VERSION 5.8 ;
BUSBITCHARS "[]" ;
DIVIDERCHAR "/" ;
UNITS
    DATABASE MICRONS 1000 ;
END UNITS

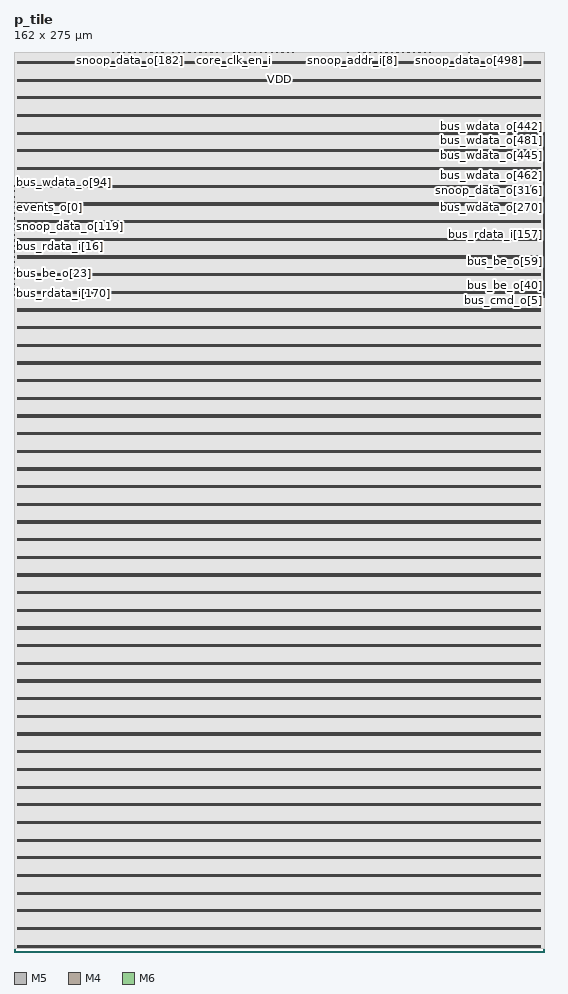
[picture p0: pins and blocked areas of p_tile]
MACRO p_tile
  FOREIGN p_tile 0 0 ;
  CLASS BLOCK ;
  SIZE 162 BY 275 ;
  PIN bus_addr_o[0]
    DIRECTION OUTPUT ;
    USE SIGNAL ;
    PORT
      LAYER M5 ;
        RECT  121.632 274.916 121.656 275 ;
    END
  END bus_addr_o[0]
  PIN bus_addr_o[10]
    DIRECTION OUTPUT ;
    USE SIGNAL ;
    PORT
      LAYER M4 ;
        RECT  0 207.072 0.084 207.096 ;
    END
  END bus_addr_o[10]
  PIN bus_addr_o[11]
    DIRECTION OUTPUT ;
    USE SIGNAL ;
    PORT
      LAYER M4 ;
        RECT  0 204.48 0.084 204.504 ;
    END
  END bus_addr_o[11]
  PIN bus_addr_o[12]
    DIRECTION OUTPUT ;
    USE SIGNAL ;
    PORT
      LAYER M4 ;
        RECT  0 204.384 0.084 204.408 ;
    END
  END bus_addr_o[12]
  PIN bus_addr_o[13]
    DIRECTION OUTPUT ;
    USE SIGNAL ;
    PORT
      LAYER M4 ;
        RECT  0 205.92 0.084 205.944 ;
    END
  END bus_addr_o[13]
  PIN bus_addr_o[14]
    DIRECTION OUTPUT ;
    USE SIGNAL ;
    PORT
      LAYER M4 ;
        RECT  0 200.64 0.084 200.664 ;
    END
  END bus_addr_o[14]
  PIN bus_addr_o[15]
    DIRECTION OUTPUT ;
    USE SIGNAL ;
    PORT
      LAYER M4 ;
        RECT  0 204.096 0.084 204.12 ;
    END
  END bus_addr_o[15]
  PIN bus_addr_o[16]
    DIRECTION OUTPUT ;
    USE SIGNAL ;
    PORT
      LAYER M4 ;
        RECT  0 206.88 0.084 206.904 ;
    END
  END bus_addr_o[16]
  PIN bus_addr_o[17]
    DIRECTION OUTPUT ;
    USE SIGNAL ;
    PORT
      LAYER M4 ;
        RECT  0 202.368 0.084 202.392 ;
    END
  END bus_addr_o[17]
  PIN bus_addr_o[18]
    DIRECTION OUTPUT ;
    USE SIGNAL ;
    PORT
      LAYER M4 ;
        RECT  0 206.112 0.084 206.136 ;
    END
  END bus_addr_o[18]
  PIN bus_addr_o[19]
    DIRECTION OUTPUT ;
    USE SIGNAL ;
    PORT
      LAYER M4 ;
        RECT  0 207.84 0.084 207.864 ;
    END
  END bus_addr_o[19]
  PIN bus_addr_o[1]
    DIRECTION OUTPUT ;
    USE SIGNAL ;
    PORT
      LAYER M5 ;
        RECT  106.656 274.916 106.68 275 ;
    END
  END bus_addr_o[1]
  PIN bus_addr_o[20]
    DIRECTION OUTPUT ;
    USE SIGNAL ;
    PORT
      LAYER M4 ;
        RECT  0 201.216 0.084 201.24 ;
    END
  END bus_addr_o[20]
  PIN bus_addr_o[21]
    DIRECTION OUTPUT ;
    USE SIGNAL ;
    PORT
      LAYER M4 ;
        RECT  0 202.272 0.084 202.296 ;
    END
  END bus_addr_o[21]
  PIN bus_addr_o[22]
    DIRECTION OUTPUT ;
    USE SIGNAL ;
    PORT
      LAYER M4 ;
        RECT  0 207.168 0.084 207.192 ;
    END
  END bus_addr_o[22]
  PIN bus_addr_o[23]
    DIRECTION OUTPUT ;
    USE SIGNAL ;
    PORT
      LAYER M4 ;
        RECT  0 204.864 0.084 204.888 ;
    END
  END bus_addr_o[23]
  PIN bus_addr_o[24]
    DIRECTION OUTPUT ;
    USE SIGNAL ;
    PORT
      LAYER M4 ;
        RECT  0 211.008 0.084 211.032 ;
    END
  END bus_addr_o[24]
  PIN bus_addr_o[25]
    DIRECTION OUTPUT ;
    USE SIGNAL ;
    PORT
      LAYER M4 ;
        RECT  0 209.472 0.084 209.496 ;
    END
  END bus_addr_o[25]
  PIN bus_addr_o[26]
    DIRECTION OUTPUT ;
    USE SIGNAL ;
    PORT
      LAYER M4 ;
        RECT  0 205.056 0.084 205.08 ;
    END
  END bus_addr_o[26]
  PIN bus_addr_o[27]
    DIRECTION OUTPUT ;
    USE SIGNAL ;
    PORT
      LAYER M4 ;
        RECT  0 211.392 0.084 211.416 ;
    END
  END bus_addr_o[27]
  PIN bus_addr_o[28]
    DIRECTION OUTPUT ;
    USE SIGNAL ;
    PORT
      LAYER M4 ;
        RECT  0 211.584 0.084 211.608 ;
    END
  END bus_addr_o[28]
  PIN bus_addr_o[29]
    DIRECTION OUTPUT ;
    USE SIGNAL ;
    PORT
      LAYER M4 ;
        RECT  0 204.672 0.084 204.696 ;
    END
  END bus_addr_o[29]
  PIN bus_addr_o[2]
    DIRECTION OUTPUT ;
    USE SIGNAL ;
    PORT
      LAYER M4 ;
        RECT  0 207.744 0.084 207.768 ;
    END
  END bus_addr_o[2]
  PIN bus_addr_o[30]
    DIRECTION OUTPUT ;
    USE SIGNAL ;
    PORT
      LAYER M4 ;
        RECT  0 209.76 0.084 209.784 ;
    END
  END bus_addr_o[30]
  PIN bus_addr_o[31]
    DIRECTION OUTPUT ;
    USE SIGNAL ;
    PORT
      LAYER M4 ;
        RECT  0 210.24 0.084 210.264 ;
    END
  END bus_addr_o[31]
  PIN bus_addr_o[32]
    DIRECTION OUTPUT ;
    USE SIGNAL ;
    PORT
      LAYER M5 ;
        RECT  121.344 274.916 121.368 275 ;
    END
  END bus_addr_o[32]
  PIN bus_addr_o[33]
    DIRECTION OUTPUT ;
    USE SIGNAL ;
    PORT
      LAYER M5 ;
        RECT  121.728 274.916 121.752 275 ;
    END
  END bus_addr_o[33]
  PIN bus_addr_o[34]
    DIRECTION OUTPUT ;
    USE SIGNAL ;
    PORT
      LAYER M4 ;
        RECT  161.916 203.232 162 203.256 ;
    END
  END bus_addr_o[34]
  PIN bus_addr_o[35]
    DIRECTION OUTPUT ;
    USE SIGNAL ;
    PORT
      LAYER M4 ;
        RECT  161.916 206.496 162 206.52 ;
    END
  END bus_addr_o[35]
  PIN bus_addr_o[36]
    DIRECTION OUTPUT ;
    USE SIGNAL ;
    PORT
      LAYER M4 ;
        RECT  161.916 208.608 162 208.632 ;
    END
  END bus_addr_o[36]
  PIN bus_addr_o[37]
    DIRECTION OUTPUT ;
    USE SIGNAL ;
    PORT
      LAYER M4 ;
        RECT  161.916 205.92 162 205.944 ;
    END
  END bus_addr_o[37]
  PIN bus_addr_o[38]
    DIRECTION OUTPUT ;
    USE SIGNAL ;
    PORT
      LAYER M4 ;
        RECT  161.916 204.48 162 204.504 ;
    END
  END bus_addr_o[38]
  PIN bus_addr_o[39]
    DIRECTION OUTPUT ;
    USE SIGNAL ;
    PORT
      LAYER M4 ;
        RECT  161.916 206.016 162 206.04 ;
    END
  END bus_addr_o[39]
  PIN bus_addr_o[3]
    DIRECTION OUTPUT ;
    USE SIGNAL ;
    PORT
      LAYER M4 ;
        RECT  0 213.408 0.084 213.432 ;
    END
  END bus_addr_o[3]
  PIN bus_addr_o[40]
    DIRECTION OUTPUT ;
    USE SIGNAL ;
    PORT
      LAYER M4 ;
        RECT  161.916 208.128 162 208.152 ;
    END
  END bus_addr_o[40]
  PIN bus_addr_o[41]
    DIRECTION OUTPUT ;
    USE SIGNAL ;
    PORT
      LAYER M4 ;
        RECT  161.916 207.456 162 207.48 ;
    END
  END bus_addr_o[41]
  PIN bus_addr_o[42]
    DIRECTION OUTPUT ;
    USE SIGNAL ;
    PORT
      LAYER M4 ;
        RECT  161.916 210.816 162 210.84 ;
    END
  END bus_addr_o[42]
  PIN bus_addr_o[43]
    DIRECTION OUTPUT ;
    USE SIGNAL ;
    PORT
      LAYER M4 ;
        RECT  161.916 206.784 162 206.808 ;
    END
  END bus_addr_o[43]
  PIN bus_addr_o[44]
    DIRECTION OUTPUT ;
    USE SIGNAL ;
    PORT
      LAYER M4 ;
        RECT  161.916 205.344 162 205.368 ;
    END
  END bus_addr_o[44]
  PIN bus_addr_o[45]
    DIRECTION OUTPUT ;
    USE SIGNAL ;
    PORT
      LAYER M4 ;
        RECT  161.916 206.976 162 207 ;
    END
  END bus_addr_o[45]
  PIN bus_addr_o[46]
    DIRECTION OUTPUT ;
    USE SIGNAL ;
    PORT
      LAYER M4 ;
        RECT  161.916 204.384 162 204.408 ;
    END
  END bus_addr_o[46]
  PIN bus_addr_o[47]
    DIRECTION OUTPUT ;
    USE SIGNAL ;
    PORT
      LAYER M4 ;
        RECT  161.916 204.768 162 204.792 ;
    END
  END bus_addr_o[47]
  PIN bus_addr_o[48]
    DIRECTION OUTPUT ;
    USE SIGNAL ;
    PORT
      LAYER M4 ;
        RECT  161.916 203.904 162 203.928 ;
    END
  END bus_addr_o[48]
  PIN bus_addr_o[49]
    DIRECTION OUTPUT ;
    USE SIGNAL ;
    PORT
      LAYER M4 ;
        RECT  161.916 204.576 162 204.6 ;
    END
  END bus_addr_o[49]
  PIN bus_addr_o[4]
    DIRECTION OUTPUT ;
    USE SIGNAL ;
    PORT
      LAYER M4 ;
        RECT  0 205.632 0.084 205.656 ;
    END
  END bus_addr_o[4]
  PIN bus_addr_o[50]
    DIRECTION OUTPUT ;
    USE SIGNAL ;
    PORT
      LAYER M4 ;
        RECT  161.916 202.08 162 202.104 ;
    END
  END bus_addr_o[50]
  PIN bus_addr_o[51]
    DIRECTION OUTPUT ;
    USE SIGNAL ;
    PORT
      LAYER M4 ;
        RECT  161.916 205.632 162 205.656 ;
    END
  END bus_addr_o[51]
  PIN bus_addr_o[52]
    DIRECTION OUTPUT ;
    USE SIGNAL ;
    PORT
      LAYER M4 ;
        RECT  161.916 208.224 162 208.248 ;
    END
  END bus_addr_o[52]
  PIN bus_addr_o[53]
    DIRECTION OUTPUT ;
    USE SIGNAL ;
    PORT
      LAYER M4 ;
        RECT  161.916 207.072 162 207.096 ;
    END
  END bus_addr_o[53]
  PIN bus_addr_o[54]
    DIRECTION OUTPUT ;
    USE SIGNAL ;
    PORT
      LAYER M4 ;
        RECT  161.916 208.704 162 208.728 ;
    END
  END bus_addr_o[54]
  PIN bus_addr_o[55]
    DIRECTION OUTPUT ;
    USE SIGNAL ;
    PORT
      LAYER M4 ;
        RECT  161.916 203.328 162 203.352 ;
    END
  END bus_addr_o[55]
  PIN bus_addr_o[56]
    DIRECTION OUTPUT ;
    USE SIGNAL ;
    PORT
      LAYER M4 ;
        RECT  161.916 208.896 162 208.92 ;
    END
  END bus_addr_o[56]
  PIN bus_addr_o[57]
    DIRECTION OUTPUT ;
    USE SIGNAL ;
    PORT
      LAYER M4 ;
        RECT  161.916 204.192 162 204.216 ;
    END
  END bus_addr_o[57]
  PIN bus_addr_o[58]
    DIRECTION OUTPUT ;
    USE SIGNAL ;
    PORT
      LAYER M4 ;
        RECT  161.916 209.184 162 209.208 ;
    END
  END bus_addr_o[58]
  PIN bus_addr_o[59]
    DIRECTION OUTPUT ;
    USE SIGNAL ;
    PORT
      LAYER M4 ;
        RECT  161.916 207.264 162 207.288 ;
    END
  END bus_addr_o[59]
  PIN bus_addr_o[5]
    DIRECTION OUTPUT ;
    USE SIGNAL ;
    PORT
      LAYER M4 ;
        RECT  0 211.776 0.084 211.8 ;
    END
  END bus_addr_o[5]
  PIN bus_addr_o[60]
    DIRECTION OUTPUT ;
    USE SIGNAL ;
    PORT
      LAYER M4 ;
        RECT  161.916 205.728 162 205.752 ;
    END
  END bus_addr_o[60]
  PIN bus_addr_o[61]
    DIRECTION OUTPUT ;
    USE SIGNAL ;
    PORT
      LAYER M4 ;
        RECT  161.916 211.392 162 211.416 ;
    END
  END bus_addr_o[61]
  PIN bus_addr_o[62]
    DIRECTION OUTPUT ;
    USE SIGNAL ;
    PORT
      LAYER M4 ;
        RECT  161.916 203.808 162 203.832 ;
    END
  END bus_addr_o[62]
  PIN bus_addr_o[63]
    DIRECTION OUTPUT ;
    USE SIGNAL ;
    PORT
      LAYER M4 ;
        RECT  161.916 205.824 162 205.848 ;
    END
  END bus_addr_o[63]
  PIN bus_addr_o[6]
    DIRECTION OUTPUT ;
    USE SIGNAL ;
    PORT
      LAYER M4 ;
        RECT  0 207.552 0.084 207.576 ;
    END
  END bus_addr_o[6]
  PIN bus_addr_o[7]
    DIRECTION OUTPUT ;
    USE SIGNAL ;
    PORT
      LAYER M4 ;
        RECT  0 209.952 0.084 209.976 ;
    END
  END bus_addr_o[7]
  PIN bus_addr_o[8]
    DIRECTION OUTPUT ;
    USE SIGNAL ;
    PORT
      LAYER M4 ;
        RECT  0 200.544 0.084 200.568 ;
    END
  END bus_addr_o[8]
  PIN bus_addr_o[9]
    DIRECTION OUTPUT ;
    USE SIGNAL ;
    PORT
      LAYER M4 ;
        RECT  0 200.256 0.084 200.28 ;
    END
  END bus_addr_o[9]
  PIN bus_be_o[0]
    DIRECTION OUTPUT ;
    USE SIGNAL ;
    PORT
      LAYER M4 ;
        RECT  0 201.6 0.084 201.624 ;
    END
  END bus_be_o[0]
  PIN bus_be_o[10]
    DIRECTION OUTPUT ;
    USE SIGNAL ;
    PORT
      LAYER M4 ;
        RECT  0 212.544 0.084 212.568 ;
    END
  END bus_be_o[10]
  PIN bus_be_o[11]
    DIRECTION OUTPUT ;
    USE SIGNAL ;
    PORT
      LAYER M4 ;
        RECT  0 205.536 0.084 205.56 ;
    END
  END bus_be_o[11]
  PIN bus_be_o[12]
    DIRECTION OUTPUT ;
    USE SIGNAL ;
    PORT
      LAYER M4 ;
        RECT  0 210.912 0.084 210.936 ;
    END
  END bus_be_o[12]
  PIN bus_be_o[13]
    DIRECTION OUTPUT ;
    USE SIGNAL ;
    PORT
      LAYER M4 ;
        RECT  0 204.96 0.084 204.984 ;
    END
  END bus_be_o[13]
  PIN bus_be_o[14]
    DIRECTION OUTPUT ;
    USE SIGNAL ;
    PORT
      LAYER M4 ;
        RECT  0 208.512 0.084 208.536 ;
    END
  END bus_be_o[14]
  PIN bus_be_o[15]
    DIRECTION OUTPUT ;
    USE SIGNAL ;
    PORT
      LAYER M4 ;
        RECT  0 204.192 0.084 204.216 ;
    END
  END bus_be_o[15]
  PIN bus_be_o[16]
    DIRECTION OUTPUT ;
    USE SIGNAL ;
    PORT
      LAYER M4 ;
        RECT  0 212.064 0.084 212.088 ;
    END
  END bus_be_o[16]
  PIN bus_be_o[17]
    DIRECTION OUTPUT ;
    USE SIGNAL ;
    PORT
      LAYER M4 ;
        RECT  0 210.816 0.084 210.84 ;
    END
  END bus_be_o[17]
  PIN bus_be_o[18]
    DIRECTION OUTPUT ;
    USE SIGNAL ;
    PORT
      LAYER M4 ;
        RECT  0 210.528 0.084 210.552 ;
    END
  END bus_be_o[18]
  PIN bus_be_o[19]
    DIRECTION OUTPUT ;
    USE SIGNAL ;
    PORT
      LAYER M4 ;
        RECT  0 202.944 0.084 202.968 ;
    END
  END bus_be_o[19]
  PIN bus_be_o[1]
    DIRECTION OUTPUT ;
    USE SIGNAL ;
    PORT
      LAYER M4 ;
        RECT  0 210.624 0.084 210.648 ;
    END
  END bus_be_o[1]
  PIN bus_be_o[20]
    DIRECTION OUTPUT ;
    USE SIGNAL ;
    PORT
      LAYER M4 ;
        RECT  0 212.256 0.084 212.28 ;
    END
  END bus_be_o[20]
  PIN bus_be_o[21]
    DIRECTION OUTPUT ;
    USE SIGNAL ;
    PORT
      LAYER M4 ;
        RECT  0 208.8 0.084 208.824 ;
    END
  END bus_be_o[21]
  PIN bus_be_o[22]
    DIRECTION OUTPUT ;
    USE SIGNAL ;
    PORT
      LAYER M4 ;
        RECT  0 207.456 0.084 207.48 ;
    END
  END bus_be_o[22]
  PIN bus_be_o[23]
    DIRECTION OUTPUT ;
    USE SIGNAL ;
    PORT
      LAYER M4 ;
        RECT  0 207.36 0.084 207.384 ;
    END
  END bus_be_o[23]
  PIN bus_be_o[24]
    DIRECTION OUTPUT ;
    USE SIGNAL ;
    PORT
      LAYER M4 ;
        RECT  0 200.736 0.084 200.76 ;
    END
  END bus_be_o[24]
  PIN bus_be_o[25]
    DIRECTION OUTPUT ;
    USE SIGNAL ;
    PORT
      LAYER M4 ;
        RECT  0 202.176 0.084 202.2 ;
    END
  END bus_be_o[25]
  PIN bus_be_o[26]
    DIRECTION OUTPUT ;
    USE SIGNAL ;
    PORT
      LAYER M4 ;
        RECT  0 205.824 0.084 205.848 ;
    END
  END bus_be_o[26]
  PIN bus_be_o[27]
    DIRECTION OUTPUT ;
    USE SIGNAL ;
    PORT
      LAYER M4 ;
        RECT  0 206.688 0.084 206.712 ;
    END
  END bus_be_o[27]
  PIN bus_be_o[28]
    DIRECTION OUTPUT ;
    USE SIGNAL ;
    PORT
      LAYER M4 ;
        RECT  0 202.08 0.084 202.104 ;
    END
  END bus_be_o[28]
  PIN bus_be_o[29]
    DIRECTION OUTPUT ;
    USE SIGNAL ;
    PORT
      LAYER M4 ;
        RECT  0 214.176 0.084 214.2 ;
    END
  END bus_be_o[29]
  PIN bus_be_o[2]
    DIRECTION OUTPUT ;
    USE SIGNAL ;
    PORT
      LAYER M4 ;
        RECT  0 210.048 0.084 210.072 ;
    END
  END bus_be_o[2]
  PIN bus_be_o[30]
    DIRECTION OUTPUT ;
    USE SIGNAL ;
    PORT
      LAYER M4 ;
        RECT  0 210.144 0.084 210.168 ;
    END
  END bus_be_o[30]
  PIN bus_be_o[31]
    DIRECTION OUTPUT ;
    USE SIGNAL ;
    PORT
      LAYER M4 ;
        RECT  0 200.352 0.084 200.376 ;
    END
  END bus_be_o[31]
  PIN bus_be_o[32]
    DIRECTION OUTPUT ;
    USE SIGNAL ;
    PORT
      LAYER M4 ;
        RECT  161.916 206.592 162 206.616 ;
    END
  END bus_be_o[32]
  PIN bus_be_o[33]
    DIRECTION OUTPUT ;
    USE SIGNAL ;
    PORT
      LAYER M4 ;
        RECT  161.916 211.2 162 211.224 ;
    END
  END bus_be_o[33]
  PIN bus_be_o[34]
    DIRECTION OUTPUT ;
    USE SIGNAL ;
    PORT
      LAYER M4 ;
        RECT  161.916 210.144 162 210.168 ;
    END
  END bus_be_o[34]
  PIN bus_be_o[35]
    DIRECTION OUTPUT ;
    USE SIGNAL ;
    PORT
      LAYER M4 ;
        RECT  161.916 203.52 162 203.544 ;
    END
  END bus_be_o[35]
  PIN bus_be_o[36]
    DIRECTION OUTPUT ;
    USE SIGNAL ;
    PORT
      LAYER M4 ;
        RECT  161.916 209.376 162 209.4 ;
    END
  END bus_be_o[36]
  PIN bus_be_o[37]
    DIRECTION OUTPUT ;
    USE SIGNAL ;
    PORT
      LAYER M4 ;
        RECT  161.916 203.712 162 203.736 ;
    END
  END bus_be_o[37]
  PIN bus_be_o[38]
    DIRECTION OUTPUT ;
    USE SIGNAL ;
    PORT
      LAYER M4 ;
        RECT  161.916 207.648 162 207.672 ;
    END
  END bus_be_o[38]
  PIN bus_be_o[39]
    DIRECTION OUTPUT ;
    USE SIGNAL ;
    PORT
      LAYER M4 ;
        RECT  161.916 206.304 162 206.328 ;
    END
  END bus_be_o[39]
  PIN bus_be_o[3]
    DIRECTION OUTPUT ;
    USE SIGNAL ;
    PORT
      LAYER M4 ;
        RECT  0 205.728 0.084 205.752 ;
    END
  END bus_be_o[3]
  PIN bus_be_o[40]
    DIRECTION OUTPUT ;
    USE SIGNAL ;
    PORT
      LAYER M4 ;
        RECT  161.916 203.616 162 203.64 ;
    END
  END bus_be_o[40]
  PIN bus_be_o[41]
    DIRECTION OUTPUT ;
    USE SIGNAL ;
    PORT
      LAYER M4 ;
        RECT  161.916 208.8 162 208.824 ;
    END
  END bus_be_o[41]
  PIN bus_be_o[42]
    DIRECTION OUTPUT ;
    USE SIGNAL ;
    PORT
      LAYER M4 ;
        RECT  161.916 208.032 162 208.056 ;
    END
  END bus_be_o[42]
  PIN bus_be_o[43]
    DIRECTION OUTPUT ;
    USE SIGNAL ;
    PORT
      LAYER M4 ;
        RECT  161.916 205.44 162 205.464 ;
    END
  END bus_be_o[43]
  PIN bus_be_o[44]
    DIRECTION OUTPUT ;
    USE SIGNAL ;
    PORT
      LAYER M4 ;
        RECT  161.916 211.008 162 211.032 ;
    END
  END bus_be_o[44]
  PIN bus_be_o[45]
    DIRECTION OUTPUT ;
    USE SIGNAL ;
    PORT
      LAYER M4 ;
        RECT  161.916 207.936 162 207.96 ;
    END
  END bus_be_o[45]
  PIN bus_be_o[46]
    DIRECTION OUTPUT ;
    USE SIGNAL ;
    PORT
      LAYER M4 ;
        RECT  161.916 205.248 162 205.272 ;
    END
  END bus_be_o[46]
  PIN bus_be_o[47]
    DIRECTION OUTPUT ;
    USE SIGNAL ;
    PORT
      LAYER M4 ;
        RECT  161.916 211.776 162 211.8 ;
    END
  END bus_be_o[47]
  PIN bus_be_o[48]
    DIRECTION OUTPUT ;
    USE SIGNAL ;
    PORT
      LAYER M4 ;
        RECT  161.916 202.944 162 202.968 ;
    END
  END bus_be_o[48]
  PIN bus_be_o[49]
    DIRECTION OUTPUT ;
    USE SIGNAL ;
    PORT
      LAYER M4 ;
        RECT  161.916 210.432 162 210.456 ;
    END
  END bus_be_o[49]
  PIN bus_be_o[4]
    DIRECTION OUTPUT ;
    USE SIGNAL ;
    PORT
      LAYER M4 ;
        RECT  0 200.928 0.084 200.952 ;
    END
  END bus_be_o[4]
  PIN bus_be_o[50]
    DIRECTION OUTPUT ;
    USE SIGNAL ;
    PORT
      LAYER M4 ;
        RECT  161.916 203.136 162 203.16 ;
    END
  END bus_be_o[50]
  PIN bus_be_o[51]
    DIRECTION OUTPUT ;
    USE SIGNAL ;
    PORT
      LAYER M4 ;
        RECT  161.916 205.536 162 205.56 ;
    END
  END bus_be_o[51]
  PIN bus_be_o[52]
    DIRECTION OUTPUT ;
    USE SIGNAL ;
    PORT
      LAYER M4 ;
        RECT  161.916 209.952 162 209.976 ;
    END
  END bus_be_o[52]
  PIN bus_be_o[53]
    DIRECTION OUTPUT ;
    USE SIGNAL ;
    PORT
      LAYER M4 ;
        RECT  161.916 205.056 162 205.08 ;
    END
  END bus_be_o[53]
  PIN bus_be_o[54]
    DIRECTION OUTPUT ;
    USE SIGNAL ;
    PORT
      LAYER M4 ;
        RECT  161.916 204.288 162 204.312 ;
    END
  END bus_be_o[54]
  PIN bus_be_o[55]
    DIRECTION OUTPUT ;
    USE SIGNAL ;
    PORT
      LAYER M4 ;
        RECT  161.916 208.416 162 208.44 ;
    END
  END bus_be_o[55]
  PIN bus_be_o[56]
    DIRECTION OUTPUT ;
    USE SIGNAL ;
    PORT
      LAYER M4 ;
        RECT  161.916 206.88 162 206.904 ;
    END
  END bus_be_o[56]
  PIN bus_be_o[57]
    DIRECTION OUTPUT ;
    USE SIGNAL ;
    PORT
      LAYER M4 ;
        RECT  161.916 205.152 162 205.176 ;
    END
  END bus_be_o[57]
  PIN bus_be_o[58]
    DIRECTION OUTPUT ;
    USE SIGNAL ;
    PORT
      LAYER M4 ;
        RECT  161.916 210.336 162 210.36 ;
    END
  END bus_be_o[58]
  PIN bus_be_o[59]
    DIRECTION OUTPUT ;
    USE SIGNAL ;
    PORT
      LAYER M4 ;
        RECT  161.916 211.104 162 211.128 ;
    END
  END bus_be_o[59]
  PIN bus_be_o[5]
    DIRECTION OUTPUT ;
    USE SIGNAL ;
    PORT
      LAYER M4 ;
        RECT  0 206.4 0.084 206.424 ;
    END
  END bus_be_o[5]
  PIN bus_be_o[60]
    DIRECTION OUTPUT ;
    USE SIGNAL ;
    PORT
      LAYER M4 ;
        RECT  161.916 207.552 162 207.576 ;
    END
  END bus_be_o[60]
  PIN bus_be_o[61]
    DIRECTION OUTPUT ;
    USE SIGNAL ;
    PORT
      LAYER M4 ;
        RECT  161.916 210.624 162 210.648 ;
    END
  END bus_be_o[61]
  PIN bus_be_o[62]
    DIRECTION OUTPUT ;
    USE SIGNAL ;
    PORT
      LAYER M4 ;
        RECT  161.916 206.112 162 206.136 ;
    END
  END bus_be_o[62]
  PIN bus_be_o[63]
    DIRECTION OUTPUT ;
    USE SIGNAL ;
    PORT
      LAYER M4 ;
        RECT  161.916 207.36 162 207.384 ;
    END
  END bus_be_o[63]
  PIN bus_be_o[6]
    DIRECTION OUTPUT ;
    USE SIGNAL ;
    PORT
      LAYER M4 ;
        RECT  0 207.264 0.084 207.288 ;
    END
  END bus_be_o[6]
  PIN bus_be_o[7]
    DIRECTION OUTPUT ;
    USE SIGNAL ;
    PORT
      LAYER M4 ;
        RECT  0 210.72 0.084 210.744 ;
    END
  END bus_be_o[7]
  PIN bus_be_o[8]
    DIRECTION OUTPUT ;
    USE SIGNAL ;
    PORT
      LAYER M4 ;
        RECT  0 208.704 0.084 208.728 ;
    END
  END bus_be_o[8]
  PIN bus_be_o[9]
    DIRECTION OUTPUT ;
    USE SIGNAL ;
    PORT
      LAYER M4 ;
        RECT  0 203.04 0.084 203.064 ;
    END
  END bus_be_o[9]
  PIN bus_cmd_o[0]
    DIRECTION OUTPUT ;
    USE SIGNAL ;
    PORT
      LAYER M4 ;
        RECT  0 206.016 0.084 206.04 ;
    END
  END bus_cmd_o[0]
  PIN bus_cmd_o[1]
    DIRECTION OUTPUT ;
    USE SIGNAL ;
    PORT
      LAYER M4 ;
        RECT  0 211.968 0.084 211.992 ;
    END
  END bus_cmd_o[1]
  PIN bus_cmd_o[2]
    DIRECTION OUTPUT ;
    USE SIGNAL ;
    PORT
      LAYER M4 ;
        RECT  0 212.928 0.084 212.952 ;
    END
  END bus_cmd_o[2]
  PIN bus_cmd_o[3]
    DIRECTION OUTPUT ;
    USE SIGNAL ;
    PORT
      LAYER M4 ;
        RECT  161.916 209.472 162 209.496 ;
    END
  END bus_cmd_o[3]
  PIN bus_cmd_o[4]
    DIRECTION OUTPUT ;
    USE SIGNAL ;
    PORT
      LAYER M4 ;
        RECT  161.916 208.512 162 208.536 ;
    END
  END bus_cmd_o[4]
  PIN bus_cmd_o[5]
    DIRECTION OUTPUT ;
    USE SIGNAL ;
    PORT
      LAYER M4 ;
        RECT  161.916 201.504 162 201.528 ;
    END
  END bus_cmd_o[5]
  PIN bus_done_i[0]
    DIRECTION INPUT ;
    USE SIGNAL ;
    PORT
      LAYER M4 ;
        RECT  0 207.936 0.084 207.96 ;
    END
  END bus_done_i[0]
  PIN bus_done_i[1]
    DIRECTION INPUT ;
    USE SIGNAL ;
    PORT
      LAYER M4 ;
        RECT  161.916 209.856 162 209.88 ;
    END
  END bus_done_i[1]
  PIN bus_err_i
    DIRECTION INPUT ;
    USE SIGNAL ;
    PORT
      LAYER M4 ;
        RECT  161.916 200.352 162 200.376 ;
    END
  END bus_err_i
  PIN bus_rdata_i[0]
    DIRECTION INPUT ;
    USE SIGNAL ;
    PORT
      LAYER M4 ;
        RECT  161.916 201.696 162 201.72 ;
    END
  END bus_rdata_i[0]
  PIN bus_rdata_i[100]
    DIRECTION INPUT ;
    USE SIGNAL ;
    PORT
      LAYER M4 ;
        RECT  161.916 206.208 162 206.232 ;
    END
  END bus_rdata_i[100]
  PIN bus_rdata_i[101]
    DIRECTION INPUT ;
    USE SIGNAL ;
    PORT
      LAYER M4 ;
        RECT  161.916 210.24 162 210.264 ;
    END
  END bus_rdata_i[101]
  PIN bus_rdata_i[102]
    DIRECTION INPUT ;
    USE SIGNAL ;
    PORT
      LAYER M4 ;
        RECT  161.916 206.4 162 206.424 ;
    END
  END bus_rdata_i[102]
  PIN bus_rdata_i[103]
    DIRECTION INPUT ;
    USE SIGNAL ;
    PORT
      LAYER M4 ;
        RECT  161.916 203.04 162 203.064 ;
    END
  END bus_rdata_i[103]
  PIN bus_rdata_i[104]
    DIRECTION INPUT ;
    USE SIGNAL ;
    PORT
      LAYER M4 ;
        RECT  161.916 202.272 162 202.296 ;
    END
  END bus_rdata_i[104]
  PIN bus_rdata_i[105]
    DIRECTION INPUT ;
    USE SIGNAL ;
    PORT
      LAYER M4 ;
        RECT  161.916 200.64 162 200.664 ;
    END
  END bus_rdata_i[105]
  PIN bus_rdata_i[106]
    DIRECTION INPUT ;
    USE SIGNAL ;
    PORT
      LAYER M4 ;
        RECT  161.916 201.216 162 201.24 ;
    END
  END bus_rdata_i[106]
  PIN bus_rdata_i[107]
    DIRECTION INPUT ;
    USE SIGNAL ;
    PORT
      LAYER M4 ;
        RECT  161.916 204.096 162 204.12 ;
    END
  END bus_rdata_i[107]
  PIN bus_rdata_i[108]
    DIRECTION INPUT ;
    USE SIGNAL ;
    PORT
      LAYER M4 ;
        RECT  161.916 202.368 162 202.392 ;
    END
  END bus_rdata_i[108]
  PIN bus_rdata_i[109]
    DIRECTION INPUT ;
    USE SIGNAL ;
    PORT
      LAYER M4 ;
        RECT  161.916 211.488 162 211.512 ;
    END
  END bus_rdata_i[109]
  PIN bus_rdata_i[10]
    DIRECTION INPUT ;
    USE SIGNAL ;
    PORT
      LAYER M4 ;
        RECT  161.916 200.256 162 200.28 ;
    END
  END bus_rdata_i[10]
  PIN bus_rdata_i[110]
    DIRECTION INPUT ;
    USE SIGNAL ;
    PORT
      LAYER M4 ;
        RECT  161.916 201.6 162 201.624 ;
    END
  END bus_rdata_i[110]
  PIN bus_rdata_i[111]
    DIRECTION INPUT ;
    USE SIGNAL ;
    PORT
      LAYER M4 ;
        RECT  161.916 201.408 162 201.432 ;
    END
  END bus_rdata_i[111]
  PIN bus_rdata_i[112]
    DIRECTION INPUT ;
    USE SIGNAL ;
    PORT
      LAYER M4 ;
        RECT  161.916 200.544 162 200.568 ;
    END
  END bus_rdata_i[112]
  PIN bus_rdata_i[113]
    DIRECTION INPUT ;
    USE SIGNAL ;
    PORT
      LAYER M4 ;
        RECT  161.916 201.024 162 201.048 ;
    END
  END bus_rdata_i[113]
  PIN bus_rdata_i[114]
    DIRECTION INPUT ;
    USE SIGNAL ;
    PORT
      LAYER M4 ;
        RECT  161.916 200.064 162 200.088 ;
    END
  END bus_rdata_i[114]
  PIN bus_rdata_i[115]
    DIRECTION INPUT ;
    USE SIGNAL ;
    PORT
      LAYER M4 ;
        RECT  161.916 211.872 162 211.896 ;
    END
  END bus_rdata_i[115]
  PIN bus_rdata_i[116]
    DIRECTION INPUT ;
    USE SIGNAL ;
    PORT
      LAYER M4 ;
        RECT  161.916 200.736 162 200.76 ;
    END
  END bus_rdata_i[116]
  PIN bus_rdata_i[117]
    DIRECTION INPUT ;
    USE SIGNAL ;
    PORT
      LAYER M4 ;
        RECT  161.916 200.448 162 200.472 ;
    END
  END bus_rdata_i[117]
  PIN bus_rdata_i[118]
    DIRECTION INPUT ;
    USE SIGNAL ;
    PORT
      LAYER M4 ;
        RECT  161.916 201.12 162 201.144 ;
    END
  END bus_rdata_i[118]
  PIN bus_rdata_i[119]
    DIRECTION INPUT ;
    USE SIGNAL ;
    PORT
      LAYER M4 ;
        RECT  161.916 208.992 162 209.016 ;
    END
  END bus_rdata_i[119]
  PIN bus_rdata_i[11]
    DIRECTION INPUT ;
    USE SIGNAL ;
    PORT
      LAYER M4 ;
        RECT  161.916 200.928 162 200.952 ;
    END
  END bus_rdata_i[11]
  PIN bus_rdata_i[120]
    DIRECTION INPUT ;
    USE SIGNAL ;
    PORT
      LAYER M4 ;
        RECT  161.916 204.96 162 204.984 ;
    END
  END bus_rdata_i[120]
  PIN bus_rdata_i[121]
    DIRECTION INPUT ;
    USE SIGNAL ;
    PORT
      LAYER M4 ;
        RECT  161.916 201.312 162 201.336 ;
    END
  END bus_rdata_i[121]
  PIN bus_rdata_i[122]
    DIRECTION INPUT ;
    USE SIGNAL ;
    PORT
      LAYER M4 ;
        RECT  161.916 209.664 162 209.688 ;
    END
  END bus_rdata_i[122]
  PIN bus_rdata_i[123]
    DIRECTION INPUT ;
    USE SIGNAL ;
    PORT
      LAYER M4 ;
        RECT  161.916 209.76 162 209.784 ;
    END
  END bus_rdata_i[123]
  PIN bus_rdata_i[124]
    DIRECTION INPUT ;
    USE SIGNAL ;
    PORT
      LAYER M4 ;
        RECT  161.916 209.568 162 209.592 ;
    END
  END bus_rdata_i[124]
  PIN bus_rdata_i[125]
    DIRECTION INPUT ;
    USE SIGNAL ;
    PORT
      LAYER M4 ;
        RECT  161.916 202.848 162 202.872 ;
    END
  END bus_rdata_i[125]
  PIN bus_rdata_i[126]
    DIRECTION INPUT ;
    USE SIGNAL ;
    PORT
      LAYER M4 ;
        RECT  161.916 201.888 162 201.912 ;
    END
  END bus_rdata_i[126]
  PIN bus_rdata_i[127]
    DIRECTION INPUT ;
    USE SIGNAL ;
    PORT
      LAYER M4 ;
        RECT  161.916 209.088 162 209.112 ;
    END
  END bus_rdata_i[127]
  PIN bus_rdata_i[128]
    DIRECTION INPUT ;
    USE SIGNAL ;
    PORT
      LAYER M4 ;
        RECT  161.916 211.296 162 211.32 ;
    END
  END bus_rdata_i[128]
  PIN bus_rdata_i[129]
    DIRECTION INPUT ;
    USE SIGNAL ;
    PORT
      LAYER M4 ;
        RECT  161.916 202.464 162 202.488 ;
    END
  END bus_rdata_i[129]
  PIN bus_rdata_i[12]
    DIRECTION INPUT ;
    USE SIGNAL ;
    PORT
      LAYER M4 ;
        RECT  161.916 202.752 162 202.776 ;
    END
  END bus_rdata_i[12]
  PIN bus_rdata_i[130]
    DIRECTION INPUT ;
    USE SIGNAL ;
    PORT
      LAYER M4 ;
        RECT  161.916 203.424 162 203.448 ;
    END
  END bus_rdata_i[130]
  PIN bus_rdata_i[131]
    DIRECTION INPUT ;
    USE SIGNAL ;
    PORT
      LAYER M4 ;
        RECT  161.916 201.984 162 202.008 ;
    END
  END bus_rdata_i[131]
  PIN bus_rdata_i[132]
    DIRECTION INPUT ;
    USE SIGNAL ;
    PORT
      LAYER M4 ;
        RECT  161.916 207.744 162 207.768 ;
    END
  END bus_rdata_i[132]
  PIN bus_rdata_i[133]
    DIRECTION INPUT ;
    USE SIGNAL ;
    PORT
      LAYER M4 ;
        RECT  161.916 209.28 162 209.304 ;
    END
  END bus_rdata_i[133]
  PIN bus_rdata_i[134]
    DIRECTION INPUT ;
    USE SIGNAL ;
    PORT
      LAYER M4 ;
        RECT  161.916 207.168 162 207.192 ;
    END
  END bus_rdata_i[134]
  PIN bus_rdata_i[135]
    DIRECTION INPUT ;
    USE SIGNAL ;
    PORT
      LAYER M4 ;
        RECT  161.916 200.832 162 200.856 ;
    END
  END bus_rdata_i[135]
  PIN bus_rdata_i[136]
    DIRECTION INPUT ;
    USE SIGNAL ;
    PORT
      LAYER M4 ;
        RECT  161.916 210.048 162 210.072 ;
    END
  END bus_rdata_i[136]
  PIN bus_rdata_i[137]
    DIRECTION INPUT ;
    USE SIGNAL ;
    PORT
      LAYER M4 ;
        RECT  161.916 201.792 162 201.816 ;
    END
  END bus_rdata_i[137]
  PIN bus_rdata_i[138]
    DIRECTION INPUT ;
    USE SIGNAL ;
    PORT
      LAYER M4 ;
        RECT  161.916 204.672 162 204.696 ;
    END
  END bus_rdata_i[138]
  PIN bus_rdata_i[139]
    DIRECTION INPUT ;
    USE SIGNAL ;
    PORT
      LAYER M4 ;
        RECT  161.916 211.584 162 211.608 ;
    END
  END bus_rdata_i[139]
  PIN bus_rdata_i[13]
    DIRECTION INPUT ;
    USE SIGNAL ;
    PORT
      LAYER M4 ;
        RECT  161.916 206.688 162 206.712 ;
    END
  END bus_rdata_i[13]
  PIN bus_rdata_i[140]
    DIRECTION INPUT ;
    USE SIGNAL ;
    PORT
      LAYER M4 ;
        RECT  161.916 202.656 162 202.68 ;
    END
  END bus_rdata_i[140]
  PIN bus_rdata_i[141]
    DIRECTION INPUT ;
    USE SIGNAL ;
    PORT
      LAYER M4 ;
        RECT  161.916 202.56 162 202.584 ;
    END
  END bus_rdata_i[141]
  PIN bus_rdata_i[142]
    DIRECTION INPUT ;
    USE SIGNAL ;
    PORT
      LAYER M4 ;
        RECT  161.916 202.176 162 202.2 ;
    END
  END bus_rdata_i[142]
  PIN bus_rdata_i[143]
    DIRECTION INPUT ;
    USE SIGNAL ;
    PORT
      LAYER M4 ;
        RECT  161.916 210.528 162 210.552 ;
    END
  END bus_rdata_i[143]
  PIN bus_rdata_i[144]
    DIRECTION INPUT ;
    USE SIGNAL ;
    PORT
      LAYER M4 ;
        RECT  161.916 204.864 162 204.888 ;
    END
  END bus_rdata_i[144]
  PIN bus_rdata_i[145]
    DIRECTION INPUT ;
    USE SIGNAL ;
    PORT
      LAYER M4 ;
        RECT  161.916 208.32 162 208.344 ;
    END
  END bus_rdata_i[145]
  PIN bus_rdata_i[146]
    DIRECTION INPUT ;
    USE SIGNAL ;
    PORT
      LAYER M4 ;
        RECT  161.916 204 162 204.024 ;
    END
  END bus_rdata_i[146]
  PIN bus_rdata_i[147]
    DIRECTION INPUT ;
    USE SIGNAL ;
    PORT
      LAYER M4 ;
        RECT  161.916 210.912 162 210.936 ;
    END
  END bus_rdata_i[147]
  PIN bus_rdata_i[148]
    DIRECTION INPUT ;
    USE SIGNAL ;
    PORT
      LAYER M4 ;
        RECT  161.916 210.72 162 210.744 ;
    END
  END bus_rdata_i[148]
  PIN bus_rdata_i[149]
    DIRECTION INPUT ;
    USE SIGNAL ;
    PORT
      LAYER M4 ;
        RECT  161.916 207.84 162 207.864 ;
    END
  END bus_rdata_i[149]
  PIN bus_rdata_i[14]
    DIRECTION INPUT ;
    USE SIGNAL ;
    PORT
      LAYER M4 ;
        RECT  161.916 200.16 162 200.184 ;
    END
  END bus_rdata_i[14]
  PIN bus_rdata_i[150]
    DIRECTION INPUT ;
    USE SIGNAL ;
    PORT
      LAYER M4 ;
        RECT  161.916 211.68 162 211.704 ;
    END
  END bus_rdata_i[150]
  PIN bus_rdata_i[151]
    DIRECTION INPUT ;
    USE SIGNAL ;
    PORT
      LAYER M4 ;
        RECT  0 202.752 0.084 202.776 ;
    END
  END bus_rdata_i[151]
  PIN bus_rdata_i[152]
    DIRECTION INPUT ;
    USE SIGNAL ;
    PORT
      LAYER M4 ;
        RECT  0 214.464 0.084 214.488 ;
    END
  END bus_rdata_i[152]
  PIN bus_rdata_i[153]
    DIRECTION INPUT ;
    USE SIGNAL ;
    PORT
      LAYER M4 ;
        RECT  0 205.344 0.084 205.368 ;
    END
  END bus_rdata_i[153]
  PIN bus_rdata_i[154]
    DIRECTION INPUT ;
    USE SIGNAL ;
    PORT
      LAYER M4 ;
        RECT  0 212.16 0.084 212.184 ;
    END
  END bus_rdata_i[154]
  PIN bus_rdata_i[155]
    DIRECTION INPUT ;
    USE SIGNAL ;
    PORT
      LAYER M4 ;
        RECT  0 201.408 0.084 201.432 ;
    END
  END bus_rdata_i[155]
  PIN bus_rdata_i[156]
    DIRECTION INPUT ;
    USE SIGNAL ;
    PORT
      LAYER M4 ;
        RECT  0 213.6 0.084 213.624 ;
    END
  END bus_rdata_i[156]
  PIN bus_rdata_i[157]
    DIRECTION INPUT ;
    USE SIGNAL ;
    PORT
      LAYER M4 ;
        RECT  161.916 219.36 162 219.384 ;
    END
  END bus_rdata_i[157]
  PIN bus_rdata_i[158]
    DIRECTION INPUT ;
    USE SIGNAL ;
    PORT
      LAYER M4 ;
        RECT  161.916 220.32 162 220.344 ;
    END
  END bus_rdata_i[158]
  PIN bus_rdata_i[159]
    DIRECTION INPUT ;
    USE SIGNAL ;
    PORT
      LAYER M4 ;
        RECT  0 207.648 0.084 207.672 ;
    END
  END bus_rdata_i[159]
  PIN bus_rdata_i[15]
    DIRECTION INPUT ;
    USE SIGNAL ;
    PORT
      LAYER M4 ;
        RECT  0 212.448 0.084 212.472 ;
    END
  END bus_rdata_i[15]
  PIN bus_rdata_i[160]
    DIRECTION INPUT ;
    USE SIGNAL ;
    PORT
      LAYER M4 ;
        RECT  0 205.248 0.084 205.272 ;
    END
  END bus_rdata_i[160]
  PIN bus_rdata_i[161]
    DIRECTION INPUT ;
    USE SIGNAL ;
    PORT
      LAYER M4 ;
        RECT  0 213.312 0.084 213.336 ;
    END
  END bus_rdata_i[161]
  PIN bus_rdata_i[162]
    DIRECTION INPUT ;
    USE SIGNAL ;
    PORT
      LAYER M4 ;
        RECT  0 200.832 0.084 200.856 ;
    END
  END bus_rdata_i[162]
  PIN bus_rdata_i[163]
    DIRECTION INPUT ;
    USE SIGNAL ;
    PORT
      LAYER M4 ;
        RECT  0 206.592 0.084 206.616 ;
    END
  END bus_rdata_i[163]
  PIN bus_rdata_i[164]
    DIRECTION INPUT ;
    USE SIGNAL ;
    PORT
      LAYER M4 ;
        RECT  0 215.52 0.084 215.544 ;
    END
  END bus_rdata_i[164]
  PIN bus_rdata_i[165]
    DIRECTION INPUT ;
    USE SIGNAL ;
    PORT
      LAYER M4 ;
        RECT  0 208.416 0.084 208.44 ;
    END
  END bus_rdata_i[165]
  PIN bus_rdata_i[166]
    DIRECTION INPUT ;
    USE SIGNAL ;
    PORT
      LAYER M4 ;
        RECT  0 209.568 0.084 209.592 ;
    END
  END bus_rdata_i[166]
  PIN bus_rdata_i[167]
    DIRECTION INPUT ;
    USE SIGNAL ;
    PORT
      LAYER M4 ;
        RECT  0 208.992 0.084 209.016 ;
    END
  END bus_rdata_i[167]
  PIN bus_rdata_i[168]
    DIRECTION INPUT ;
    USE SIGNAL ;
    PORT
      LAYER M4 ;
        RECT  0 203.328 0.084 203.352 ;
    END
  END bus_rdata_i[168]
  PIN bus_rdata_i[169]
    DIRECTION INPUT ;
    USE SIGNAL ;
    PORT
      LAYER M4 ;
        RECT  0 203.904 0.084 203.928 ;
    END
  END bus_rdata_i[169]
  PIN bus_rdata_i[16]
    DIRECTION INPUT ;
    USE SIGNAL ;
    PORT
      LAYER M4 ;
        RECT  0 215.616 0.084 215.64 ;
    END
  END bus_rdata_i[16]
  PIN bus_rdata_i[170]
    DIRECTION INPUT ;
    USE SIGNAL ;
    PORT
      LAYER M4 ;
        RECT  0 203.616 0.084 203.64 ;
    END
  END bus_rdata_i[170]
  PIN bus_rdata_i[171]
    DIRECTION INPUT ;
    USE SIGNAL ;
    PORT
      LAYER M4 ;
        RECT  161.916 212.928 162 212.952 ;
    END
  END bus_rdata_i[171]
  PIN bus_rdata_i[172]
    DIRECTION INPUT ;
    USE SIGNAL ;
    PORT
      LAYER M4 ;
        RECT  0 206.976 0.084 207 ;
    END
  END bus_rdata_i[172]
  PIN bus_rdata_i[173]
    DIRECTION INPUT ;
    USE SIGNAL ;
    PORT
      LAYER M4 ;
        RECT  0 209.856 0.084 209.88 ;
    END
  END bus_rdata_i[173]
  PIN bus_rdata_i[174]
    DIRECTION INPUT ;
    USE SIGNAL ;
    PORT
      LAYER M4 ;
        RECT  161.916 222.144 162 222.168 ;
    END
  END bus_rdata_i[174]
  PIN bus_rdata_i[175]
    DIRECTION INPUT ;
    USE SIGNAL ;
    PORT
      LAYER M4 ;
        RECT  0 208.032 0.084 208.056 ;
    END
  END bus_rdata_i[175]
  PIN bus_rdata_i[176]
    DIRECTION INPUT ;
    USE SIGNAL ;
    PORT
      LAYER M4 ;
        RECT  0 201.312 0.084 201.336 ;
    END
  END bus_rdata_i[176]
  PIN bus_rdata_i[177]
    DIRECTION INPUT ;
    USE SIGNAL ;
    PORT
      LAYER M4 ;
        RECT  0 211.104 0.084 211.128 ;
    END
  END bus_rdata_i[177]
  PIN bus_rdata_i[178]
    DIRECTION INPUT ;
    USE SIGNAL ;
    PORT
      LAYER M4 ;
        RECT  0 208.32 0.084 208.344 ;
    END
  END bus_rdata_i[178]
  PIN bus_rdata_i[179]
    DIRECTION INPUT ;
    USE SIGNAL ;
    PORT
      LAYER M4 ;
        RECT  0 204.768 0.084 204.792 ;
    END
  END bus_rdata_i[179]
  PIN bus_rdata_i[17]
    DIRECTION INPUT ;
    USE SIGNAL ;
    PORT
      LAYER M4 ;
        RECT  0 215.424 0.084 215.448 ;
    END
  END bus_rdata_i[17]
  PIN bus_rdata_i[180]
    DIRECTION INPUT ;
    USE SIGNAL ;
    PORT
      LAYER M4 ;
        RECT  0 202.848 0.084 202.872 ;
    END
  END bus_rdata_i[180]
  PIN bus_rdata_i[181]
    DIRECTION INPUT ;
    USE SIGNAL ;
    PORT
      LAYER M4 ;
        RECT  0 213.504 0.084 213.528 ;
    END
  END bus_rdata_i[181]
  PIN bus_rdata_i[182]
    DIRECTION INPUT ;
    USE SIGNAL ;
    PORT
      LAYER M4 ;
        RECT  161.916 220.032 162 220.056 ;
    END
  END bus_rdata_i[182]
  PIN bus_rdata_i[183]
    DIRECTION INPUT ;
    USE SIGNAL ;
    PORT
      LAYER M4 ;
        RECT  161.916 213.024 162 213.048 ;
    END
  END bus_rdata_i[183]
  PIN bus_rdata_i[184]
    DIRECTION INPUT ;
    USE SIGNAL ;
    PORT
      LAYER M4 ;
        RECT  0 208.608 0.084 208.632 ;
    END
  END bus_rdata_i[184]
  PIN bus_rdata_i[185]
    DIRECTION INPUT ;
    USE SIGNAL ;
    PORT
      LAYER M4 ;
        RECT  0 203.712 0.084 203.736 ;
    END
  END bus_rdata_i[185]
  PIN bus_rdata_i[186]
    DIRECTION INPUT ;
    USE SIGNAL ;
    PORT
      LAYER M4 ;
        RECT  0 211.68 0.084 211.704 ;
    END
  END bus_rdata_i[186]
  PIN bus_rdata_i[187]
    DIRECTION INPUT ;
    USE SIGNAL ;
    PORT
      LAYER M4 ;
        RECT  161.916 215.616 162 215.64 ;
    END
  END bus_rdata_i[187]
  PIN bus_rdata_i[188]
    DIRECTION INPUT ;
    USE SIGNAL ;
    PORT
      LAYER M4 ;
        RECT  0 211.296 0.084 211.32 ;
    END
  END bus_rdata_i[188]
  PIN bus_rdata_i[189]
    DIRECTION INPUT ;
    USE SIGNAL ;
    PORT
      LAYER M4 ;
        RECT  161.916 216.768 162 216.792 ;
    END
  END bus_rdata_i[189]
  PIN bus_rdata_i[18]
    DIRECTION INPUT ;
    USE SIGNAL ;
    PORT
      LAYER M4 ;
        RECT  0 214.944 0.084 214.968 ;
    END
  END bus_rdata_i[18]
  PIN bus_rdata_i[190]
    DIRECTION INPUT ;
    USE SIGNAL ;
    PORT
      LAYER M4 ;
        RECT  161.916 219.168 162 219.192 ;
    END
  END bus_rdata_i[190]
  PIN bus_rdata_i[191]
    DIRECTION INPUT ;
    USE SIGNAL ;
    PORT
      LAYER M4 ;
        RECT  161.916 222.816 162 222.84 ;
    END
  END bus_rdata_i[191]
  PIN bus_rdata_i[192]
    DIRECTION INPUT ;
    USE SIGNAL ;
    PORT
      LAYER M4 ;
        RECT  0 208.224 0.084 208.248 ;
    END
  END bus_rdata_i[192]
  PIN bus_rdata_i[193]
    DIRECTION INPUT ;
    USE SIGNAL ;
    PORT
      LAYER M4 ;
        RECT  161.916 219.744 162 219.768 ;
    END
  END bus_rdata_i[193]
  PIN bus_rdata_i[194]
    DIRECTION INPUT ;
    USE SIGNAL ;
    PORT
      LAYER M4 ;
        RECT  161.916 226.656 162 226.68 ;
    END
  END bus_rdata_i[194]
  PIN bus_rdata_i[195]
    DIRECTION INPUT ;
    USE SIGNAL ;
    PORT
      LAYER M4 ;
        RECT  161.916 217.728 162 217.752 ;
    END
  END bus_rdata_i[195]
  PIN bus_rdata_i[196]
    DIRECTION INPUT ;
    USE SIGNAL ;
    PORT
      LAYER M4 ;
        RECT  0 211.872 0.084 211.896 ;
    END
  END bus_rdata_i[196]
  PIN bus_rdata_i[197]
    DIRECTION INPUT ;
    USE SIGNAL ;
    PORT
      LAYER M4 ;
        RECT  0 203.136 0.084 203.16 ;
    END
  END bus_rdata_i[197]
  PIN bus_rdata_i[198]
    DIRECTION INPUT ;
    USE SIGNAL ;
    PORT
      LAYER M4 ;
        RECT  161.916 219.264 162 219.288 ;
    END
  END bus_rdata_i[198]
  PIN bus_rdata_i[199]
    DIRECTION INPUT ;
    USE SIGNAL ;
    PORT
      LAYER M4 ;
        RECT  161.916 230.88 162 230.904 ;
    END
  END bus_rdata_i[199]
  PIN bus_rdata_i[19]
    DIRECTION INPUT ;
    USE SIGNAL ;
    PORT
      LAYER M4 ;
        RECT  161.916 213.216 162 213.24 ;
    END
  END bus_rdata_i[19]
  PIN bus_rdata_i[1]
    DIRECTION INPUT ;
    USE SIGNAL ;
    PORT
      LAYER M4 ;
        RECT  0 209.376 0.084 209.4 ;
    END
  END bus_rdata_i[1]
  PIN bus_rdata_i[200]
    DIRECTION INPUT ;
    USE SIGNAL ;
    PORT
      LAYER M4 ;
        RECT  161.916 218.496 162 218.52 ;
    END
  END bus_rdata_i[200]
  PIN bus_rdata_i[201]
    DIRECTION INPUT ;
    USE SIGNAL ;
    PORT
      LAYER M4 ;
        RECT  161.916 221.568 162 221.592 ;
    END
  END bus_rdata_i[201]
  PIN bus_rdata_i[202]
    DIRECTION INPUT ;
    USE SIGNAL ;
    PORT
      LAYER M4 ;
        RECT  161.916 216.96 162 216.984 ;
    END
  END bus_rdata_i[202]
  PIN bus_rdata_i[203]
    DIRECTION INPUT ;
    USE SIGNAL ;
    PORT
      LAYER M4 ;
        RECT  161.916 220.896 162 220.92 ;
    END
  END bus_rdata_i[203]
  PIN bus_rdata_i[204]
    DIRECTION INPUT ;
    USE SIGNAL ;
    PORT
      LAYER M4 ;
        RECT  161.916 220.224 162 220.248 ;
    END
  END bus_rdata_i[204]
  PIN bus_rdata_i[205]
    DIRECTION INPUT ;
    USE SIGNAL ;
    PORT
      LAYER M4 ;
        RECT  161.916 227.712 162 227.736 ;
    END
  END bus_rdata_i[205]
  PIN bus_rdata_i[206]
    DIRECTION INPUT ;
    USE SIGNAL ;
    PORT
      LAYER M4 ;
        RECT  161.916 225.504 162 225.528 ;
    END
  END bus_rdata_i[206]
  PIN bus_rdata_i[207]
    DIRECTION INPUT ;
    USE SIGNAL ;
    PORT
      LAYER M4 ;
        RECT  161.916 215.808 162 215.832 ;
    END
  END bus_rdata_i[207]
  PIN bus_rdata_i[208]
    DIRECTION INPUT ;
    USE SIGNAL ;
    PORT
      LAYER M4 ;
        RECT  161.916 218.976 162 219 ;
    END
  END bus_rdata_i[208]
  PIN bus_rdata_i[209]
    DIRECTION INPUT ;
    USE SIGNAL ;
    PORT
      LAYER M4 ;
        RECT  161.916 217.632 162 217.656 ;
    END
  END bus_rdata_i[209]
  PIN bus_rdata_i[20]
    DIRECTION INPUT ;
    USE SIGNAL ;
    PORT
      LAYER M4 ;
        RECT  0 206.208 0.084 206.232 ;
    END
  END bus_rdata_i[20]
  PIN bus_rdata_i[210]
    DIRECTION INPUT ;
    USE SIGNAL ;
    PORT
      LAYER M4 ;
        RECT  161.916 218.208 162 218.232 ;
    END
  END bus_rdata_i[210]
  PIN bus_rdata_i[211]
    DIRECTION INPUT ;
    USE SIGNAL ;
    PORT
      LAYER M4 ;
        RECT  161.916 218.688 162 218.712 ;
    END
  END bus_rdata_i[211]
  PIN bus_rdata_i[212]
    DIRECTION INPUT ;
    USE SIGNAL ;
    PORT
      LAYER M4 ;
        RECT  161.916 224.064 162 224.088 ;
    END
  END bus_rdata_i[212]
  PIN bus_rdata_i[213]
    DIRECTION INPUT ;
    USE SIGNAL ;
    PORT
      LAYER M4 ;
        RECT  161.916 220.128 162 220.152 ;
    END
  END bus_rdata_i[213]
  PIN bus_rdata_i[214]
    DIRECTION INPUT ;
    USE SIGNAL ;
    PORT
      LAYER M4 ;
        RECT  161.916 216.672 162 216.696 ;
    END
  END bus_rdata_i[214]
  PIN bus_rdata_i[215]
    DIRECTION INPUT ;
    USE SIGNAL ;
    PORT
      LAYER M4 ;
        RECT  161.916 218.592 162 218.616 ;
    END
  END bus_rdata_i[215]
  PIN bus_rdata_i[216]
    DIRECTION INPUT ;
    USE SIGNAL ;
    PORT
      LAYER M4 ;
        RECT  161.916 229.92 162 229.944 ;
    END
  END bus_rdata_i[216]
  PIN bus_rdata_i[217]
    DIRECTION INPUT ;
    USE SIGNAL ;
    PORT
      LAYER M4 ;
        RECT  161.916 220.608 162 220.632 ;
    END
  END bus_rdata_i[217]
  PIN bus_rdata_i[218]
    DIRECTION INPUT ;
    USE SIGNAL ;
    PORT
      LAYER M4 ;
        RECT  0 209.28 0.084 209.304 ;
    END
  END bus_rdata_i[218]
  PIN bus_rdata_i[219]
    DIRECTION INPUT ;
    USE SIGNAL ;
    PORT
      LAYER M4 ;
        RECT  161.916 224.832 162 224.856 ;
    END
  END bus_rdata_i[219]
  PIN bus_rdata_i[21]
    DIRECTION INPUT ;
    USE SIGNAL ;
    PORT
      LAYER M4 ;
        RECT  0 213.792 0.084 213.816 ;
    END
  END bus_rdata_i[21]
  PIN bus_rdata_i[220]
    DIRECTION INPUT ;
    USE SIGNAL ;
    PORT
      LAYER M4 ;
        RECT  161.916 218.112 162 218.136 ;
    END
  END bus_rdata_i[220]
  PIN bus_rdata_i[221]
    DIRECTION INPUT ;
    USE SIGNAL ;
    PORT
      LAYER M4 ;
        RECT  161.916 214.656 162 214.68 ;
    END
  END bus_rdata_i[221]
  PIN bus_rdata_i[222]
    DIRECTION INPUT ;
    USE SIGNAL ;
    PORT
      LAYER M4 ;
        RECT  161.916 226.944 162 226.968 ;
    END
  END bus_rdata_i[222]
  PIN bus_rdata_i[223]
    DIRECTION INPUT ;
    USE SIGNAL ;
    PORT
      LAYER M4 ;
        RECT  161.916 222.048 162 222.072 ;
    END
  END bus_rdata_i[223]
  PIN bus_rdata_i[224]
    DIRECTION INPUT ;
    USE SIGNAL ;
    PORT
      LAYER M4 ;
        RECT  161.916 218.4 162 218.424 ;
    END
  END bus_rdata_i[224]
  PIN bus_rdata_i[225]
    DIRECTION INPUT ;
    USE SIGNAL ;
    PORT
      LAYER M4 ;
        RECT  161.916 228.576 162 228.6 ;
    END
  END bus_rdata_i[225]
  PIN bus_rdata_i[226]
    DIRECTION INPUT ;
    USE SIGNAL ;
    PORT
      LAYER M4 ;
        RECT  161.916 225.024 162 225.048 ;
    END
  END bus_rdata_i[226]
  PIN bus_rdata_i[227]
    DIRECTION INPUT ;
    USE SIGNAL ;
    PORT
      LAYER M4 ;
        RECT  161.916 226.56 162 226.584 ;
    END
  END bus_rdata_i[227]
  PIN bus_rdata_i[228]
    DIRECTION INPUT ;
    USE SIGNAL ;
    PORT
      LAYER M4 ;
        RECT  161.916 217.344 162 217.368 ;
    END
  END bus_rdata_i[228]
  PIN bus_rdata_i[229]
    DIRECTION INPUT ;
    USE SIGNAL ;
    PORT
      LAYER M4 ;
        RECT  161.916 224.256 162 224.28 ;
    END
  END bus_rdata_i[229]
  PIN bus_rdata_i[22]
    DIRECTION INPUT ;
    USE SIGNAL ;
    PORT
      LAYER M4 ;
        RECT  0 206.496 0.084 206.52 ;
    END
  END bus_rdata_i[22]
  PIN bus_rdata_i[230]
    DIRECTION INPUT ;
    USE SIGNAL ;
    PORT
      LAYER M4 ;
        RECT  161.916 225.216 162 225.24 ;
    END
  END bus_rdata_i[230]
  PIN bus_rdata_i[231]
    DIRECTION INPUT ;
    USE SIGNAL ;
    PORT
      LAYER M4 ;
        RECT  161.916 218.016 162 218.04 ;
    END
  END bus_rdata_i[231]
  PIN bus_rdata_i[232]
    DIRECTION INPUT ;
    USE SIGNAL ;
    PORT
      LAYER M4 ;
        RECT  161.916 214.368 162 214.392 ;
    END
  END bus_rdata_i[232]
  PIN bus_rdata_i[233]
    DIRECTION INPUT ;
    USE SIGNAL ;
    PORT
      LAYER M4 ;
        RECT  0 208.128 0.084 208.152 ;
    END
  END bus_rdata_i[233]
  PIN bus_rdata_i[234]
    DIRECTION INPUT ;
    USE SIGNAL ;
    PORT
      LAYER M4 ;
        RECT  161.916 213.12 162 213.144 ;
    END
  END bus_rdata_i[234]
  PIN bus_rdata_i[235]
    DIRECTION INPUT ;
    USE SIGNAL ;
    PORT
      LAYER M4 ;
        RECT  161.916 223.392 162 223.416 ;
    END
  END bus_rdata_i[235]
  PIN bus_rdata_i[236]
    DIRECTION INPUT ;
    USE SIGNAL ;
    PORT
      LAYER M4 ;
        RECT  161.916 216 162 216.024 ;
    END
  END bus_rdata_i[236]
  PIN bus_rdata_i[237]
    DIRECTION INPUT ;
    USE SIGNAL ;
    PORT
      LAYER M4 ;
        RECT  161.916 227.136 162 227.16 ;
    END
  END bus_rdata_i[237]
  PIN bus_rdata_i[238]
    DIRECTION INPUT ;
    USE SIGNAL ;
    PORT
      LAYER M4 ;
        RECT  161.916 228.864 162 228.888 ;
    END
  END bus_rdata_i[238]
  PIN bus_rdata_i[239]
    DIRECTION INPUT ;
    USE SIGNAL ;
    PORT
      LAYER M4 ;
        RECT  161.916 217.056 162 217.08 ;
    END
  END bus_rdata_i[239]
  PIN bus_rdata_i[23]
    DIRECTION INPUT ;
    USE SIGNAL ;
    PORT
      LAYER M4 ;
        RECT  0 213.984 0.084 214.008 ;
    END
  END bus_rdata_i[23]
  PIN bus_rdata_i[240]
    DIRECTION INPUT ;
    USE SIGNAL ;
    PORT
      LAYER M4 ;
        RECT  161.916 215.712 162 215.736 ;
    END
  END bus_rdata_i[240]
  PIN bus_rdata_i[241]
    DIRECTION INPUT ;
    USE SIGNAL ;
    PORT
      LAYER M4 ;
        RECT  161.916 213.6 162 213.624 ;
    END
  END bus_rdata_i[241]
  PIN bus_rdata_i[242]
    DIRECTION INPUT ;
    USE SIGNAL ;
    PORT
      LAYER M4 ;
        RECT  161.916 214.176 162 214.2 ;
    END
  END bus_rdata_i[242]
  PIN bus_rdata_i[243]
    DIRECTION INPUT ;
    USE SIGNAL ;
    PORT
      LAYER M4 ;
        RECT  161.916 217.824 162 217.848 ;
    END
  END bus_rdata_i[243]
  PIN bus_rdata_i[244]
    DIRECTION INPUT ;
    USE SIGNAL ;
    PORT
      LAYER M4 ;
        RECT  161.916 223.584 162 223.608 ;
    END
  END bus_rdata_i[244]
  PIN bus_rdata_i[245]
    DIRECTION INPUT ;
    USE SIGNAL ;
    PORT
      LAYER M4 ;
        RECT  161.916 213.984 162 214.008 ;
    END
  END bus_rdata_i[245]
  PIN bus_rdata_i[246]
    DIRECTION INPUT ;
    USE SIGNAL ;
    PORT
      LAYER M4 ;
        RECT  161.916 228 162 228.024 ;
    END
  END bus_rdata_i[246]
  PIN bus_rdata_i[247]
    DIRECTION INPUT ;
    USE SIGNAL ;
    PORT
      LAYER M4 ;
        RECT  161.916 213.408 162 213.432 ;
    END
  END bus_rdata_i[247]
  PIN bus_rdata_i[248]
    DIRECTION INPUT ;
    USE SIGNAL ;
    PORT
      LAYER M4 ;
        RECT  0 201.888 0.084 201.912 ;
    END
  END bus_rdata_i[248]
  PIN bus_rdata_i[249]
    DIRECTION INPUT ;
    USE SIGNAL ;
    PORT
      LAYER M4 ;
        RECT  0 201.792 0.084 201.816 ;
    END
  END bus_rdata_i[249]
  PIN bus_rdata_i[24]
    DIRECTION INPUT ;
    USE SIGNAL ;
    PORT
      LAYER M4 ;
        RECT  0 215.04 0.084 215.064 ;
    END
  END bus_rdata_i[24]
  PIN bus_rdata_i[250]
    DIRECTION INPUT ;
    USE SIGNAL ;
    PORT
      LAYER M4 ;
        RECT  0 210.432 0.084 210.456 ;
    END
  END bus_rdata_i[250]
  PIN bus_rdata_i[251]
    DIRECTION INPUT ;
    USE SIGNAL ;
    PORT
      LAYER M4 ;
        RECT  161.916 225.408 162 225.432 ;
    END
  END bus_rdata_i[251]
  PIN bus_rdata_i[252]
    DIRECTION INPUT ;
    USE SIGNAL ;
    PORT
      LAYER M4 ;
        RECT  0 203.808 0.084 203.832 ;
    END
  END bus_rdata_i[252]
  PIN bus_rdata_i[253]
    DIRECTION INPUT ;
    USE SIGNAL ;
    PORT
      LAYER M4 ;
        RECT  161.916 230.496 162 230.52 ;
    END
  END bus_rdata_i[253]
  PIN bus_rdata_i[254]
    DIRECTION INPUT ;
    USE SIGNAL ;
    PORT
      LAYER M4 ;
        RECT  161.916 229.536 162 229.56 ;
    END
  END bus_rdata_i[254]
  PIN bus_rdata_i[255]
    DIRECTION INPUT ;
    USE SIGNAL ;
    PORT
      LAYER M4 ;
        RECT  161.916 227.904 162 227.928 ;
    END
  END bus_rdata_i[255]
  PIN bus_rdata_i[25]
    DIRECTION INPUT ;
    USE SIGNAL ;
    PORT
      LAYER M4 ;
        RECT  0 202.656 0.084 202.68 ;
    END
  END bus_rdata_i[25]
  PIN bus_rdata_i[26]
    DIRECTION INPUT ;
    USE SIGNAL ;
    PORT
      LAYER M4 ;
        RECT  0 212.64 0.084 212.664 ;
    END
  END bus_rdata_i[26]
  PIN bus_rdata_i[27]
    DIRECTION INPUT ;
    USE SIGNAL ;
    PORT
      LAYER M4 ;
        RECT  0 211.2 0.084 211.224 ;
    END
  END bus_rdata_i[27]
  PIN bus_rdata_i[28]
    DIRECTION INPUT ;
    USE SIGNAL ;
    PORT
      LAYER M4 ;
        RECT  0 201.984 0.084 202.008 ;
    END
  END bus_rdata_i[28]
  PIN bus_rdata_i[29]
    DIRECTION INPUT ;
    USE SIGNAL ;
    PORT
      LAYER M4 ;
        RECT  0 200.448 0.084 200.472 ;
    END
  END bus_rdata_i[29]
  PIN bus_rdata_i[2]
    DIRECTION INPUT ;
    USE SIGNAL ;
    PORT
      LAYER M4 ;
        RECT  0 204.288 0.084 204.312 ;
    END
  END bus_rdata_i[2]
  PIN bus_rdata_i[30]
    DIRECTION INPUT ;
    USE SIGNAL ;
    PORT
      LAYER M4 ;
        RECT  0 215.712 0.084 215.736 ;
    END
  END bus_rdata_i[30]
  PIN bus_rdata_i[31]
    DIRECTION INPUT ;
    USE SIGNAL ;
    PORT
      LAYER M4 ;
        RECT  0 202.56 0.084 202.584 ;
    END
  END bus_rdata_i[31]
  PIN bus_rdata_i[32]
    DIRECTION INPUT ;
    USE SIGNAL ;
    PORT
      LAYER M4 ;
        RECT  0 204 0.084 204.024 ;
    END
  END bus_rdata_i[32]
  PIN bus_rdata_i[33]
    DIRECTION INPUT ;
    USE SIGNAL ;
    PORT
      LAYER M4 ;
        RECT  0 209.088 0.084 209.112 ;
    END
  END bus_rdata_i[33]
  PIN bus_rdata_i[34]
    DIRECTION INPUT ;
    USE SIGNAL ;
    PORT
      LAYER M4 ;
        RECT  0 200.16 0.084 200.184 ;
    END
  END bus_rdata_i[34]
  PIN bus_rdata_i[35]
    DIRECTION INPUT ;
    USE SIGNAL ;
    PORT
      LAYER M4 ;
        RECT  0 200.064 0.084 200.088 ;
    END
  END bus_rdata_i[35]
  PIN bus_rdata_i[36]
    DIRECTION INPUT ;
    USE SIGNAL ;
    PORT
      LAYER M4 ;
        RECT  0 215.808 0.084 215.832 ;
    END
  END bus_rdata_i[36]
  PIN bus_rdata_i[37]
    DIRECTION INPUT ;
    USE SIGNAL ;
    PORT
      LAYER M4 ;
        RECT  0 215.232 0.084 215.256 ;
    END
  END bus_rdata_i[37]
  PIN bus_rdata_i[38]
    DIRECTION INPUT ;
    USE SIGNAL ;
    PORT
      LAYER M4 ;
        RECT  0 205.152 0.084 205.176 ;
    END
  END bus_rdata_i[38]
  PIN bus_rdata_i[39]
    DIRECTION INPUT ;
    USE SIGNAL ;
    PORT
      LAYER M4 ;
        RECT  0 214.368 0.084 214.392 ;
    END
  END bus_rdata_i[39]
  PIN bus_rdata_i[3]
    DIRECTION INPUT ;
    USE SIGNAL ;
    PORT
      LAYER M4 ;
        RECT  0 215.136 0.084 215.16 ;
    END
  END bus_rdata_i[3]
  PIN bus_rdata_i[40]
    DIRECTION INPUT ;
    USE SIGNAL ;
    PORT
      LAYER M4 ;
        RECT  0 208.896 0.084 208.92 ;
    END
  END bus_rdata_i[40]
  PIN bus_rdata_i[41]
    DIRECTION INPUT ;
    USE SIGNAL ;
    PORT
      LAYER M4 ;
        RECT  0 213.216 0.084 213.24 ;
    END
  END bus_rdata_i[41]
  PIN bus_rdata_i[42]
    DIRECTION INPUT ;
    USE SIGNAL ;
    PORT
      LAYER M4 ;
        RECT  0 212.832 0.084 212.856 ;
    END
  END bus_rdata_i[42]
  PIN bus_rdata_i[43]
    DIRECTION INPUT ;
    USE SIGNAL ;
    PORT
      LAYER M4 ;
        RECT  0 214.752 0.084 214.776 ;
    END
  END bus_rdata_i[43]
  PIN bus_rdata_i[44]
    DIRECTION INPUT ;
    USE SIGNAL ;
    PORT
      LAYER M4 ;
        RECT  0 214.848 0.084 214.872 ;
    END
  END bus_rdata_i[44]
  PIN bus_rdata_i[45]
    DIRECTION INPUT ;
    USE SIGNAL ;
    PORT
      LAYER M4 ;
        RECT  161.916 222.24 162 222.264 ;
    END
  END bus_rdata_i[45]
  PIN bus_rdata_i[46]
    DIRECTION INPUT ;
    USE SIGNAL ;
    PORT
      LAYER M4 ;
        RECT  0 216.096 0.084 216.12 ;
    END
  END bus_rdata_i[46]
  PIN bus_rdata_i[47]
    DIRECTION INPUT ;
    USE SIGNAL ;
    PORT
      LAYER M4 ;
        RECT  0 215.328 0.084 215.352 ;
    END
  END bus_rdata_i[47]
  PIN bus_rdata_i[48]
    DIRECTION INPUT ;
    USE SIGNAL ;
    PORT
      LAYER M4 ;
        RECT  0 213.888 0.084 213.912 ;
    END
  END bus_rdata_i[48]
  PIN bus_rdata_i[49]
    DIRECTION INPUT ;
    USE SIGNAL ;
    PORT
      LAYER M4 ;
        RECT  0 203.52 0.084 203.544 ;
    END
  END bus_rdata_i[49]
  PIN bus_rdata_i[4]
    DIRECTION INPUT ;
    USE SIGNAL ;
    PORT
      LAYER M4 ;
        RECT  0 201.504 0.084 201.528 ;
    END
  END bus_rdata_i[4]
  PIN bus_rdata_i[50]
    DIRECTION INPUT ;
    USE SIGNAL ;
    PORT
      LAYER M4 ;
        RECT  0 203.424 0.084 203.448 ;
    END
  END bus_rdata_i[50]
  PIN bus_rdata_i[51]
    DIRECTION INPUT ;
    USE SIGNAL ;
    PORT
      LAYER M4 ;
        RECT  0 213.12 0.084 213.144 ;
    END
  END bus_rdata_i[51]
  PIN bus_rdata_i[52]
    DIRECTION INPUT ;
    USE SIGNAL ;
    PORT
      LAYER M4 ;
        RECT  0 212.736 0.084 212.76 ;
    END
  END bus_rdata_i[52]
  PIN bus_rdata_i[53]
    DIRECTION INPUT ;
    USE SIGNAL ;
    PORT
      LAYER M4 ;
        RECT  0 213.024 0.084 213.048 ;
    END
  END bus_rdata_i[53]
  PIN bus_rdata_i[54]
    DIRECTION INPUT ;
    USE SIGNAL ;
    PORT
      LAYER M4 ;
        RECT  0 205.44 0.084 205.464 ;
    END
  END bus_rdata_i[54]
  PIN bus_rdata_i[55]
    DIRECTION INPUT ;
    USE SIGNAL ;
    PORT
      LAYER M4 ;
        RECT  0 206.784 0.084 206.808 ;
    END
  END bus_rdata_i[55]
  PIN bus_rdata_i[56]
    DIRECTION INPUT ;
    USE SIGNAL ;
    PORT
      LAYER M4 ;
        RECT  0 214.272 0.084 214.296 ;
    END
  END bus_rdata_i[56]
  PIN bus_rdata_i[57]
    DIRECTION INPUT ;
    USE SIGNAL ;
    PORT
      LAYER M4 ;
        RECT  0 213.696 0.084 213.72 ;
    END
  END bus_rdata_i[57]
  PIN bus_rdata_i[58]
    DIRECTION INPUT ;
    USE SIGNAL ;
    PORT
      LAYER M4 ;
        RECT  0 209.664 0.084 209.688 ;
    END
  END bus_rdata_i[58]
  PIN bus_rdata_i[59]
    DIRECTION INPUT ;
    USE SIGNAL ;
    PORT
      LAYER M4 ;
        RECT  0 201.696 0.084 201.72 ;
    END
  END bus_rdata_i[59]
  PIN bus_rdata_i[5]
    DIRECTION INPUT ;
    USE SIGNAL ;
    PORT
      LAYER M4 ;
        RECT  0 201.12 0.084 201.144 ;
    END
  END bus_rdata_i[5]
  PIN bus_rdata_i[60]
    DIRECTION INPUT ;
    USE SIGNAL ;
    PORT
      LAYER M4 ;
        RECT  0 201.024 0.084 201.048 ;
    END
  END bus_rdata_i[60]
  PIN bus_rdata_i[61]
    DIRECTION INPUT ;
    USE SIGNAL ;
    PORT
      LAYER M4 ;
        RECT  0 206.304 0.084 206.328 ;
    END
  END bus_rdata_i[61]
  PIN bus_rdata_i[62]
    DIRECTION INPUT ;
    USE SIGNAL ;
    PORT
      LAYER M4 ;
        RECT  0 212.352 0.084 212.376 ;
    END
  END bus_rdata_i[62]
  PIN bus_rdata_i[63]
    DIRECTION INPUT ;
    USE SIGNAL ;
    PORT
      LAYER M4 ;
        RECT  0 211.488 0.084 211.512 ;
    END
  END bus_rdata_i[63]
  PIN bus_rdata_i[64]
    DIRECTION INPUT ;
    USE SIGNAL ;
    PORT
      LAYER M4 ;
        RECT  161.916 225.696 162 225.72 ;
    END
  END bus_rdata_i[64]
  PIN bus_rdata_i[65]
    DIRECTION INPUT ;
    USE SIGNAL ;
    PORT
      LAYER M4 ;
        RECT  161.916 226.752 162 226.776 ;
    END
  END bus_rdata_i[65]
  PIN bus_rdata_i[66]
    DIRECTION INPUT ;
    USE SIGNAL ;
    PORT
      LAYER M4 ;
        RECT  161.916 227.04 162 227.064 ;
    END
  END bus_rdata_i[66]
  PIN bus_rdata_i[67]
    DIRECTION INPUT ;
    USE SIGNAL ;
    PORT
      LAYER M4 ;
        RECT  161.916 215.424 162 215.448 ;
    END
  END bus_rdata_i[67]
  PIN bus_rdata_i[68]
    DIRECTION INPUT ;
    USE SIGNAL ;
    PORT
      LAYER M4 ;
        RECT  161.916 214.752 162 214.776 ;
    END
  END bus_rdata_i[68]
  PIN bus_rdata_i[69]
    DIRECTION INPUT ;
    USE SIGNAL ;
    PORT
      LAYER M4 ;
        RECT  161.916 224.448 162 224.472 ;
    END
  END bus_rdata_i[69]
  PIN bus_rdata_i[6]
    DIRECTION INPUT ;
    USE SIGNAL ;
    PORT
      LAYER M4 ;
        RECT  0 210.336 0.084 210.36 ;
    END
  END bus_rdata_i[6]
  PIN bus_rdata_i[70]
    DIRECTION INPUT ;
    USE SIGNAL ;
    PORT
      LAYER M4 ;
        RECT  161.916 225.888 162 225.912 ;
    END
  END bus_rdata_i[70]
  PIN bus_rdata_i[71]
    DIRECTION INPUT ;
    USE SIGNAL ;
    PORT
      LAYER M4 ;
        RECT  161.916 212.544 162 212.568 ;
    END
  END bus_rdata_i[71]
  PIN bus_rdata_i[72]
    DIRECTION INPUT ;
    USE SIGNAL ;
    PORT
      LAYER M4 ;
        RECT  0 215.904 0.084 215.928 ;
    END
  END bus_rdata_i[72]
  PIN bus_rdata_i[73]
    DIRECTION INPUT ;
    USE SIGNAL ;
    PORT
      LAYER M4 ;
        RECT  161.916 212.352 162 212.376 ;
    END
  END bus_rdata_i[73]
  PIN bus_rdata_i[74]
    DIRECTION INPUT ;
    USE SIGNAL ;
    PORT
      LAYER M4 ;
        RECT  0 216.192 0.084 216.216 ;
    END
  END bus_rdata_i[74]
  PIN bus_rdata_i[75]
    DIRECTION INPUT ;
    USE SIGNAL ;
    PORT
      LAYER M4 ;
        RECT  161.916 212.256 162 212.28 ;
    END
  END bus_rdata_i[75]
  PIN bus_rdata_i[76]
    DIRECTION INPUT ;
    USE SIGNAL ;
    PORT
      LAYER M4 ;
        RECT  0 216.576 0.084 216.6 ;
    END
  END bus_rdata_i[76]
  PIN bus_rdata_i[77]
    DIRECTION INPUT ;
    USE SIGNAL ;
    PORT
      LAYER M4 ;
        RECT  161.916 212.064 162 212.088 ;
    END
  END bus_rdata_i[77]
  PIN bus_rdata_i[78]
    DIRECTION INPUT ;
    USE SIGNAL ;
    PORT
      LAYER M4 ;
        RECT  161.916 211.968 162 211.992 ;
    END
  END bus_rdata_i[78]
  PIN bus_rdata_i[79]
    DIRECTION INPUT ;
    USE SIGNAL ;
    PORT
      LAYER M4 ;
        RECT  161.916 213.312 162 213.336 ;
    END
  END bus_rdata_i[79]
  PIN bus_rdata_i[7]
    DIRECTION INPUT ;
    USE SIGNAL ;
    PORT
      LAYER M4 ;
        RECT  0 202.464 0.084 202.488 ;
    END
  END bus_rdata_i[7]
  PIN bus_rdata_i[80]
    DIRECTION INPUT ;
    USE SIGNAL ;
    PORT
      LAYER M4 ;
        RECT  161.916 212.64 162 212.664 ;
    END
  END bus_rdata_i[80]
  PIN bus_rdata_i[81]
    DIRECTION INPUT ;
    USE SIGNAL ;
    PORT
      LAYER M4 ;
        RECT  161.916 212.16 162 212.184 ;
    END
  END bus_rdata_i[81]
  PIN bus_rdata_i[82]
    DIRECTION INPUT ;
    USE SIGNAL ;
    PORT
      LAYER M4 ;
        RECT  161.916 212.736 162 212.76 ;
    END
  END bus_rdata_i[82]
  PIN bus_rdata_i[83]
    DIRECTION INPUT ;
    USE SIGNAL ;
    PORT
      LAYER M4 ;
        RECT  161.916 216.384 162 216.408 ;
    END
  END bus_rdata_i[83]
  PIN bus_rdata_i[84]
    DIRECTION INPUT ;
    USE SIGNAL ;
    PORT
      LAYER M4 ;
        RECT  0 209.184 0.084 209.208 ;
    END
  END bus_rdata_i[84]
  PIN bus_rdata_i[85]
    DIRECTION INPUT ;
    USE SIGNAL ;
    PORT
      LAYER M4 ;
        RECT  161.916 213.792 162 213.816 ;
    END
  END bus_rdata_i[85]
  PIN bus_rdata_i[86]
    DIRECTION INPUT ;
    USE SIGNAL ;
    PORT
      LAYER M4 ;
        RECT  0 216.384 0.084 216.408 ;
    END
  END bus_rdata_i[86]
  PIN bus_rdata_i[87]
    DIRECTION INPUT ;
    USE SIGNAL ;
    PORT
      LAYER M4 ;
        RECT  161.916 212.832 162 212.856 ;
    END
  END bus_rdata_i[87]
  PIN bus_rdata_i[88]
    DIRECTION INPUT ;
    USE SIGNAL ;
    PORT
      LAYER M4 ;
        RECT  0 216.288 0.084 216.312 ;
    END
  END bus_rdata_i[88]
  PIN bus_rdata_i[89]
    DIRECTION INPUT ;
    USE SIGNAL ;
    PORT
      LAYER M4 ;
        RECT  0 216 0.084 216.024 ;
    END
  END bus_rdata_i[89]
  PIN bus_rdata_i[8]
    DIRECTION INPUT ;
    USE SIGNAL ;
    PORT
      LAYER M4 ;
        RECT  0 204.576 0.084 204.6 ;
    END
  END bus_rdata_i[8]
  PIN bus_rdata_i[90]
    DIRECTION INPUT ;
    USE SIGNAL ;
    PORT
      LAYER M4 ;
        RECT  0 216.48 0.084 216.504 ;
    END
  END bus_rdata_i[90]
  PIN bus_rdata_i[91]
    DIRECTION INPUT ;
    USE SIGNAL ;
    PORT
      LAYER M4 ;
        RECT  0 203.232 0.084 203.256 ;
    END
  END bus_rdata_i[91]
  PIN bus_rdata_i[92]
    DIRECTION INPUT ;
    USE SIGNAL ;
    PORT
      LAYER M4 ;
        RECT  0 214.656 0.084 214.68 ;
    END
  END bus_rdata_i[92]
  PIN bus_rdata_i[93]
    DIRECTION INPUT ;
    USE SIGNAL ;
    PORT
      LAYER M4 ;
        RECT  0 214.56 0.084 214.584 ;
    END
  END bus_rdata_i[93]
  PIN bus_rdata_i[94]
    DIRECTION INPUT ;
    USE SIGNAL ;
    PORT
      LAYER M4 ;
        RECT  0 214.08 0.084 214.104 ;
    END
  END bus_rdata_i[94]
  PIN bus_rdata_i[95]
    DIRECTION INPUT ;
    USE SIGNAL ;
    PORT
      LAYER M4 ;
        RECT  161.916 214.08 162 214.104 ;
    END
  END bus_rdata_i[95]
  PIN bus_rdata_i[96]
    DIRECTION INPUT ;
    USE SIGNAL ;
    PORT
      LAYER M4 ;
        RECT  161.916 223.2 162 223.224 ;
    END
  END bus_rdata_i[96]
  PIN bus_rdata_i[97]
    DIRECTION INPUT ;
    USE SIGNAL ;
    PORT
      LAYER M4 ;
        RECT  161.916 217.536 162 217.56 ;
    END
  END bus_rdata_i[97]
  PIN bus_rdata_i[98]
    DIRECTION INPUT ;
    USE SIGNAL ;
    PORT
      LAYER M4 ;
        RECT  161.916 219.552 162 219.576 ;
    END
  END bus_rdata_i[98]
  PIN bus_rdata_i[99]
    DIRECTION INPUT ;
    USE SIGNAL ;
    PORT
      LAYER M4 ;
        RECT  161.916 227.232 162 227.256 ;
    END
  END bus_rdata_i[99]
  PIN bus_rdata_i[9]
    DIRECTION INPUT ;
    USE SIGNAL ;
    PORT
      LAYER M4 ;
        RECT  161.916 212.448 162 212.472 ;
    END
  END bus_rdata_i[9]
  PIN bus_req_o[0]
    DIRECTION OUTPUT ;
    USE SIGNAL ;
    PORT
      LAYER M4 ;
        RECT  0 225.312 0.084 225.336 ;
    END
  END bus_req_o[0]
  PIN bus_req_o[1]
    DIRECTION OUTPUT ;
    USE SIGNAL ;
    PORT
      LAYER M4 ;
        RECT  161.916 228.384 162 228.408 ;
    END
  END bus_req_o[1]
  PIN bus_wdata_o[0]
    DIRECTION OUTPUT ;
    USE SIGNAL ;
    PORT
      LAYER M4 ;
        RECT  0 229.152 0.084 229.176 ;
    END
  END bus_wdata_o[0]
  PIN bus_wdata_o[100]
    DIRECTION OUTPUT ;
    USE SIGNAL ;
    PORT
      LAYER M4 ;
        RECT  0 227.424 0.084 227.448 ;
    END
  END bus_wdata_o[100]
  PIN bus_wdata_o[101]
    DIRECTION OUTPUT ;
    USE SIGNAL ;
    PORT
      LAYER M4 ;
        RECT  0 233.568 0.084 233.592 ;
    END
  END bus_wdata_o[101]
  PIN bus_wdata_o[102]
    DIRECTION OUTPUT ;
    USE SIGNAL ;
    PORT
      LAYER M4 ;
        RECT  0 234.432 0.084 234.456 ;
    END
  END bus_wdata_o[102]
  PIN bus_wdata_o[103]
    DIRECTION OUTPUT ;
    USE SIGNAL ;
    PORT
      LAYER M5 ;
        RECT  48 274.916 48.024 275 ;
    END
  END bus_wdata_o[103]
  PIN bus_wdata_o[104]
    DIRECTION OUTPUT ;
    USE SIGNAL ;
    PORT
      LAYER M5 ;
        RECT  50.976 274.916 51 275 ;
    END
  END bus_wdata_o[104]
  PIN bus_wdata_o[105]
    DIRECTION OUTPUT ;
    USE SIGNAL ;
    PORT
      LAYER M5 ;
        RECT  50.88 274.916 50.904 275 ;
    END
  END bus_wdata_o[105]
  PIN bus_wdata_o[106]
    DIRECTION OUTPUT ;
    USE SIGNAL ;
    PORT
      LAYER M5 ;
        RECT  52.224 274.916 52.248 275 ;
    END
  END bus_wdata_o[106]
  PIN bus_wdata_o[107]
    DIRECTION OUTPUT ;
    USE SIGNAL ;
    PORT
      LAYER M5 ;
        RECT  54.624 274.916 54.648 275 ;
    END
  END bus_wdata_o[107]
  PIN bus_wdata_o[108]
    DIRECTION OUTPUT ;
    USE SIGNAL ;
    PORT
      LAYER M5 ;
        RECT  53.952 274.916 53.976 275 ;
    END
  END bus_wdata_o[108]
  PIN bus_wdata_o[109]
    DIRECTION OUTPUT ;
    USE SIGNAL ;
    PORT
      LAYER M5 ;
        RECT  54.72 274.916 54.744 275 ;
    END
  END bus_wdata_o[109]
  PIN bus_wdata_o[10]
    DIRECTION OUTPUT ;
    USE SIGNAL ;
    PORT
      LAYER M5 ;
        RECT  51.072 274.916 51.096 275 ;
    END
  END bus_wdata_o[10]
  PIN bus_wdata_o[110]
    DIRECTION OUTPUT ;
    USE SIGNAL ;
    PORT
      LAYER M5 ;
        RECT  62.016 274.916 62.04 275 ;
    END
  END bus_wdata_o[110]
  PIN bus_wdata_o[111]
    DIRECTION OUTPUT ;
    USE SIGNAL ;
    PORT
      LAYER M5 ;
        RECT  61.824 274.916 61.848 275 ;
    END
  END bus_wdata_o[111]
  PIN bus_wdata_o[112]
    DIRECTION OUTPUT ;
    USE SIGNAL ;
    PORT
      LAYER M5 ;
        RECT  60.384 274.916 60.408 275 ;
    END
  END bus_wdata_o[112]
  PIN bus_wdata_o[113]
    DIRECTION OUTPUT ;
    USE SIGNAL ;
    PORT
      LAYER M5 ;
        RECT  61.056 274.916 61.08 275 ;
    END
  END bus_wdata_o[113]
  PIN bus_wdata_o[114]
    DIRECTION OUTPUT ;
    USE SIGNAL ;
    PORT
      LAYER M5 ;
        RECT  55.872 274.916 55.896 275 ;
    END
  END bus_wdata_o[114]
  PIN bus_wdata_o[115]
    DIRECTION OUTPUT ;
    USE SIGNAL ;
    PORT
      LAYER M5 ;
        RECT  52.992 274.916 53.016 275 ;
    END
  END bus_wdata_o[115]
  PIN bus_wdata_o[116]
    DIRECTION OUTPUT ;
    USE SIGNAL ;
    PORT
      LAYER M5 ;
        RECT  60.672 274.916 60.696 275 ;
    END
  END bus_wdata_o[116]
  PIN bus_wdata_o[117]
    DIRECTION OUTPUT ;
    USE SIGNAL ;
    PORT
      LAYER M5 ;
        RECT  59.712 274.916 59.736 275 ;
    END
  END bus_wdata_o[117]
  PIN bus_wdata_o[118]
    DIRECTION OUTPUT ;
    USE SIGNAL ;
    PORT
      LAYER M5 ;
        RECT  56.256 274.916 56.28 275 ;
    END
  END bus_wdata_o[118]
  PIN bus_wdata_o[119]
    DIRECTION OUTPUT ;
    USE SIGNAL ;
    PORT
      LAYER M5 ;
        RECT  58.656 274.916 58.68 275 ;
    END
  END bus_wdata_o[119]
  PIN bus_wdata_o[11]
    DIRECTION OUTPUT ;
    USE SIGNAL ;
    PORT
      LAYER M5 ;
        RECT  61.92 274.916 61.944 275 ;
    END
  END bus_wdata_o[11]
  PIN bus_wdata_o[120]
    DIRECTION OUTPUT ;
    USE SIGNAL ;
    PORT
      LAYER M4 ;
        RECT  0 223.776 0.084 223.8 ;
    END
  END bus_wdata_o[120]
  PIN bus_wdata_o[121]
    DIRECTION OUTPUT ;
    USE SIGNAL ;
    PORT
      LAYER M4 ;
        RECT  0 230.208 0.084 230.232 ;
    END
  END bus_wdata_o[121]
  PIN bus_wdata_o[122]
    DIRECTION OUTPUT ;
    USE SIGNAL ;
    PORT
      LAYER M4 ;
        RECT  0 233.184 0.084 233.208 ;
    END
  END bus_wdata_o[122]
  PIN bus_wdata_o[123]
    DIRECTION OUTPUT ;
    USE SIGNAL ;
    PORT
      LAYER M4 ;
        RECT  0 220.032 0.084 220.056 ;
    END
  END bus_wdata_o[123]
  PIN bus_wdata_o[124]
    DIRECTION OUTPUT ;
    USE SIGNAL ;
    PORT
      LAYER M4 ;
        RECT  0 225.408 0.084 225.432 ;
    END
  END bus_wdata_o[124]
  PIN bus_wdata_o[125]
    DIRECTION OUTPUT ;
    USE SIGNAL ;
    PORT
      LAYER M4 ;
        RECT  0 234.144 0.084 234.168 ;
    END
  END bus_wdata_o[125]
  PIN bus_wdata_o[126]
    DIRECTION OUTPUT ;
    USE SIGNAL ;
    PORT
      LAYER M4 ;
        RECT  0 220.608 0.084 220.632 ;
    END
  END bus_wdata_o[126]
  PIN bus_wdata_o[127]
    DIRECTION OUTPUT ;
    USE SIGNAL ;
    PORT
      LAYER M4 ;
        RECT  0 232.128 0.084 232.152 ;
    END
  END bus_wdata_o[127]
  PIN bus_wdata_o[128]
    DIRECTION OUTPUT ;
    USE SIGNAL ;
    PORT
      LAYER M4 ;
        RECT  0 230.016 0.084 230.04 ;
    END
  END bus_wdata_o[128]
  PIN bus_wdata_o[129]
    DIRECTION OUTPUT ;
    USE SIGNAL ;
    PORT
      LAYER M4 ;
        RECT  0 229.632 0.084 229.656 ;
    END
  END bus_wdata_o[129]
  PIN bus_wdata_o[12]
    DIRECTION OUTPUT ;
    USE SIGNAL ;
    PORT
      LAYER M5 ;
        RECT  52.8 274.916 52.824 275 ;
    END
  END bus_wdata_o[12]
  PIN bus_wdata_o[130]
    DIRECTION OUTPUT ;
    USE SIGNAL ;
    PORT
      LAYER M4 ;
        RECT  0 220.896 0.084 220.92 ;
    END
  END bus_wdata_o[130]
  PIN bus_wdata_o[131]
    DIRECTION OUTPUT ;
    USE SIGNAL ;
    PORT
      LAYER M4 ;
        RECT  0 216.672 0.084 216.696 ;
    END
  END bus_wdata_o[131]
  PIN bus_wdata_o[132]
    DIRECTION OUTPUT ;
    USE SIGNAL ;
    PORT
      LAYER M4 ;
        RECT  0 226.464 0.084 226.488 ;
    END
  END bus_wdata_o[132]
  PIN bus_wdata_o[133]
    DIRECTION OUTPUT ;
    USE SIGNAL ;
    PORT
      LAYER M5 ;
        RECT  49.92 274.916 49.944 275 ;
    END
  END bus_wdata_o[133]
  PIN bus_wdata_o[134]
    DIRECTION OUTPUT ;
    USE SIGNAL ;
    PORT
      LAYER M4 ;
        RECT  0 220.416 0.084 220.44 ;
    END
  END bus_wdata_o[134]
  PIN bus_wdata_o[135]
    DIRECTION OUTPUT ;
    USE SIGNAL ;
    PORT
      LAYER M5 ;
        RECT  50.688 274.916 50.712 275 ;
    END
  END bus_wdata_o[135]
  PIN bus_wdata_o[136]
    DIRECTION OUTPUT ;
    USE SIGNAL ;
    PORT
      LAYER M5 ;
        RECT  50.304 274.916 50.328 275 ;
    END
  END bus_wdata_o[136]
  PIN bus_wdata_o[137]
    DIRECTION OUTPUT ;
    USE SIGNAL ;
    PORT
      LAYER M5 ;
        RECT  51.648 274.916 51.672 275 ;
    END
  END bus_wdata_o[137]
  PIN bus_wdata_o[138]
    DIRECTION OUTPUT ;
    USE SIGNAL ;
    PORT
      LAYER M5 ;
        RECT  48.768 274.916 48.792 275 ;
    END
  END bus_wdata_o[138]
  PIN bus_wdata_o[139]
    DIRECTION OUTPUT ;
    USE SIGNAL ;
    PORT
      LAYER M5 ;
        RECT  60.768 274.916 60.792 275 ;
    END
  END bus_wdata_o[139]
  PIN bus_wdata_o[13]
    DIRECTION OUTPUT ;
    USE SIGNAL ;
    PORT
      LAYER M5 ;
        RECT  48.192 274.916 48.216 275 ;
    END
  END bus_wdata_o[13]
  PIN bus_wdata_o[140]
    DIRECTION OUTPUT ;
    USE SIGNAL ;
    PORT
      LAYER M5 ;
        RECT  49.344 274.916 49.368 275 ;
    END
  END bus_wdata_o[140]
  PIN bus_wdata_o[141]
    DIRECTION OUTPUT ;
    USE SIGNAL ;
    PORT
      LAYER M5 ;
        RECT  61.248 274.916 61.272 275 ;
    END
  END bus_wdata_o[141]
  PIN bus_wdata_o[142]
    DIRECTION OUTPUT ;
    USE SIGNAL ;
    PORT
      LAYER M5 ;
        RECT  60.864 274.916 60.888 275 ;
    END
  END bus_wdata_o[142]
  PIN bus_wdata_o[143]
    DIRECTION OUTPUT ;
    USE SIGNAL ;
    PORT
      LAYER M5 ;
        RECT  58.464 274.916 58.488 275 ;
    END
  END bus_wdata_o[143]
  PIN bus_wdata_o[144]
    DIRECTION OUTPUT ;
    USE SIGNAL ;
    PORT
      LAYER M5 ;
        RECT  58.752 274.916 58.776 275 ;
    END
  END bus_wdata_o[144]
  PIN bus_wdata_o[145]
    DIRECTION OUTPUT ;
    USE SIGNAL ;
    PORT
      LAYER M5 ;
        RECT  55.584 274.916 55.608 275 ;
    END
  END bus_wdata_o[145]
  PIN bus_wdata_o[146]
    DIRECTION OUTPUT ;
    USE SIGNAL ;
    PORT
      LAYER M5 ;
        RECT  58.56 274.916 58.584 275 ;
    END
  END bus_wdata_o[146]
  PIN bus_wdata_o[147]
    DIRECTION OUTPUT ;
    USE SIGNAL ;
    PORT
      LAYER M5 ;
        RECT  51.168 274.916 51.192 275 ;
    END
  END bus_wdata_o[147]
  PIN bus_wdata_o[148]
    DIRECTION OUTPUT ;
    USE SIGNAL ;
    PORT
      LAYER M5 ;
        RECT  60.096 274.916 60.12 275 ;
    END
  END bus_wdata_o[148]
  PIN bus_wdata_o[149]
    DIRECTION OUTPUT ;
    USE SIGNAL ;
    PORT
      LAYER M5 ;
        RECT  58.368 274.916 58.392 275 ;
    END
  END bus_wdata_o[149]
  PIN bus_wdata_o[14]
    DIRECTION OUTPUT ;
    USE SIGNAL ;
    PORT
      LAYER M5 ;
        RECT  55.008 274.916 55.032 275 ;
    END
  END bus_wdata_o[14]
  PIN bus_wdata_o[150]
    DIRECTION OUTPUT ;
    USE SIGNAL ;
    PORT
      LAYER M5 ;
        RECT  58.08 274.916 58.104 275 ;
    END
  END bus_wdata_o[150]
  PIN bus_wdata_o[151]
    DIRECTION OUTPUT ;
    USE SIGNAL ;
    PORT
      LAYER M5 ;
        RECT  57.984 274.916 58.008 275 ;
    END
  END bus_wdata_o[151]
  PIN bus_wdata_o[152]
    DIRECTION OUTPUT ;
    USE SIGNAL ;
    PORT
      LAYER M4 ;
        RECT  0 221.376 0.084 221.4 ;
    END
  END bus_wdata_o[152]
  PIN bus_wdata_o[153]
    DIRECTION OUTPUT ;
    USE SIGNAL ;
    PORT
      LAYER M4 ;
        RECT  0 227.232 0.084 227.256 ;
    END
  END bus_wdata_o[153]
  PIN bus_wdata_o[154]
    DIRECTION OUTPUT ;
    USE SIGNAL ;
    PORT
      LAYER M4 ;
        RECT  0 228 0.084 228.024 ;
    END
  END bus_wdata_o[154]
  PIN bus_wdata_o[155]
    DIRECTION OUTPUT ;
    USE SIGNAL ;
    PORT
      LAYER M4 ;
        RECT  0 223.392 0.084 223.416 ;
    END
  END bus_wdata_o[155]
  PIN bus_wdata_o[156]
    DIRECTION OUTPUT ;
    USE SIGNAL ;
    PORT
      LAYER M4 ;
        RECT  0 224.64 0.084 224.664 ;
    END
  END bus_wdata_o[156]
  PIN bus_wdata_o[157]
    DIRECTION OUTPUT ;
    USE SIGNAL ;
    PORT
      LAYER M4 ;
        RECT  0 229.44 0.084 229.464 ;
    END
  END bus_wdata_o[157]
  PIN bus_wdata_o[158]
    DIRECTION OUTPUT ;
    USE SIGNAL ;
    PORT
      LAYER M4 ;
        RECT  0 225.696 0.084 225.72 ;
    END
  END bus_wdata_o[158]
  PIN bus_wdata_o[159]
    DIRECTION OUTPUT ;
    USE SIGNAL ;
    PORT
      LAYER M4 ;
        RECT  0 224.256 0.084 224.28 ;
    END
  END bus_wdata_o[159]
  PIN bus_wdata_o[15]
    DIRECTION OUTPUT ;
    USE SIGNAL ;
    PORT
      LAYER M5 ;
        RECT  55.776 274.916 55.8 275 ;
    END
  END bus_wdata_o[15]
  PIN bus_wdata_o[160]
    DIRECTION OUTPUT ;
    USE SIGNAL ;
    PORT
      LAYER M4 ;
        RECT  0 220.704 0.084 220.728 ;
    END
  END bus_wdata_o[160]
  PIN bus_wdata_o[161]
    DIRECTION OUTPUT ;
    USE SIGNAL ;
    PORT
      LAYER M4 ;
        RECT  0 221.28 0.084 221.304 ;
    END
  END bus_wdata_o[161]
  PIN bus_wdata_o[162]
    DIRECTION OUTPUT ;
    USE SIGNAL ;
    PORT
      LAYER M4 ;
        RECT  0 230.976 0.084 231 ;
    END
  END bus_wdata_o[162]
  PIN bus_wdata_o[163]
    DIRECTION OUTPUT ;
    USE SIGNAL ;
    PORT
      LAYER M4 ;
        RECT  0 220.512 0.084 220.536 ;
    END
  END bus_wdata_o[163]
  PIN bus_wdata_o[164]
    DIRECTION OUTPUT ;
    USE SIGNAL ;
    PORT
      LAYER M4 ;
        RECT  0 223.584 0.084 223.608 ;
    END
  END bus_wdata_o[164]
  PIN bus_wdata_o[165]
    DIRECTION OUTPUT ;
    USE SIGNAL ;
    PORT
      LAYER M4 ;
        RECT  0 218.784 0.084 218.808 ;
    END
  END bus_wdata_o[165]
  PIN bus_wdata_o[166]
    DIRECTION OUTPUT ;
    USE SIGNAL ;
    PORT
      LAYER M4 ;
        RECT  0 219.744 0.084 219.768 ;
    END
  END bus_wdata_o[166]
  PIN bus_wdata_o[167]
    DIRECTION OUTPUT ;
    USE SIGNAL ;
    PORT
      LAYER M5 ;
        RECT  52.032 274.916 52.056 275 ;
    END
  END bus_wdata_o[167]
  PIN bus_wdata_o[168]
    DIRECTION OUTPUT ;
    USE SIGNAL ;
    PORT
      LAYER M5 ;
        RECT  52.896 274.916 52.92 275 ;
    END
  END bus_wdata_o[168]
  PIN bus_wdata_o[169]
    DIRECTION OUTPUT ;
    USE SIGNAL ;
    PORT
      LAYER M5 ;
        RECT  49.152 274.916 49.176 275 ;
    END
  END bus_wdata_o[169]
  PIN bus_wdata_o[16]
    DIRECTION OUTPUT ;
    USE SIGNAL ;
    PORT
      LAYER M5 ;
        RECT  55.488 274.916 55.512 275 ;
    END
  END bus_wdata_o[16]
  PIN bus_wdata_o[170]
    DIRECTION OUTPUT ;
    USE SIGNAL ;
    PORT
      LAYER M5 ;
        RECT  53.568 274.916 53.592 275 ;
    END
  END bus_wdata_o[170]
  PIN bus_wdata_o[171]
    DIRECTION OUTPUT ;
    USE SIGNAL ;
    PORT
      LAYER M5 ;
        RECT  55.392 274.916 55.416 275 ;
    END
  END bus_wdata_o[171]
  PIN bus_wdata_o[172]
    DIRECTION OUTPUT ;
    USE SIGNAL ;
    PORT
      LAYER M5 ;
        RECT  53.088 274.916 53.112 275 ;
    END
  END bus_wdata_o[172]
  PIN bus_wdata_o[173]
    DIRECTION OUTPUT ;
    USE SIGNAL ;
    PORT
      LAYER M5 ;
        RECT  54.912 274.916 54.936 275 ;
    END
  END bus_wdata_o[173]
  PIN bus_wdata_o[174]
    DIRECTION OUTPUT ;
    USE SIGNAL ;
    PORT
      LAYER M5 ;
        RECT  55.296 274.916 55.32 275 ;
    END
  END bus_wdata_o[174]
  PIN bus_wdata_o[175]
    DIRECTION OUTPUT ;
    USE SIGNAL ;
    PORT
      LAYER M5 ;
        RECT  56.544 274.916 56.568 275 ;
    END
  END bus_wdata_o[175]
  PIN bus_wdata_o[176]
    DIRECTION OUTPUT ;
    USE SIGNAL ;
    PORT
      LAYER M5 ;
        RECT  58.848 274.916 58.872 275 ;
    END
  END bus_wdata_o[176]
  PIN bus_wdata_o[177]
    DIRECTION OUTPUT ;
    USE SIGNAL ;
    PORT
      LAYER M5 ;
        RECT  55.968 274.916 55.992 275 ;
    END
  END bus_wdata_o[177]
  PIN bus_wdata_o[178]
    DIRECTION OUTPUT ;
    USE SIGNAL ;
    PORT
      LAYER M5 ;
        RECT  58.272 274.916 58.296 275 ;
    END
  END bus_wdata_o[178]
  PIN bus_wdata_o[179]
    DIRECTION OUTPUT ;
    USE SIGNAL ;
    PORT
      LAYER M5 ;
        RECT  51.36 274.916 51.384 275 ;
    END
  END bus_wdata_o[179]
  PIN bus_wdata_o[17]
    DIRECTION OUTPUT ;
    USE SIGNAL ;
    PORT
      LAYER M5 ;
        RECT  61.344 274.916 61.368 275 ;
    END
  END bus_wdata_o[17]
  PIN bus_wdata_o[180]
    DIRECTION OUTPUT ;
    USE SIGNAL ;
    PORT
      LAYER M5 ;
        RECT  59.808 274.916 59.832 275 ;
    END
  END bus_wdata_o[180]
  PIN bus_wdata_o[181]
    DIRECTION OUTPUT ;
    USE SIGNAL ;
    PORT
      LAYER M5 ;
        RECT  56.448 274.916 56.472 275 ;
    END
  END bus_wdata_o[181]
  PIN bus_wdata_o[182]
    DIRECTION OUTPUT ;
    USE SIGNAL ;
    PORT
      LAYER M5 ;
        RECT  56.352 274.916 56.376 275 ;
    END
  END bus_wdata_o[182]
  PIN bus_wdata_o[183]
    DIRECTION OUTPUT ;
    USE SIGNAL ;
    PORT
      LAYER M5 ;
        RECT  57.792 274.916 57.816 275 ;
    END
  END bus_wdata_o[183]
  PIN bus_wdata_o[184]
    DIRECTION OUTPUT ;
    USE SIGNAL ;
    PORT
      LAYER M5 ;
        RECT  49.728 274.916 49.752 275 ;
    END
  END bus_wdata_o[184]
  PIN bus_wdata_o[185]
    DIRECTION OUTPUT ;
    USE SIGNAL ;
    PORT
      LAYER M5 ;
        RECT  51.552 274.916 51.576 275 ;
    END
  END bus_wdata_o[185]
  PIN bus_wdata_o[186]
    DIRECTION OUTPUT ;
    USE SIGNAL ;
    PORT
      LAYER M5 ;
        RECT  51.84 274.916 51.864 275 ;
    END
  END bus_wdata_o[186]
  PIN bus_wdata_o[187]
    DIRECTION OUTPUT ;
    USE SIGNAL ;
    PORT
      LAYER M4 ;
        RECT  0 224.832 0.084 224.856 ;
    END
  END bus_wdata_o[187]
  PIN bus_wdata_o[188]
    DIRECTION OUTPUT ;
    USE SIGNAL ;
    PORT
      LAYER M4 ;
        RECT  0 227.52 0.084 227.544 ;
    END
  END bus_wdata_o[188]
  PIN bus_wdata_o[189]
    DIRECTION OUTPUT ;
    USE SIGNAL ;
    PORT
      LAYER M4 ;
        RECT  0 226.752 0.084 226.776 ;
    END
  END bus_wdata_o[189]
  PIN bus_wdata_o[18]
    DIRECTION OUTPUT ;
    USE SIGNAL ;
    PORT
      LAYER M5 ;
        RECT  59.904 274.916 59.928 275 ;
    END
  END bus_wdata_o[18]
  PIN bus_wdata_o[190]
    DIRECTION OUTPUT ;
    USE SIGNAL ;
    PORT
      LAYER M4 ;
        RECT  0 228.384 0.084 228.408 ;
    END
  END bus_wdata_o[190]
  PIN bus_wdata_o[191]
    DIRECTION OUTPUT ;
    USE SIGNAL ;
    PORT
      LAYER M4 ;
        RECT  0 222.816 0.084 222.84 ;
    END
  END bus_wdata_o[191]
  PIN bus_wdata_o[192]
    DIRECTION OUTPUT ;
    USE SIGNAL ;
    PORT
      LAYER M4 ;
        RECT  0 222.048 0.084 222.072 ;
    END
  END bus_wdata_o[192]
  PIN bus_wdata_o[193]
    DIRECTION OUTPUT ;
    USE SIGNAL ;
    PORT
      LAYER M4 ;
        RECT  0 217.248 0.084 217.272 ;
    END
  END bus_wdata_o[193]
  PIN bus_wdata_o[194]
    DIRECTION OUTPUT ;
    USE SIGNAL ;
    PORT
      LAYER M4 ;
        RECT  0 229.248 0.084 229.272 ;
    END
  END bus_wdata_o[194]
  PIN bus_wdata_o[195]
    DIRECTION OUTPUT ;
    USE SIGNAL ;
    PORT
      LAYER M4 ;
        RECT  0 219.264 0.084 219.288 ;
    END
  END bus_wdata_o[195]
  PIN bus_wdata_o[196]
    DIRECTION OUTPUT ;
    USE SIGNAL ;
    PORT
      LAYER M4 ;
        RECT  0 227.328 0.084 227.352 ;
    END
  END bus_wdata_o[196]
  PIN bus_wdata_o[197]
    DIRECTION OUTPUT ;
    USE SIGNAL ;
    PORT
      LAYER M4 ;
        RECT  0 223.2 0.084 223.224 ;
    END
  END bus_wdata_o[197]
  PIN bus_wdata_o[198]
    DIRECTION OUTPUT ;
    USE SIGNAL ;
    PORT
      LAYER M4 ;
        RECT  0 226.08 0.084 226.104 ;
    END
  END bus_wdata_o[198]
  PIN bus_wdata_o[199]
    DIRECTION OUTPUT ;
    USE SIGNAL ;
    PORT
      LAYER M5 ;
        RECT  53.184 274.916 53.208 275 ;
    END
  END bus_wdata_o[199]
  PIN bus_wdata_o[19]
    DIRECTION OUTPUT ;
    USE SIGNAL ;
    PORT
      LAYER M5 ;
        RECT  54.528 274.916 54.552 275 ;
    END
  END bus_wdata_o[19]
  PIN bus_wdata_o[1]
    DIRECTION OUTPUT ;
    USE SIGNAL ;
    PORT
      LAYER M4 ;
        RECT  0 228.672 0.084 228.696 ;
    END
  END bus_wdata_o[1]
  PIN bus_wdata_o[200]
    DIRECTION OUTPUT ;
    USE SIGNAL ;
    PORT
      LAYER M5 ;
        RECT  48.864 274.916 48.888 275 ;
    END
  END bus_wdata_o[200]
  PIN bus_wdata_o[201]
    DIRECTION OUTPUT ;
    USE SIGNAL ;
    PORT
      LAYER M5 ;
        RECT  49.056 274.916 49.08 275 ;
    END
  END bus_wdata_o[201]
  PIN bus_wdata_o[202]
    DIRECTION OUTPUT ;
    USE SIGNAL ;
    PORT
      LAYER M5 ;
        RECT  53.856 274.916 53.88 275 ;
    END
  END bus_wdata_o[202]
  PIN bus_wdata_o[203]
    DIRECTION OUTPUT ;
    USE SIGNAL ;
    PORT
      LAYER M5 ;
        RECT  61.44 274.916 61.464 275 ;
    END
  END bus_wdata_o[203]
  PIN bus_wdata_o[204]
    DIRECTION OUTPUT ;
    USE SIGNAL ;
    PORT
      LAYER M5 ;
        RECT  48.384 274.916 48.408 275 ;
    END
  END bus_wdata_o[204]
  PIN bus_wdata_o[205]
    DIRECTION OUTPUT ;
    USE SIGNAL ;
    PORT
      LAYER M5 ;
        RECT  61.632 274.916 61.656 275 ;
    END
  END bus_wdata_o[205]
  PIN bus_wdata_o[206]
    DIRECTION OUTPUT ;
    USE SIGNAL ;
    PORT
      LAYER M5 ;
        RECT  61.728 274.916 61.752 275 ;
    END
  END bus_wdata_o[206]
  PIN bus_wdata_o[207]
    DIRECTION OUTPUT ;
    USE SIGNAL ;
    PORT
      LAYER M5 ;
        RECT  57.696 274.916 57.72 275 ;
    END
  END bus_wdata_o[207]
  PIN bus_wdata_o[208]
    DIRECTION OUTPUT ;
    USE SIGNAL ;
    PORT
      LAYER M5 ;
        RECT  57.408 274.916 57.432 275 ;
    END
  END bus_wdata_o[208]
  PIN bus_wdata_o[209]
    DIRECTION OUTPUT ;
    USE SIGNAL ;
    PORT
      LAYER M5 ;
        RECT  60 274.916 60.024 275 ;
    END
  END bus_wdata_o[209]
  PIN bus_wdata_o[20]
    DIRECTION OUTPUT ;
    USE SIGNAL ;
    PORT
      LAYER M5 ;
        RECT  55.2 274.916 55.224 275 ;
    END
  END bus_wdata_o[20]
  PIN bus_wdata_o[210]
    DIRECTION OUTPUT ;
    USE SIGNAL ;
    PORT
      LAYER M5 ;
        RECT  56.64 274.916 56.664 275 ;
    END
  END bus_wdata_o[210]
  PIN bus_wdata_o[211]
    DIRECTION OUTPUT ;
    USE SIGNAL ;
    PORT
      LAYER M5 ;
        RECT  53.472 274.916 53.496 275 ;
    END
  END bus_wdata_o[211]
  PIN bus_wdata_o[212]
    DIRECTION OUTPUT ;
    USE SIGNAL ;
    PORT
      LAYER M5 ;
        RECT  60.576 274.916 60.6 275 ;
    END
  END bus_wdata_o[212]
  PIN bus_wdata_o[213]
    DIRECTION OUTPUT ;
    USE SIGNAL ;
    PORT
      LAYER M5 ;
        RECT  57.216 274.916 57.24 275 ;
    END
  END bus_wdata_o[213]
  PIN bus_wdata_o[214]
    DIRECTION OUTPUT ;
    USE SIGNAL ;
    PORT
      LAYER M5 ;
        RECT  56.832 274.916 56.856 275 ;
    END
  END bus_wdata_o[214]
  PIN bus_wdata_o[215]
    DIRECTION OUTPUT ;
    USE SIGNAL ;
    PORT
      LAYER M5 ;
        RECT  56.928 274.916 56.952 275 ;
    END
  END bus_wdata_o[215]
  PIN bus_wdata_o[216]
    DIRECTION OUTPUT ;
    USE SIGNAL ;
    PORT
      LAYER M5 ;
        RECT  51.936 274.916 51.96 275 ;
    END
  END bus_wdata_o[216]
  PIN bus_wdata_o[217]
    DIRECTION OUTPUT ;
    USE SIGNAL ;
    PORT
      LAYER M4 ;
        RECT  0 221.184 0.084 221.208 ;
    END
  END bus_wdata_o[217]
  PIN bus_wdata_o[218]
    DIRECTION OUTPUT ;
    USE SIGNAL ;
    PORT
      LAYER M4 ;
        RECT  0 222.72 0.084 222.744 ;
    END
  END bus_wdata_o[218]
  PIN bus_wdata_o[219]
    DIRECTION OUTPUT ;
    USE SIGNAL ;
    PORT
      LAYER M4 ;
        RECT  0 227.808 0.084 227.832 ;
    END
  END bus_wdata_o[219]
  PIN bus_wdata_o[21]
    DIRECTION OUTPUT ;
    USE SIGNAL ;
    PORT
      LAYER M5 ;
        RECT  57.888 274.916 57.912 275 ;
    END
  END bus_wdata_o[21]
  PIN bus_wdata_o[220]
    DIRECTION OUTPUT ;
    USE SIGNAL ;
    PORT
      LAYER M4 ;
        RECT  0 225.792 0.084 225.816 ;
    END
  END bus_wdata_o[220]
  PIN bus_wdata_o[221]
    DIRECTION OUTPUT ;
    USE SIGNAL ;
    PORT
      LAYER M4 ;
        RECT  0 224.928 0.084 224.952 ;
    END
  END bus_wdata_o[221]
  PIN bus_wdata_o[222]
    DIRECTION OUTPUT ;
    USE SIGNAL ;
    PORT
      LAYER M4 ;
        RECT  0 228.288 0.084 228.312 ;
    END
  END bus_wdata_o[222]
  PIN bus_wdata_o[223]
    DIRECTION OUTPUT ;
    USE SIGNAL ;
    PORT
      LAYER M4 ;
        RECT  0 225.216 0.084 225.24 ;
    END
  END bus_wdata_o[223]
  PIN bus_wdata_o[224]
    DIRECTION OUTPUT ;
    USE SIGNAL ;
    PORT
      LAYER M4 ;
        RECT  0 227.136 0.084 227.16 ;
    END
  END bus_wdata_o[224]
  PIN bus_wdata_o[225]
    DIRECTION OUTPUT ;
    USE SIGNAL ;
    PORT
      LAYER M4 ;
        RECT  0 224.16 0.084 224.184 ;
    END
  END bus_wdata_o[225]
  PIN bus_wdata_o[226]
    DIRECTION OUTPUT ;
    USE SIGNAL ;
    PORT
      LAYER M4 ;
        RECT  0 222.624 0.084 222.648 ;
    END
  END bus_wdata_o[226]
  PIN bus_wdata_o[227]
    DIRECTION OUTPUT ;
    USE SIGNAL ;
    PORT
      LAYER M4 ;
        RECT  0 228.864 0.084 228.888 ;
    END
  END bus_wdata_o[227]
  PIN bus_wdata_o[228]
    DIRECTION OUTPUT ;
    USE SIGNAL ;
    PORT
      LAYER M4 ;
        RECT  0 226.848 0.084 226.872 ;
    END
  END bus_wdata_o[228]
  PIN bus_wdata_o[229]
    DIRECTION OUTPUT ;
    USE SIGNAL ;
    PORT
      LAYER M5 ;
        RECT  48.672 274.916 48.696 275 ;
    END
  END bus_wdata_o[229]
  PIN bus_wdata_o[22]
    DIRECTION OUTPUT ;
    USE SIGNAL ;
    PORT
      LAYER M5 ;
        RECT  56.16 274.916 56.184 275 ;
    END
  END bus_wdata_o[22]
  PIN bus_wdata_o[230]
    DIRECTION OUTPUT ;
    USE SIGNAL ;
    PORT
      LAYER M4 ;
        RECT  0 218.976 0.084 219 ;
    END
  END bus_wdata_o[230]
  PIN bus_wdata_o[231]
    DIRECTION OUTPUT ;
    USE SIGNAL ;
    PORT
      LAYER M5 ;
        RECT  50.208 274.916 50.232 275 ;
    END
  END bus_wdata_o[231]
  PIN bus_wdata_o[232]
    DIRECTION OUTPUT ;
    USE SIGNAL ;
    PORT
      LAYER M5 ;
        RECT  50.496 274.916 50.52 275 ;
    END
  END bus_wdata_o[232]
  PIN bus_wdata_o[233]
    DIRECTION OUTPUT ;
    USE SIGNAL ;
    PORT
      LAYER M5 ;
        RECT  50.4 274.916 50.424 275 ;
    END
  END bus_wdata_o[233]
  PIN bus_wdata_o[234]
    DIRECTION OUTPUT ;
    USE SIGNAL ;
    PORT
      LAYER M5 ;
        RECT  52.128 274.916 52.152 275 ;
    END
  END bus_wdata_o[234]
  PIN bus_wdata_o[235]
    DIRECTION OUTPUT ;
    USE SIGNAL ;
    PORT
      LAYER M5 ;
        RECT  52.704 274.916 52.728 275 ;
    END
  END bus_wdata_o[235]
  PIN bus_wdata_o[236]
    DIRECTION OUTPUT ;
    USE SIGNAL ;
    PORT
      LAYER M5 ;
        RECT  48.48 274.916 48.504 275 ;
    END
  END bus_wdata_o[236]
  PIN bus_wdata_o[237]
    DIRECTION OUTPUT ;
    USE SIGNAL ;
    PORT
      LAYER M5 ;
        RECT  54.336 274.916 54.36 275 ;
    END
  END bus_wdata_o[237]
  PIN bus_wdata_o[238]
    DIRECTION OUTPUT ;
    USE SIGNAL ;
    PORT
      LAYER M5 ;
        RECT  54.816 274.916 54.84 275 ;
    END
  END bus_wdata_o[238]
  PIN bus_wdata_o[239]
    DIRECTION OUTPUT ;
    USE SIGNAL ;
    PORT
      LAYER M5 ;
        RECT  57.312 274.916 57.336 275 ;
    END
  END bus_wdata_o[239]
  PIN bus_wdata_o[23]
    DIRECTION OUTPUT ;
    USE SIGNAL ;
    PORT
      LAYER M5 ;
        RECT  56.736 274.916 56.76 275 ;
    END
  END bus_wdata_o[23]
  PIN bus_wdata_o[240]
    DIRECTION OUTPUT ;
    USE SIGNAL ;
    PORT
      LAYER M5 ;
        RECT  57.6 274.916 57.624 275 ;
    END
  END bus_wdata_o[240]
  PIN bus_wdata_o[241]
    DIRECTION OUTPUT ;
    USE SIGNAL ;
    PORT
      LAYER M5 ;
        RECT  60.96 274.916 60.984 275 ;
    END
  END bus_wdata_o[241]
  PIN bus_wdata_o[242]
    DIRECTION OUTPUT ;
    USE SIGNAL ;
    PORT
      LAYER M5 ;
        RECT  57.504 274.916 57.528 275 ;
    END
  END bus_wdata_o[242]
  PIN bus_wdata_o[243]
    DIRECTION OUTPUT ;
    USE SIGNAL ;
    PORT
      LAYER M5 ;
        RECT  52.608 274.916 52.632 275 ;
    END
  END bus_wdata_o[243]
  PIN bus_wdata_o[244]
    DIRECTION OUTPUT ;
    USE SIGNAL ;
    PORT
      LAYER M5 ;
        RECT  60.288 274.916 60.312 275 ;
    END
  END bus_wdata_o[244]
  PIN bus_wdata_o[245]
    DIRECTION OUTPUT ;
    USE SIGNAL ;
    PORT
      LAYER M5 ;
        RECT  57.024 274.916 57.048 275 ;
    END
  END bus_wdata_o[245]
  PIN bus_wdata_o[246]
    DIRECTION OUTPUT ;
    USE SIGNAL ;
    PORT
      LAYER M5 ;
        RECT  57.12 274.916 57.144 275 ;
    END
  END bus_wdata_o[246]
  PIN bus_wdata_o[247]
    DIRECTION OUTPUT ;
    USE SIGNAL ;
    PORT
      LAYER M5 ;
        RECT  49.824 274.916 49.848 275 ;
    END
  END bus_wdata_o[247]
  PIN bus_wdata_o[248]
    DIRECTION OUTPUT ;
    USE SIGNAL ;
    PORT
      LAYER M4 ;
        RECT  0 222.528 0.084 222.552 ;
    END
  END bus_wdata_o[248]
  PIN bus_wdata_o[249]
    DIRECTION OUTPUT ;
    USE SIGNAL ;
    PORT
      LAYER M4 ;
        RECT  0 220.992 0.084 221.016 ;
    END
  END bus_wdata_o[249]
  PIN bus_wdata_o[24]
    DIRECTION OUTPUT ;
    USE SIGNAL ;
    PORT
      LAYER M5 ;
        RECT  51.264 274.916 51.288 275 ;
    END
  END bus_wdata_o[24]
  PIN bus_wdata_o[250]
    DIRECTION OUTPUT ;
    USE SIGNAL ;
    PORT
      LAYER M4 ;
        RECT  0 220.8 0.084 220.824 ;
    END
  END bus_wdata_o[250]
  PIN bus_wdata_o[251]
    DIRECTION OUTPUT ;
    USE SIGNAL ;
    PORT
      LAYER M4 ;
        RECT  0 227.04 0.084 227.064 ;
    END
  END bus_wdata_o[251]
  PIN bus_wdata_o[252]
    DIRECTION OUTPUT ;
    USE SIGNAL ;
    PORT
      LAYER M4 ;
        RECT  0 219.072 0.084 219.096 ;
    END
  END bus_wdata_o[252]
  PIN bus_wdata_o[253]
    DIRECTION OUTPUT ;
    USE SIGNAL ;
    PORT
      LAYER M4 ;
        RECT  0 224.544 0.084 224.568 ;
    END
  END bus_wdata_o[253]
  PIN bus_wdata_o[254]
    DIRECTION OUTPUT ;
    USE SIGNAL ;
    PORT
      LAYER M4 ;
        RECT  0 222.432 0.084 222.456 ;
    END
  END bus_wdata_o[254]
  PIN bus_wdata_o[255]
    DIRECTION OUTPUT ;
    USE SIGNAL ;
    PORT
      LAYER M4 ;
        RECT  0 219.552 0.084 219.576 ;
    END
  END bus_wdata_o[255]
  PIN bus_wdata_o[256]
    DIRECTION OUTPUT ;
    USE SIGNAL ;
    PORT
      LAYER M4 ;
        RECT  161.916 226.464 162 226.488 ;
    END
  END bus_wdata_o[256]
  PIN bus_wdata_o[257]
    DIRECTION OUTPUT ;
    USE SIGNAL ;
    PORT
      LAYER M4 ;
        RECT  161.916 230.592 162 230.616 ;
    END
  END bus_wdata_o[257]
  PIN bus_wdata_o[258]
    DIRECTION OUTPUT ;
    USE SIGNAL ;
    PORT
      LAYER M4 ;
        RECT  161.916 215.904 162 215.928 ;
    END
  END bus_wdata_o[258]
  PIN bus_wdata_o[259]
    DIRECTION OUTPUT ;
    USE SIGNAL ;
    PORT
      LAYER M4 ;
        RECT  161.916 222.912 162 222.936 ;
    END
  END bus_wdata_o[259]
  PIN bus_wdata_o[25]
    DIRECTION OUTPUT ;
    USE SIGNAL ;
    PORT
      LAYER M5 ;
        RECT  50.112 274.916 50.136 275 ;
    END
  END bus_wdata_o[25]
  PIN bus_wdata_o[260]
    DIRECTION OUTPUT ;
    USE SIGNAL ;
    PORT
      LAYER M4 ;
        RECT  161.916 220.704 162 220.728 ;
    END
  END bus_wdata_o[260]
  PIN bus_wdata_o[261]
    DIRECTION OUTPUT ;
    USE SIGNAL ;
    PORT
      LAYER M4 ;
        RECT  161.916 229.632 162 229.656 ;
    END
  END bus_wdata_o[261]
  PIN bus_wdata_o[262]
    DIRECTION OUTPUT ;
    USE SIGNAL ;
    PORT
      LAYER M4 ;
        RECT  161.916 221.472 162 221.496 ;
    END
  END bus_wdata_o[262]
  PIN bus_wdata_o[263]
    DIRECTION OUTPUT ;
    USE SIGNAL ;
    PORT
      LAYER M4 ;
        RECT  161.916 223.296 162 223.32 ;
    END
  END bus_wdata_o[263]
  PIN bus_wdata_o[264]
    DIRECTION OUTPUT ;
    USE SIGNAL ;
    PORT
      LAYER M4 ;
        RECT  161.916 229.056 162 229.08 ;
    END
  END bus_wdata_o[264]
  PIN bus_wdata_o[265]
    DIRECTION OUTPUT ;
    USE SIGNAL ;
    PORT
      LAYER M4 ;
        RECT  161.916 216.864 162 216.888 ;
    END
  END bus_wdata_o[265]
  PIN bus_wdata_o[266]
    DIRECTION OUTPUT ;
    USE SIGNAL ;
    PORT
      LAYER M4 ;
        RECT  161.916 214.944 162 214.968 ;
    END
  END bus_wdata_o[266]
  PIN bus_wdata_o[267]
    DIRECTION OUTPUT ;
    USE SIGNAL ;
    PORT
      LAYER M4 ;
        RECT  161.916 215.136 162 215.16 ;
    END
  END bus_wdata_o[267]
  PIN bus_wdata_o[268]
    DIRECTION OUTPUT ;
    USE SIGNAL ;
    PORT
      LAYER M4 ;
        RECT  161.916 218.304 162 218.328 ;
    END
  END bus_wdata_o[268]
  PIN bus_wdata_o[269]
    DIRECTION OUTPUT ;
    USE SIGNAL ;
    PORT
      LAYER M4 ;
        RECT  161.916 222.528 162 222.552 ;
    END
  END bus_wdata_o[269]
  PIN bus_wdata_o[26]
    DIRECTION OUTPUT ;
    USE SIGNAL ;
    PORT
      LAYER M5 ;
        RECT  50.016 274.916 50.04 275 ;
    END
  END bus_wdata_o[26]
  PIN bus_wdata_o[270]
    DIRECTION OUTPUT ;
    USE SIGNAL ;
    PORT
      LAYER M4 ;
        RECT  161.916 227.616 162 227.64 ;
    END
  END bus_wdata_o[270]
  PIN bus_wdata_o[271]
    DIRECTION OUTPUT ;
    USE SIGNAL ;
    PORT
      LAYER M4 ;
        RECT  161.916 223.776 162 223.8 ;
    END
  END bus_wdata_o[271]
  PIN bus_wdata_o[272]
    DIRECTION OUTPUT ;
    USE SIGNAL ;
    PORT
      LAYER M4 ;
        RECT  161.916 214.56 162 214.584 ;
    END
  END bus_wdata_o[272]
  PIN bus_wdata_o[273]
    DIRECTION OUTPUT ;
    USE SIGNAL ;
    PORT
      LAYER M4 ;
        RECT  161.916 230.784 162 230.808 ;
    END
  END bus_wdata_o[273]
  PIN bus_wdata_o[274]
    DIRECTION OUTPUT ;
    USE SIGNAL ;
    PORT
      LAYER M4 ;
        RECT  161.916 219.648 162 219.672 ;
    END
  END bus_wdata_o[274]
  PIN bus_wdata_o[275]
    DIRECTION OUTPUT ;
    USE SIGNAL ;
    PORT
      LAYER M4 ;
        RECT  161.916 221.664 162 221.688 ;
    END
  END bus_wdata_o[275]
  PIN bus_wdata_o[276]
    DIRECTION OUTPUT ;
    USE SIGNAL ;
    PORT
      LAYER M4 ;
        RECT  161.916 225.6 162 225.624 ;
    END
  END bus_wdata_o[276]
  PIN bus_wdata_o[277]
    DIRECTION OUTPUT ;
    USE SIGNAL ;
    PORT
      LAYER M4 ;
        RECT  161.916 227.808 162 227.832 ;
    END
  END bus_wdata_o[277]
  PIN bus_wdata_o[278]
    DIRECTION OUTPUT ;
    USE SIGNAL ;
    PORT
      LAYER M4 ;
        RECT  161.916 217.92 162 217.944 ;
    END
  END bus_wdata_o[278]
  PIN bus_wdata_o[279]
    DIRECTION OUTPUT ;
    USE SIGNAL ;
    PORT
      LAYER M4 ;
        RECT  161.916 220.992 162 221.016 ;
    END
  END bus_wdata_o[279]
  PIN bus_wdata_o[27]
    DIRECTION OUTPUT ;
    USE SIGNAL ;
    PORT
      LAYER M4 ;
        RECT  0 224.352 0.084 224.376 ;
    END
  END bus_wdata_o[27]
  PIN bus_wdata_o[280]
    DIRECTION OUTPUT ;
    USE SIGNAL ;
    PORT
      LAYER M4 ;
        RECT  161.916 215.04 162 215.064 ;
    END
  END bus_wdata_o[280]
  PIN bus_wdata_o[281]
    DIRECTION OUTPUT ;
    USE SIGNAL ;
    PORT
      LAYER M4 ;
        RECT  161.916 223.104 162 223.128 ;
    END
  END bus_wdata_o[281]
  PIN bus_wdata_o[282]
    DIRECTION OUTPUT ;
    USE SIGNAL ;
    PORT
      LAYER M4 ;
        RECT  161.916 230.976 162 231 ;
    END
  END bus_wdata_o[282]
  PIN bus_wdata_o[283]
    DIRECTION OUTPUT ;
    USE SIGNAL ;
    PORT
      LAYER M4 ;
        RECT  161.916 219.072 162 219.096 ;
    END
  END bus_wdata_o[283]
  PIN bus_wdata_o[284]
    DIRECTION OUTPUT ;
    USE SIGNAL ;
    PORT
      LAYER M4 ;
        RECT  161.916 231.072 162 231.096 ;
    END
  END bus_wdata_o[284]
  PIN bus_wdata_o[285]
    DIRECTION OUTPUT ;
    USE SIGNAL ;
    PORT
      LAYER M4 ;
        RECT  161.916 214.464 162 214.488 ;
    END
  END bus_wdata_o[285]
  PIN bus_wdata_o[286]
    DIRECTION OUTPUT ;
    USE SIGNAL ;
    PORT
      LAYER M4 ;
        RECT  161.916 227.52 162 227.544 ;
    END
  END bus_wdata_o[286]
  PIN bus_wdata_o[287]
    DIRECTION OUTPUT ;
    USE SIGNAL ;
    PORT
      LAYER M4 ;
        RECT  161.916 220.512 162 220.536 ;
    END
  END bus_wdata_o[287]
  PIN bus_wdata_o[288]
    DIRECTION OUTPUT ;
    USE SIGNAL ;
    PORT
      LAYER M4 ;
        RECT  161.916 230.688 162 230.712 ;
    END
  END bus_wdata_o[288]
  PIN bus_wdata_o[289]
    DIRECTION OUTPUT ;
    USE SIGNAL ;
    PORT
      LAYER M4 ;
        RECT  161.916 219.456 162 219.48 ;
    END
  END bus_wdata_o[289]
  PIN bus_wdata_o[28]
    DIRECTION OUTPUT ;
    USE SIGNAL ;
    PORT
      LAYER M4 ;
        RECT  0 233.856 0.084 233.88 ;
    END
  END bus_wdata_o[28]
  PIN bus_wdata_o[290]
    DIRECTION OUTPUT ;
    USE SIGNAL ;
    PORT
      LAYER M4 ;
        RECT  161.916 222.624 162 222.648 ;
    END
  END bus_wdata_o[290]
  PIN bus_wdata_o[291]
    DIRECTION OUTPUT ;
    USE SIGNAL ;
    PORT
      LAYER M4 ;
        RECT  161.916 227.328 162 227.352 ;
    END
  END bus_wdata_o[291]
  PIN bus_wdata_o[292]
    DIRECTION OUTPUT ;
    USE SIGNAL ;
    PORT
      LAYER M4 ;
        RECT  161.916 217.44 162 217.464 ;
    END
  END bus_wdata_o[292]
  PIN bus_wdata_o[293]
    DIRECTION OUTPUT ;
    USE SIGNAL ;
    PORT
      LAYER M4 ;
        RECT  161.916 226.272 162 226.296 ;
    END
  END bus_wdata_o[293]
  PIN bus_wdata_o[294]
    DIRECTION OUTPUT ;
    USE SIGNAL ;
    PORT
      LAYER M4 ;
        RECT  161.916 218.784 162 218.808 ;
    END
  END bus_wdata_o[294]
  PIN bus_wdata_o[295]
    DIRECTION OUTPUT ;
    USE SIGNAL ;
    PORT
      LAYER M4 ;
        RECT  161.916 229.728 162 229.752 ;
    END
  END bus_wdata_o[295]
  PIN bus_wdata_o[296]
    DIRECTION OUTPUT ;
    USE SIGNAL ;
    PORT
      LAYER M4 ;
        RECT  161.916 228.192 162 228.216 ;
    END
  END bus_wdata_o[296]
  PIN bus_wdata_o[297]
    DIRECTION OUTPUT ;
    USE SIGNAL ;
    PORT
      LAYER M4 ;
        RECT  161.916 222.72 162 222.744 ;
    END
  END bus_wdata_o[297]
  PIN bus_wdata_o[298]
    DIRECTION OUTPUT ;
    USE SIGNAL ;
    PORT
      LAYER M4 ;
        RECT  161.916 230.4 162 230.424 ;
    END
  END bus_wdata_o[298]
  PIN bus_wdata_o[299]
    DIRECTION OUTPUT ;
    USE SIGNAL ;
    PORT
      LAYER M4 ;
        RECT  161.916 228.768 162 228.792 ;
    END
  END bus_wdata_o[299]
  PIN bus_wdata_o[29]
    DIRECTION OUTPUT ;
    USE SIGNAL ;
    PORT
      LAYER M4 ;
        RECT  0 223.296 0.084 223.32 ;
    END
  END bus_wdata_o[29]
  PIN bus_wdata_o[2]
    DIRECTION OUTPUT ;
    USE SIGNAL ;
    PORT
      LAYER M4 ;
        RECT  0 224.064 0.084 224.088 ;
    END
  END bus_wdata_o[2]
  PIN bus_wdata_o[300]
    DIRECTION OUTPUT ;
    USE SIGNAL ;
    PORT
      LAYER M4 ;
        RECT  161.916 221.088 162 221.112 ;
    END
  END bus_wdata_o[300]
  PIN bus_wdata_o[301]
    DIRECTION OUTPUT ;
    USE SIGNAL ;
    PORT
      LAYER M4 ;
        RECT  161.916 222.336 162 222.36 ;
    END
  END bus_wdata_o[301]
  PIN bus_wdata_o[302]
    DIRECTION OUTPUT ;
    USE SIGNAL ;
    PORT
      LAYER M4 ;
        RECT  161.916 215.232 162 215.256 ;
    END
  END bus_wdata_o[302]
  PIN bus_wdata_o[303]
    DIRECTION OUTPUT ;
    USE SIGNAL ;
    PORT
      LAYER M4 ;
        RECT  161.916 228.288 162 228.312 ;
    END
  END bus_wdata_o[303]
  PIN bus_wdata_o[304]
    DIRECTION OUTPUT ;
    USE SIGNAL ;
    PORT
      LAYER M4 ;
        RECT  161.916 230.304 162 230.328 ;
    END
  END bus_wdata_o[304]
  PIN bus_wdata_o[305]
    DIRECTION OUTPUT ;
    USE SIGNAL ;
    PORT
      LAYER M4 ;
        RECT  161.916 226.368 162 226.392 ;
    END
  END bus_wdata_o[305]
  PIN bus_wdata_o[306]
    DIRECTION OUTPUT ;
    USE SIGNAL ;
    PORT
      LAYER M4 ;
        RECT  161.916 230.208 162 230.232 ;
    END
  END bus_wdata_o[306]
  PIN bus_wdata_o[307]
    DIRECTION OUTPUT ;
    USE SIGNAL ;
    PORT
      LAYER M4 ;
        RECT  161.916 229.152 162 229.176 ;
    END
  END bus_wdata_o[307]
  PIN bus_wdata_o[308]
    DIRECTION OUTPUT ;
    USE SIGNAL ;
    PORT
      LAYER M4 ;
        RECT  161.916 215.328 162 215.352 ;
    END
  END bus_wdata_o[308]
  PIN bus_wdata_o[309]
    DIRECTION OUTPUT ;
    USE SIGNAL ;
    PORT
      LAYER M4 ;
        RECT  161.916 221.856 162 221.88 ;
    END
  END bus_wdata_o[309]
  PIN bus_wdata_o[30]
    DIRECTION OUTPUT ;
    USE SIGNAL ;
    PORT
      LAYER M4 ;
        RECT  0 234.336 0.084 234.36 ;
    END
  END bus_wdata_o[30]
  PIN bus_wdata_o[310]
    DIRECTION OUTPUT ;
    USE SIGNAL ;
    PORT
      LAYER M4 ;
        RECT  161.916 219.936 162 219.96 ;
    END
  END bus_wdata_o[310]
  PIN bus_wdata_o[311]
    DIRECTION OUTPUT ;
    USE SIGNAL ;
    PORT
      LAYER M4 ;
        RECT  161.916 228.96 162 228.984 ;
    END
  END bus_wdata_o[311]
  PIN bus_wdata_o[312]
    DIRECTION OUTPUT ;
    USE SIGNAL ;
    PORT
      LAYER M4 ;
        RECT  161.916 224.736 162 224.76 ;
    END
  END bus_wdata_o[312]
  PIN bus_wdata_o[313]
    DIRECTION OUTPUT ;
    USE SIGNAL ;
    PORT
      LAYER M4 ;
        RECT  161.916 221.76 162 221.784 ;
    END
  END bus_wdata_o[313]
  PIN bus_wdata_o[314]
    DIRECTION OUTPUT ;
    USE SIGNAL ;
    PORT
      LAYER M4 ;
        RECT  161.916 217.248 162 217.272 ;
    END
  END bus_wdata_o[314]
  PIN bus_wdata_o[315]
    DIRECTION OUTPUT ;
    USE SIGNAL ;
    PORT
      LAYER M4 ;
        RECT  161.916 222.432 162 222.456 ;
    END
  END bus_wdata_o[315]
  PIN bus_wdata_o[316]
    DIRECTION OUTPUT ;
    USE SIGNAL ;
    PORT
      LAYER M4 ;
        RECT  161.916 223.008 162 223.032 ;
    END
  END bus_wdata_o[316]
  PIN bus_wdata_o[317]
    DIRECTION OUTPUT ;
    USE SIGNAL ;
    PORT
      LAYER M4 ;
        RECT  161.916 217.152 162 217.176 ;
    END
  END bus_wdata_o[317]
  PIN bus_wdata_o[318]
    DIRECTION OUTPUT ;
    USE SIGNAL ;
    PORT
      LAYER M4 ;
        RECT  161.916 216.096 162 216.12 ;
    END
  END bus_wdata_o[318]
  PIN bus_wdata_o[319]
    DIRECTION OUTPUT ;
    USE SIGNAL ;
    PORT
      LAYER M4 ;
        RECT  161.916 228.48 162 228.504 ;
    END
  END bus_wdata_o[319]
  PIN bus_wdata_o[31]
    DIRECTION OUTPUT ;
    USE SIGNAL ;
    PORT
      LAYER M4 ;
        RECT  0 233.472 0.084 233.496 ;
    END
  END bus_wdata_o[31]
  PIN bus_wdata_o[320]
    DIRECTION OUTPUT ;
    USE SIGNAL ;
    PORT
      LAYER M4 ;
        RECT  161.916 224.544 162 224.568 ;
    END
  END bus_wdata_o[320]
  PIN bus_wdata_o[321]
    DIRECTION OUTPUT ;
    USE SIGNAL ;
    PORT
      LAYER M4 ;
        RECT  161.916 221.28 162 221.304 ;
    END
  END bus_wdata_o[321]
  PIN bus_wdata_o[322]
    DIRECTION OUTPUT ;
    USE SIGNAL ;
    PORT
      LAYER M4 ;
        RECT  161.916 213.888 162 213.912 ;
    END
  END bus_wdata_o[322]
  PIN bus_wdata_o[323]
    DIRECTION OUTPUT ;
    USE SIGNAL ;
    PORT
      LAYER M4 ;
        RECT  161.916 220.416 162 220.44 ;
    END
  END bus_wdata_o[323]
  PIN bus_wdata_o[324]
    DIRECTION OUTPUT ;
    USE SIGNAL ;
    PORT
      LAYER M4 ;
        RECT  161.916 223.488 162 223.512 ;
    END
  END bus_wdata_o[324]
  PIN bus_wdata_o[325]
    DIRECTION OUTPUT ;
    USE SIGNAL ;
    PORT
      LAYER M4 ;
        RECT  161.916 213.504 162 213.528 ;
    END
  END bus_wdata_o[325]
  PIN bus_wdata_o[326]
    DIRECTION OUTPUT ;
    USE SIGNAL ;
    PORT
      LAYER M4 ;
        RECT  161.916 224.928 162 224.952 ;
    END
  END bus_wdata_o[326]
  PIN bus_wdata_o[327]
    DIRECTION OUTPUT ;
    USE SIGNAL ;
    PORT
      LAYER M4 ;
        RECT  161.916 223.968 162 223.992 ;
    END
  END bus_wdata_o[327]
  PIN bus_wdata_o[328]
    DIRECTION OUTPUT ;
    USE SIGNAL ;
    PORT
      LAYER M4 ;
        RECT  161.916 215.52 162 215.544 ;
    END
  END bus_wdata_o[328]
  PIN bus_wdata_o[329]
    DIRECTION OUTPUT ;
    USE SIGNAL ;
    PORT
      LAYER M4 ;
        RECT  161.916 216.576 162 216.6 ;
    END
  END bus_wdata_o[329]
  PIN bus_wdata_o[32]
    DIRECTION OUTPUT ;
    USE SIGNAL ;
    PORT
      LAYER M4 ;
        RECT  0 234.72 0.084 234.744 ;
    END
  END bus_wdata_o[32]
  PIN bus_wdata_o[330]
    DIRECTION OUTPUT ;
    USE SIGNAL ;
    PORT
      LAYER M4 ;
        RECT  161.916 221.184 162 221.208 ;
    END
  END bus_wdata_o[330]
  PIN bus_wdata_o[331]
    DIRECTION OUTPUT ;
    USE SIGNAL ;
    PORT
      LAYER M4 ;
        RECT  161.916 228.096 162 228.12 ;
    END
  END bus_wdata_o[331]
  PIN bus_wdata_o[332]
    DIRECTION OUTPUT ;
    USE SIGNAL ;
    PORT
      LAYER M4 ;
        RECT  161.916 216.288 162 216.312 ;
    END
  END bus_wdata_o[332]
  PIN bus_wdata_o[333]
    DIRECTION OUTPUT ;
    USE SIGNAL ;
    PORT
      LAYER M4 ;
        RECT  161.916 214.848 162 214.872 ;
    END
  END bus_wdata_o[333]
  PIN bus_wdata_o[334]
    DIRECTION OUTPUT ;
    USE SIGNAL ;
    PORT
      LAYER M4 ;
        RECT  161.916 213.696 162 213.72 ;
    END
  END bus_wdata_o[334]
  PIN bus_wdata_o[335]
    DIRECTION OUTPUT ;
    USE SIGNAL ;
    PORT
      LAYER M4 ;
        RECT  161.916 216.48 162 216.504 ;
    END
  END bus_wdata_o[335]
  PIN bus_wdata_o[336]
    DIRECTION OUTPUT ;
    USE SIGNAL ;
    PORT
      LAYER M4 ;
        RECT  161.916 230.016 162 230.04 ;
    END
  END bus_wdata_o[336]
  PIN bus_wdata_o[337]
    DIRECTION OUTPUT ;
    USE SIGNAL ;
    PORT
      LAYER M4 ;
        RECT  161.916 223.872 162 223.896 ;
    END
  END bus_wdata_o[337]
  PIN bus_wdata_o[338]
    DIRECTION OUTPUT ;
    USE SIGNAL ;
    PORT
      LAYER M4 ;
        RECT  161.916 229.344 162 229.368 ;
    END
  END bus_wdata_o[338]
  PIN bus_wdata_o[339]
    DIRECTION OUTPUT ;
    USE SIGNAL ;
    PORT
      LAYER M4 ;
        RECT  161.916 227.424 162 227.448 ;
    END
  END bus_wdata_o[339]
  PIN bus_wdata_o[33]
    DIRECTION OUTPUT ;
    USE SIGNAL ;
    PORT
      LAYER M4 ;
        RECT  0 232.8 0.084 232.824 ;
    END
  END bus_wdata_o[33]
  PIN bus_wdata_o[340]
    DIRECTION OUTPUT ;
    USE SIGNAL ;
    PORT
      LAYER M4 ;
        RECT  161.916 221.952 162 221.976 ;
    END
  END bus_wdata_o[340]
  PIN bus_wdata_o[341]
    DIRECTION OUTPUT ;
    USE SIGNAL ;
    PORT
      LAYER M4 ;
        RECT  161.916 216.192 162 216.216 ;
    END
  END bus_wdata_o[341]
  PIN bus_wdata_o[342]
    DIRECTION OUTPUT ;
    USE SIGNAL ;
    PORT
      LAYER M4 ;
        RECT  161.916 224.16 162 224.184 ;
    END
  END bus_wdata_o[342]
  PIN bus_wdata_o[343]
    DIRECTION OUTPUT ;
    USE SIGNAL ;
    PORT
      LAYER M4 ;
        RECT  161.916 225.792 162 225.816 ;
    END
  END bus_wdata_o[343]
  PIN bus_wdata_o[344]
    DIRECTION OUTPUT ;
    USE SIGNAL ;
    PORT
      LAYER M4 ;
        RECT  161.916 220.8 162 220.824 ;
    END
  END bus_wdata_o[344]
  PIN bus_wdata_o[345]
    DIRECTION OUTPUT ;
    USE SIGNAL ;
    PORT
      LAYER M4 ;
        RECT  161.916 223.68 162 223.704 ;
    END
  END bus_wdata_o[345]
  PIN bus_wdata_o[346]
    DIRECTION OUTPUT ;
    USE SIGNAL ;
    PORT
      LAYER M4 ;
        RECT  161.916 224.352 162 224.376 ;
    END
  END bus_wdata_o[346]
  PIN bus_wdata_o[347]
    DIRECTION OUTPUT ;
    USE SIGNAL ;
    PORT
      LAYER M4 ;
        RECT  161.916 224.64 162 224.664 ;
    END
  END bus_wdata_o[347]
  PIN bus_wdata_o[348]
    DIRECTION OUTPUT ;
    USE SIGNAL ;
    PORT
      LAYER M4 ;
        RECT  161.916 226.176 162 226.2 ;
    END
  END bus_wdata_o[348]
  PIN bus_wdata_o[349]
    DIRECTION OUTPUT ;
    USE SIGNAL ;
    PORT
      LAYER M4 ;
        RECT  161.916 225.12 162 225.144 ;
    END
  END bus_wdata_o[349]
  PIN bus_wdata_o[34]
    DIRECTION OUTPUT ;
    USE SIGNAL ;
    PORT
      LAYER M4 ;
        RECT  0 234.624 0.084 234.648 ;
    END
  END bus_wdata_o[34]
  PIN bus_wdata_o[350]
    DIRECTION OUTPUT ;
    USE SIGNAL ;
    PORT
      LAYER M4 ;
        RECT  161.916 229.248 162 229.272 ;
    END
  END bus_wdata_o[350]
  PIN bus_wdata_o[351]
    DIRECTION OUTPUT ;
    USE SIGNAL ;
    PORT
      LAYER M4 ;
        RECT  161.916 214.272 162 214.296 ;
    END
  END bus_wdata_o[351]
  PIN bus_wdata_o[352]
    DIRECTION OUTPUT ;
    USE SIGNAL ;
    PORT
      LAYER M4 ;
        RECT  161.916 228.672 162 228.696 ;
    END
  END bus_wdata_o[352]
  PIN bus_wdata_o[353]
    DIRECTION OUTPUT ;
    USE SIGNAL ;
    PORT
      LAYER M4 ;
        RECT  161.916 229.44 162 229.464 ;
    END
  END bus_wdata_o[353]
  PIN bus_wdata_o[354]
    DIRECTION OUTPUT ;
    USE SIGNAL ;
    PORT
      LAYER M4 ;
        RECT  161.916 229.824 162 229.848 ;
    END
  END bus_wdata_o[354]
  PIN bus_wdata_o[355]
    DIRECTION OUTPUT ;
    USE SIGNAL ;
    PORT
      LAYER M4 ;
        RECT  161.916 225.984 162 226.008 ;
    END
  END bus_wdata_o[355]
  PIN bus_wdata_o[356]
    DIRECTION OUTPUT ;
    USE SIGNAL ;
    PORT
      LAYER M4 ;
        RECT  161.916 226.08 162 226.104 ;
    END
  END bus_wdata_o[356]
  PIN bus_wdata_o[357]
    DIRECTION OUTPUT ;
    USE SIGNAL ;
    PORT
      LAYER M4 ;
        RECT  161.916 230.112 162 230.136 ;
    END
  END bus_wdata_o[357]
  PIN bus_wdata_o[358]
    DIRECTION OUTPUT ;
    USE SIGNAL ;
    PORT
      LAYER M4 ;
        RECT  161.916 225.312 162 225.336 ;
    END
  END bus_wdata_o[358]
  PIN bus_wdata_o[359]
    DIRECTION OUTPUT ;
    USE SIGNAL ;
    PORT
      LAYER M4 ;
        RECT  161.916 218.88 162 218.904 ;
    END
  END bus_wdata_o[359]
  PIN bus_wdata_o[35]
    DIRECTION OUTPUT ;
    USE SIGNAL ;
    PORT
      LAYER M4 ;
        RECT  0 228.48 0.084 228.504 ;
    END
  END bus_wdata_o[35]
  PIN bus_wdata_o[360]
    DIRECTION OUTPUT ;
    USE SIGNAL ;
    PORT
      LAYER M4 ;
        RECT  161.916 219.84 162 219.864 ;
    END
  END bus_wdata_o[360]
  PIN bus_wdata_o[361]
    DIRECTION OUTPUT ;
    USE SIGNAL ;
    PORT
      LAYER M4 ;
        RECT  161.916 226.848 162 226.872 ;
    END
  END bus_wdata_o[361]
  PIN bus_wdata_o[362]
    DIRECTION OUTPUT ;
    USE SIGNAL ;
    PORT
      LAYER M4 ;
        RECT  161.916 221.376 162 221.4 ;
    END
  END bus_wdata_o[362]
  PIN bus_wdata_o[363]
    DIRECTION OUTPUT ;
    USE SIGNAL ;
    PORT
      LAYER M5 ;
        RECT  111.744 274.916 111.768 275 ;
    END
  END bus_wdata_o[363]
  PIN bus_wdata_o[364]
    DIRECTION OUTPUT ;
    USE SIGNAL ;
    PORT
      LAYER M5 ;
        RECT  112.512 274.916 112.536 275 ;
    END
  END bus_wdata_o[364]
  PIN bus_wdata_o[365]
    DIRECTION OUTPUT ;
    USE SIGNAL ;
    PORT
      LAYER M5 ;
        RECT  109.056 274.916 109.08 275 ;
    END
  END bus_wdata_o[365]
  PIN bus_wdata_o[366]
    DIRECTION OUTPUT ;
    USE SIGNAL ;
    PORT
      LAYER M5 ;
        RECT  110.688 274.916 110.712 275 ;
    END
  END bus_wdata_o[366]
  PIN bus_wdata_o[367]
    DIRECTION OUTPUT ;
    USE SIGNAL ;
    PORT
      LAYER M5 ;
        RECT  113.184 274.916 113.208 275 ;
    END
  END bus_wdata_o[367]
  PIN bus_wdata_o[368]
    DIRECTION OUTPUT ;
    USE SIGNAL ;
    PORT
      LAYER M5 ;
        RECT  112.32 274.916 112.344 275 ;
    END
  END bus_wdata_o[368]
  PIN bus_wdata_o[369]
    DIRECTION OUTPUT ;
    USE SIGNAL ;
    PORT
      LAYER M5 ;
        RECT  114.144 274.916 114.168 275 ;
    END
  END bus_wdata_o[369]
  PIN bus_wdata_o[36]
    DIRECTION OUTPUT ;
    USE SIGNAL ;
    PORT
      LAYER M4 ;
        RECT  0 233.376 0.084 233.4 ;
    END
  END bus_wdata_o[36]
  PIN bus_wdata_o[370]
    DIRECTION OUTPUT ;
    USE SIGNAL ;
    PORT
      LAYER M5 ;
        RECT  110.592 274.916 110.616 275 ;
    END
  END bus_wdata_o[370]
  PIN bus_wdata_o[371]
    DIRECTION OUTPUT ;
    USE SIGNAL ;
    PORT
      LAYER M5 ;
        RECT  106.848 274.916 106.872 275 ;
    END
  END bus_wdata_o[371]
  PIN bus_wdata_o[372]
    DIRECTION OUTPUT ;
    USE SIGNAL ;
    PORT
      LAYER M5 ;
        RECT  114.816 274.916 114.84 275 ;
    END
  END bus_wdata_o[372]
  PIN bus_wdata_o[373]
    DIRECTION OUTPUT ;
    USE SIGNAL ;
    PORT
      LAYER M5 ;
        RECT  110.208 274.916 110.232 275 ;
    END
  END bus_wdata_o[373]
  PIN bus_wdata_o[374]
    DIRECTION OUTPUT ;
    USE SIGNAL ;
    PORT
      LAYER M5 ;
        RECT  113.472 274.916 113.496 275 ;
    END
  END bus_wdata_o[374]
  PIN bus_wdata_o[375]
    DIRECTION OUTPUT ;
    USE SIGNAL ;
    PORT
      LAYER M5 ;
        RECT  113.376 274.916 113.4 275 ;
    END
  END bus_wdata_o[375]
  PIN bus_wdata_o[376]
    DIRECTION OUTPUT ;
    USE SIGNAL ;
    PORT
      LAYER M5 ;
        RECT  112.128 274.916 112.152 275 ;
    END
  END bus_wdata_o[376]
  PIN bus_wdata_o[377]
    DIRECTION OUTPUT ;
    USE SIGNAL ;
    PORT
      LAYER M5 ;
        RECT  115.296 274.916 115.32 275 ;
    END
  END bus_wdata_o[377]
  PIN bus_wdata_o[378]
    DIRECTION OUTPUT ;
    USE SIGNAL ;
    PORT
      LAYER M5 ;
        RECT  111.168 274.916 111.192 275 ;
    END
  END bus_wdata_o[378]
  PIN bus_wdata_o[379]
    DIRECTION OUTPUT ;
    USE SIGNAL ;
    PORT
      LAYER M5 ;
        RECT  115.872 274.916 115.896 275 ;
    END
  END bus_wdata_o[379]
  PIN bus_wdata_o[37]
    DIRECTION OUTPUT ;
    USE SIGNAL ;
    PORT
      LAYER M4 ;
        RECT  0 235.584 0.084 235.608 ;
    END
  END bus_wdata_o[37]
  PIN bus_wdata_o[380]
    DIRECTION OUTPUT ;
    USE SIGNAL ;
    PORT
      LAYER M5 ;
        RECT  115.008 274.916 115.032 275 ;
    END
  END bus_wdata_o[380]
  PIN bus_wdata_o[381]
    DIRECTION OUTPUT ;
    USE SIGNAL ;
    PORT
      LAYER M5 ;
        RECT  111.264 274.916 111.288 275 ;
    END
  END bus_wdata_o[381]
  PIN bus_wdata_o[382]
    DIRECTION OUTPUT ;
    USE SIGNAL ;
    PORT
      LAYER M5 ;
        RECT  107.328 274.916 107.352 275 ;
    END
  END bus_wdata_o[382]
  PIN bus_wdata_o[383]
    DIRECTION OUTPUT ;
    USE SIGNAL ;
    PORT
      LAYER M5 ;
        RECT  111.936 274.916 111.96 275 ;
    END
  END bus_wdata_o[383]
  PIN bus_wdata_o[384]
    DIRECTION OUTPUT ;
    USE SIGNAL ;
    PORT
      LAYER M5 ;
        RECT  114.24 274.916 114.264 275 ;
    END
  END bus_wdata_o[384]
  PIN bus_wdata_o[385]
    DIRECTION OUTPUT ;
    USE SIGNAL ;
    PORT
      LAYER M5 ;
        RECT  113.28 274.916 113.304 275 ;
    END
  END bus_wdata_o[385]
  PIN bus_wdata_o[386]
    DIRECTION OUTPUT ;
    USE SIGNAL ;
    PORT
      LAYER M5 ;
        RECT  111.072 274.916 111.096 275 ;
    END
  END bus_wdata_o[386]
  PIN bus_wdata_o[387]
    DIRECTION OUTPUT ;
    USE SIGNAL ;
    PORT
      LAYER M5 ;
        RECT  114.624 274.916 114.648 275 ;
    END
  END bus_wdata_o[387]
  PIN bus_wdata_o[388]
    DIRECTION OUTPUT ;
    USE SIGNAL ;
    PORT
      LAYER M5 ;
        RECT  109.152 274.916 109.176 275 ;
    END
  END bus_wdata_o[388]
  PIN bus_wdata_o[389]
    DIRECTION OUTPUT ;
    USE SIGNAL ;
    PORT
      LAYER M5 ;
        RECT  116.352 274.916 116.376 275 ;
    END
  END bus_wdata_o[389]
  PIN bus_wdata_o[38]
    DIRECTION OUTPUT ;
    USE SIGNAL ;
    PORT
      LAYER M4 ;
        RECT  0 233.76 0.084 233.784 ;
    END
  END bus_wdata_o[38]
  PIN bus_wdata_o[390]
    DIRECTION OUTPUT ;
    USE SIGNAL ;
    PORT
      LAYER M5 ;
        RECT  115.968 274.916 115.992 275 ;
    END
  END bus_wdata_o[390]
  PIN bus_wdata_o[391]
    DIRECTION OUTPUT ;
    USE SIGNAL ;
    PORT
      LAYER M5 ;
        RECT  116.736 274.916 116.76 275 ;
    END
  END bus_wdata_o[391]
  PIN bus_wdata_o[392]
    DIRECTION OUTPUT ;
    USE SIGNAL ;
    PORT
      LAYER M5 ;
        RECT  107.616 274.916 107.64 275 ;
    END
  END bus_wdata_o[392]
  PIN bus_wdata_o[393]
    DIRECTION OUTPUT ;
    USE SIGNAL ;
    PORT
      LAYER M5 ;
        RECT  110.4 274.916 110.424 275 ;
    END
  END bus_wdata_o[393]
  PIN bus_wdata_o[394]
    DIRECTION OUTPUT ;
    USE SIGNAL ;
    PORT
      LAYER M5 ;
        RECT  115.584 274.916 115.608 275 ;
    END
  END bus_wdata_o[394]
  PIN bus_wdata_o[395]
    DIRECTION OUTPUT ;
    USE SIGNAL ;
    PORT
      LAYER M5 ;
        RECT  114.432 274.916 114.456 275 ;
    END
  END bus_wdata_o[395]
  PIN bus_wdata_o[396]
    DIRECTION OUTPUT ;
    USE SIGNAL ;
    PORT
      LAYER M5 ;
        RECT  115.104 274.916 115.128 275 ;
    END
  END bus_wdata_o[396]
  PIN bus_wdata_o[397]
    DIRECTION OUTPUT ;
    USE SIGNAL ;
    PORT
      LAYER M5 ;
        RECT  116.064 274.916 116.088 275 ;
    END
  END bus_wdata_o[397]
  PIN bus_wdata_o[398]
    DIRECTION OUTPUT ;
    USE SIGNAL ;
    PORT
      LAYER M5 ;
        RECT  109.44 274.916 109.464 275 ;
    END
  END bus_wdata_o[398]
  PIN bus_wdata_o[399]
    DIRECTION OUTPUT ;
    USE SIGNAL ;
    PORT
      LAYER M5 ;
        RECT  110.304 274.916 110.328 275 ;
    END
  END bus_wdata_o[399]
  PIN bus_wdata_o[39]
    DIRECTION OUTPUT ;
    USE SIGNAL ;
    PORT
      LAYER M5 ;
        RECT  48.576 274.916 48.6 275 ;
    END
  END bus_wdata_o[39]
  PIN bus_wdata_o[3]
    DIRECTION OUTPUT ;
    USE SIGNAL ;
    PORT
      LAYER M4 ;
        RECT  0 219.936 0.084 219.96 ;
    END
  END bus_wdata_o[3]
  PIN bus_wdata_o[400]
    DIRECTION OUTPUT ;
    USE SIGNAL ;
    PORT
      LAYER M5 ;
        RECT  114.048 274.916 114.072 275 ;
    END
  END bus_wdata_o[400]
  PIN bus_wdata_o[401]
    DIRECTION OUTPUT ;
    USE SIGNAL ;
    PORT
      LAYER M5 ;
        RECT  112.8 274.916 112.824 275 ;
    END
  END bus_wdata_o[401]
  PIN bus_wdata_o[402]
    DIRECTION OUTPUT ;
    USE SIGNAL ;
    PORT
      LAYER M5 ;
        RECT  113.568 274.916 113.592 275 ;
    END
  END bus_wdata_o[402]
  PIN bus_wdata_o[403]
    DIRECTION OUTPUT ;
    USE SIGNAL ;
    PORT
      LAYER M5 ;
        RECT  107.136 274.916 107.16 275 ;
    END
  END bus_wdata_o[403]
  PIN bus_wdata_o[404]
    DIRECTION OUTPUT ;
    USE SIGNAL ;
    PORT
      LAYER M5 ;
        RECT  112.032 274.916 112.056 275 ;
    END
  END bus_wdata_o[404]
  PIN bus_wdata_o[405]
    DIRECTION OUTPUT ;
    USE SIGNAL ;
    PORT
      LAYER M5 ;
        RECT  113.664 274.916 113.688 275 ;
    END
  END bus_wdata_o[405]
  PIN bus_wdata_o[406]
    DIRECTION OUTPUT ;
    USE SIGNAL ;
    PORT
      LAYER M5 ;
        RECT  111.36 274.916 111.384 275 ;
    END
  END bus_wdata_o[406]
  PIN bus_wdata_o[407]
    DIRECTION OUTPUT ;
    USE SIGNAL ;
    PORT
      LAYER M5 ;
        RECT  111.84 274.916 111.864 275 ;
    END
  END bus_wdata_o[407]
  PIN bus_wdata_o[408]
    DIRECTION OUTPUT ;
    USE SIGNAL ;
    PORT
      LAYER M5 ;
        RECT  112.704 274.916 112.728 275 ;
    END
  END bus_wdata_o[408]
  PIN bus_wdata_o[409]
    DIRECTION OUTPUT ;
    USE SIGNAL ;
    PORT
      LAYER M5 ;
        RECT  110.976 274.916 111 275 ;
    END
  END bus_wdata_o[409]
  PIN bus_wdata_o[40]
    DIRECTION OUTPUT ;
    USE SIGNAL ;
    PORT
      LAYER M5 ;
        RECT  52.416 274.916 52.44 275 ;
    END
  END bus_wdata_o[40]
  PIN bus_wdata_o[410]
    DIRECTION OUTPUT ;
    USE SIGNAL ;
    PORT
      LAYER M5 ;
        RECT  110.88 274.916 110.904 275 ;
    END
  END bus_wdata_o[410]
  PIN bus_wdata_o[411]
    DIRECTION OUTPUT ;
    USE SIGNAL ;
    PORT
      LAYER M5 ;
        RECT  108 274.916 108.024 275 ;
    END
  END bus_wdata_o[411]
  PIN bus_wdata_o[412]
    DIRECTION OUTPUT ;
    USE SIGNAL ;
    PORT
      LAYER M5 ;
        RECT  115.488 274.916 115.512 275 ;
    END
  END bus_wdata_o[412]
  PIN bus_wdata_o[413]
    DIRECTION OUTPUT ;
    USE SIGNAL ;
    PORT
      LAYER M5 ;
        RECT  114.912 274.916 114.936 275 ;
    END
  END bus_wdata_o[413]
  PIN bus_wdata_o[414]
    DIRECTION OUTPUT ;
    USE SIGNAL ;
    PORT
      LAYER M5 ;
        RECT  114.528 274.916 114.552 275 ;
    END
  END bus_wdata_o[414]
  PIN bus_wdata_o[415]
    DIRECTION OUTPUT ;
    USE SIGNAL ;
    PORT
      LAYER M5 ;
        RECT  108.288 274.916 108.312 275 ;
    END
  END bus_wdata_o[415]
  PIN bus_wdata_o[416]
    DIRECTION OUTPUT ;
    USE SIGNAL ;
    PORT
      LAYER M5 ;
        RECT  112.416 274.916 112.44 275 ;
    END
  END bus_wdata_o[416]
  PIN bus_wdata_o[417]
    DIRECTION OUTPUT ;
    USE SIGNAL ;
    PORT
      LAYER M5 ;
        RECT  110.112 274.916 110.136 275 ;
    END
  END bus_wdata_o[417]
  PIN bus_wdata_o[418]
    DIRECTION OUTPUT ;
    USE SIGNAL ;
    PORT
      LAYER M5 ;
        RECT  117.12 274.916 117.144 275 ;
    END
  END bus_wdata_o[418]
  PIN bus_wdata_o[419]
    DIRECTION OUTPUT ;
    USE SIGNAL ;
    PORT
      LAYER M5 ;
        RECT  116.544 274.916 116.568 275 ;
    END
  END bus_wdata_o[419]
  PIN bus_wdata_o[41]
    DIRECTION OUTPUT ;
    USE SIGNAL ;
    PORT
      LAYER M5 ;
        RECT  52.512 274.916 52.536 275 ;
    END
  END bus_wdata_o[41]
  PIN bus_wdata_o[420]
    DIRECTION OUTPUT ;
    USE SIGNAL ;
    PORT
      LAYER M5 ;
        RECT  112.992 274.916 113.016 275 ;
    END
  END bus_wdata_o[420]
  PIN bus_wdata_o[421]
    DIRECTION OUTPUT ;
    USE SIGNAL ;
    PORT
      LAYER M5 ;
        RECT  113.088 274.916 113.112 275 ;
    END
  END bus_wdata_o[421]
  PIN bus_wdata_o[422]
    DIRECTION OUTPUT ;
    USE SIGNAL ;
    PORT
      LAYER M5 ;
        RECT  109.632 274.916 109.656 275 ;
    END
  END bus_wdata_o[422]
  PIN bus_wdata_o[423]
    DIRECTION OUTPUT ;
    USE SIGNAL ;
    PORT
      LAYER M5 ;
        RECT  114.72 274.916 114.744 275 ;
    END
  END bus_wdata_o[423]
  PIN bus_wdata_o[424]
    DIRECTION OUTPUT ;
    USE SIGNAL ;
    PORT
      LAYER M5 ;
        RECT  117.312 274.916 117.336 275 ;
    END
  END bus_wdata_o[424]
  PIN bus_wdata_o[425]
    DIRECTION OUTPUT ;
    USE SIGNAL ;
    PORT
      LAYER M5 ;
        RECT  108.576 274.916 108.6 275 ;
    END
  END bus_wdata_o[425]
  PIN bus_wdata_o[426]
    DIRECTION OUTPUT ;
    USE SIGNAL ;
    PORT
      LAYER M5 ;
        RECT  114.336 274.916 114.36 275 ;
    END
  END bus_wdata_o[426]
  PIN bus_wdata_o[427]
    DIRECTION OUTPUT ;
    USE SIGNAL ;
    PORT
      LAYER M5 ;
        RECT  117.6 274.916 117.624 275 ;
    END
  END bus_wdata_o[427]
  PIN bus_wdata_o[428]
    DIRECTION OUTPUT ;
    USE SIGNAL ;
    PORT
      LAYER M5 ;
        RECT  117.792 274.916 117.816 275 ;
    END
  END bus_wdata_o[428]
  PIN bus_wdata_o[429]
    DIRECTION OUTPUT ;
    USE SIGNAL ;
    PORT
      LAYER M5 ;
        RECT  115.392 274.916 115.416 275 ;
    END
  END bus_wdata_o[429]
  PIN bus_wdata_o[42]
    DIRECTION OUTPUT ;
    USE SIGNAL ;
    PORT
      LAYER M5 ;
        RECT  48.288 274.916 48.312 275 ;
    END
  END bus_wdata_o[42]
  PIN bus_wdata_o[430]
    DIRECTION OUTPUT ;
    USE SIGNAL ;
    PORT
      LAYER M5 ;
        RECT  117.216 274.916 117.24 275 ;
    END
  END bus_wdata_o[430]
  PIN bus_wdata_o[431]
    DIRECTION OUTPUT ;
    USE SIGNAL ;
    PORT
      LAYER M5 ;
        RECT  116.448 274.916 116.472 275 ;
    END
  END bus_wdata_o[431]
  PIN bus_wdata_o[432]
    DIRECTION OUTPUT ;
    USE SIGNAL ;
    PORT
      LAYER M5 ;
        RECT  118.368 274.916 118.392 275 ;
    END
  END bus_wdata_o[432]
  PIN bus_wdata_o[433]
    DIRECTION OUTPUT ;
    USE SIGNAL ;
    PORT
      LAYER M5 ;
        RECT  116.16 274.916 116.184 275 ;
    END
  END bus_wdata_o[433]
  PIN bus_wdata_o[434]
    DIRECTION OUTPUT ;
    USE SIGNAL ;
    PORT
      LAYER M5 ;
        RECT  117.024 274.916 117.048 275 ;
    END
  END bus_wdata_o[434]
  PIN bus_wdata_o[435]
    DIRECTION OUTPUT ;
    USE SIGNAL ;
    PORT
      LAYER M5 ;
        RECT  119.616 274.916 119.64 275 ;
    END
  END bus_wdata_o[435]
  PIN bus_wdata_o[436]
    DIRECTION OUTPUT ;
    USE SIGNAL ;
    PORT
      LAYER M5 ;
        RECT  117.408 274.916 117.432 275 ;
    END
  END bus_wdata_o[436]
  PIN bus_wdata_o[437]
    DIRECTION OUTPUT ;
    USE SIGNAL ;
    PORT
      LAYER M5 ;
        RECT  106.752 274.916 106.776 275 ;
    END
  END bus_wdata_o[437]
  PIN bus_wdata_o[438]
    DIRECTION OUTPUT ;
    USE SIGNAL ;
    PORT
      LAYER M5 ;
        RECT  120 274.916 120.024 275 ;
    END
  END bus_wdata_o[438]
  PIN bus_wdata_o[439]
    DIRECTION OUTPUT ;
    USE SIGNAL ;
    PORT
      LAYER M5 ;
        RECT  120.384 274.916 120.408 275 ;
    END
  END bus_wdata_o[439]
  PIN bus_wdata_o[43]
    DIRECTION OUTPUT ;
    USE SIGNAL ;
    PORT
      LAYER M5 ;
        RECT  53.76 274.916 53.784 275 ;
    END
  END bus_wdata_o[43]
  PIN bus_wdata_o[440]
    DIRECTION OUTPUT ;
    USE SIGNAL ;
    PORT
      LAYER M5 ;
        RECT  120.288 274.916 120.312 275 ;
    END
  END bus_wdata_o[440]
  PIN bus_wdata_o[441]
    DIRECTION OUTPUT ;
    USE SIGNAL ;
    PORT
      LAYER M5 ;
        RECT  120.192 274.916 120.216 275 ;
    END
  END bus_wdata_o[441]
  PIN bus_wdata_o[442]
    DIRECTION OUTPUT ;
    USE SIGNAL ;
    PORT
      LAYER M4 ;
        RECT  161.916 249.792 162 249.816 ;
    END
  END bus_wdata_o[442]
  PIN bus_wdata_o[443]
    DIRECTION OUTPUT ;
    USE SIGNAL ;
    PORT
      LAYER M4 ;
        RECT  161.916 243.264 162 243.288 ;
    END
  END bus_wdata_o[443]
  PIN bus_wdata_o[444]
    DIRECTION OUTPUT ;
    USE SIGNAL ;
    PORT
      LAYER M4 ;
        RECT  161.916 236.352 162 236.376 ;
    END
  END bus_wdata_o[444]
  PIN bus_wdata_o[445]
    DIRECTION OUTPUT ;
    USE SIGNAL ;
    PORT
      LAYER M4 ;
        RECT  161.916 243.36 162 243.384 ;
    END
  END bus_wdata_o[445]
  PIN bus_wdata_o[446]
    DIRECTION OUTPUT ;
    USE SIGNAL ;
    PORT
      LAYER M4 ;
        RECT  161.916 248.544 162 248.568 ;
    END
  END bus_wdata_o[446]
  PIN bus_wdata_o[447]
    DIRECTION OUTPUT ;
    USE SIGNAL ;
    PORT
      LAYER M4 ;
        RECT  161.916 240.384 162 240.408 ;
    END
  END bus_wdata_o[447]
  PIN bus_wdata_o[448]
    DIRECTION OUTPUT ;
    USE SIGNAL ;
    PORT
      LAYER M4 ;
        RECT  161.916 237.312 162 237.336 ;
    END
  END bus_wdata_o[448]
  PIN bus_wdata_o[449]
    DIRECTION OUTPUT ;
    USE SIGNAL ;
    PORT
      LAYER M4 ;
        RECT  161.916 231.168 162 231.192 ;
    END
  END bus_wdata_o[449]
  PIN bus_wdata_o[44]
    DIRECTION OUTPUT ;
    USE SIGNAL ;
    PORT
      LAYER M5 ;
        RECT  51.744 274.916 51.768 275 ;
    END
  END bus_wdata_o[44]
  PIN bus_wdata_o[450]
    DIRECTION OUTPUT ;
    USE SIGNAL ;
    PORT
      LAYER M5 ;
        RECT  116.832 274.916 116.856 275 ;
    END
  END bus_wdata_o[450]
  PIN bus_wdata_o[451]
    DIRECTION OUTPUT ;
    USE SIGNAL ;
    PORT
      LAYER M5 ;
        RECT  119.232 274.916 119.256 275 ;
    END
  END bus_wdata_o[451]
  PIN bus_wdata_o[452]
    DIRECTION OUTPUT ;
    USE SIGNAL ;
    PORT
      LAYER M5 ;
        RECT  112.608 274.916 112.632 275 ;
    END
  END bus_wdata_o[452]
  PIN bus_wdata_o[453]
    DIRECTION OUTPUT ;
    USE SIGNAL ;
    PORT
      LAYER M5 ;
        RECT  111.648 274.916 111.672 275 ;
    END
  END bus_wdata_o[453]
  PIN bus_wdata_o[454]
    DIRECTION OUTPUT ;
    USE SIGNAL ;
    PORT
      LAYER M5 ;
        RECT  118.848 274.916 118.872 275 ;
    END
  END bus_wdata_o[454]
  PIN bus_wdata_o[455]
    DIRECTION OUTPUT ;
    USE SIGNAL ;
    PORT
      LAYER M5 ;
        RECT  107.424 274.916 107.448 275 ;
    END
  END bus_wdata_o[455]
  PIN bus_wdata_o[456]
    DIRECTION OUTPUT ;
    USE SIGNAL ;
    PORT
      LAYER M5 ;
        RECT  118.56 274.916 118.584 275 ;
    END
  END bus_wdata_o[456]
  PIN bus_wdata_o[457]
    DIRECTION OUTPUT ;
    USE SIGNAL ;
    PORT
      LAYER M5 ;
        RECT  113.76 274.916 113.784 275 ;
    END
  END bus_wdata_o[457]
  PIN bus_wdata_o[458]
    DIRECTION OUTPUT ;
    USE SIGNAL ;
    PORT
      LAYER M5 ;
        RECT  119.136 274.916 119.16 275 ;
    END
  END bus_wdata_o[458]
  PIN bus_wdata_o[459]
    DIRECTION OUTPUT ;
    USE SIGNAL ;
    PORT
      LAYER M5 ;
        RECT  118.944 274.916 118.968 275 ;
    END
  END bus_wdata_o[459]
  PIN bus_wdata_o[45]
    DIRECTION OUTPUT ;
    USE SIGNAL ;
    PORT
      LAYER M5 ;
        RECT  53.664 274.916 53.688 275 ;
    END
  END bus_wdata_o[45]
  PIN bus_wdata_o[460]
    DIRECTION OUTPUT ;
    USE SIGNAL ;
    PORT
      LAYER M5 ;
        RECT  119.904 274.916 119.928 275 ;
    END
  END bus_wdata_o[460]
  PIN bus_wdata_o[461]
    DIRECTION OUTPUT ;
    USE SIGNAL ;
    PORT
      LAYER M5 ;
        RECT  118.176 274.916 118.2 275 ;
    END
  END bus_wdata_o[461]
  PIN bus_wdata_o[462]
    DIRECTION OUTPUT ;
    USE SIGNAL ;
    PORT
      LAYER M4 ;
        RECT  161.916 239.616 162 239.64 ;
    END
  END bus_wdata_o[462]
  PIN bus_wdata_o[463]
    DIRECTION OUTPUT ;
    USE SIGNAL ;
    PORT
      LAYER M5 ;
        RECT  120.096 274.916 120.12 275 ;
    END
  END bus_wdata_o[463]
  PIN bus_wdata_o[464]
    DIRECTION OUTPUT ;
    USE SIGNAL ;
    PORT
      LAYER M5 ;
        RECT  120.48 274.916 120.504 275 ;
    END
  END bus_wdata_o[464]
  PIN bus_wdata_o[465]
    DIRECTION OUTPUT ;
    USE SIGNAL ;
    PORT
      LAYER M4 ;
        RECT  161.916 242.592 162 242.616 ;
    END
  END bus_wdata_o[465]
  PIN bus_wdata_o[466]
    DIRECTION OUTPUT ;
    USE SIGNAL ;
    PORT
      LAYER M4 ;
        RECT  161.916 237.6 162 237.624 ;
    END
  END bus_wdata_o[466]
  PIN bus_wdata_o[467]
    DIRECTION OUTPUT ;
    USE SIGNAL ;
    PORT
      LAYER M5 ;
        RECT  119.424 274.916 119.448 275 ;
    END
  END bus_wdata_o[467]
  PIN bus_wdata_o[468]
    DIRECTION OUTPUT ;
    USE SIGNAL ;
    PORT
      LAYER M4 ;
        RECT  161.916 244.608 162 244.632 ;
    END
  END bus_wdata_o[468]
  PIN bus_wdata_o[469]
    DIRECTION OUTPUT ;
    USE SIGNAL ;
    PORT
      LAYER M4 ;
        RECT  161.916 248.256 162 248.28 ;
    END
  END bus_wdata_o[469]
  PIN bus_wdata_o[46]
    DIRECTION OUTPUT ;
    USE SIGNAL ;
    PORT
      LAYER M5 ;
        RECT  54.24 274.916 54.264 275 ;
    END
  END bus_wdata_o[46]
  PIN bus_wdata_o[470]
    DIRECTION OUTPUT ;
    USE SIGNAL ;
    PORT
      LAYER M4 ;
        RECT  161.916 247.296 162 247.32 ;
    END
  END bus_wdata_o[470]
  PIN bus_wdata_o[471]
    DIRECTION OUTPUT ;
    USE SIGNAL ;
    PORT
      LAYER M4 ;
        RECT  161.916 249.216 162 249.24 ;
    END
  END bus_wdata_o[471]
  PIN bus_wdata_o[472]
    DIRECTION OUTPUT ;
    USE SIGNAL ;
    PORT
      LAYER M4 ;
        RECT  161.916 236.544 162 236.568 ;
    END
  END bus_wdata_o[472]
  PIN bus_wdata_o[473]
    DIRECTION OUTPUT ;
    USE SIGNAL ;
    PORT
      LAYER M4 ;
        RECT  161.916 241.248 162 241.272 ;
    END
  END bus_wdata_o[473]
  PIN bus_wdata_o[474]
    DIRECTION OUTPUT ;
    USE SIGNAL ;
    PORT
      LAYER M4 ;
        RECT  161.916 236.928 162 236.952 ;
    END
  END bus_wdata_o[474]
  PIN bus_wdata_o[475]
    DIRECTION OUTPUT ;
    USE SIGNAL ;
    PORT
      LAYER M4 ;
        RECT  161.916 241.344 162 241.368 ;
    END
  END bus_wdata_o[475]
  PIN bus_wdata_o[476]
    DIRECTION OUTPUT ;
    USE SIGNAL ;
    PORT
      LAYER M4 ;
        RECT  161.916 235.488 162 235.512 ;
    END
  END bus_wdata_o[476]
  PIN bus_wdata_o[477]
    DIRECTION OUTPUT ;
    USE SIGNAL ;
    PORT
      LAYER M4 ;
        RECT  161.916 242.496 162 242.52 ;
    END
  END bus_wdata_o[477]
  PIN bus_wdata_o[478]
    DIRECTION OUTPUT ;
    USE SIGNAL ;
    PORT
      LAYER M4 ;
        RECT  161.916 235.776 162 235.8 ;
    END
  END bus_wdata_o[478]
  PIN bus_wdata_o[479]
    DIRECTION OUTPUT ;
    USE SIGNAL ;
    PORT
      LAYER M4 ;
        RECT  161.916 245.568 162 245.592 ;
    END
  END bus_wdata_o[479]
  PIN bus_wdata_o[47]
    DIRECTION OUTPUT ;
    USE SIGNAL ;
    PORT
      LAYER M5 ;
        RECT  59.136 274.916 59.16 275 ;
    END
  END bus_wdata_o[47]
  PIN bus_wdata_o[480]
    DIRECTION OUTPUT ;
    USE SIGNAL ;
    PORT
      LAYER M4 ;
        RECT  161.916 248.448 162 248.472 ;
    END
  END bus_wdata_o[480]
  PIN bus_wdata_o[481]
    DIRECTION OUTPUT ;
    USE SIGNAL ;
    PORT
      LAYER M4 ;
        RECT  161.916 247.872 162 247.896 ;
    END
  END bus_wdata_o[481]
  PIN bus_wdata_o[482]
    DIRECTION OUTPUT ;
    USE SIGNAL ;
    PORT
      LAYER M4 ;
        RECT  161.916 243.072 162 243.096 ;
    END
  END bus_wdata_o[482]
  PIN bus_wdata_o[483]
    DIRECTION OUTPUT ;
    USE SIGNAL ;
    PORT
      LAYER M4 ;
        RECT  161.916 242.976 162 243 ;
    END
  END bus_wdata_o[483]
  PIN bus_wdata_o[484]
    DIRECTION OUTPUT ;
    USE SIGNAL ;
    PORT
      LAYER M4 ;
        RECT  161.916 240.192 162 240.216 ;
    END
  END bus_wdata_o[484]
  PIN bus_wdata_o[485]
    DIRECTION OUTPUT ;
    USE SIGNAL ;
    PORT
      LAYER M4 ;
        RECT  161.916 246.336 162 246.36 ;
    END
  END bus_wdata_o[485]
  PIN bus_wdata_o[486]
    DIRECTION OUTPUT ;
    USE SIGNAL ;
    PORT
      LAYER M4 ;
        RECT  161.916 243.936 162 243.96 ;
    END
  END bus_wdata_o[486]
  PIN bus_wdata_o[487]
    DIRECTION OUTPUT ;
    USE SIGNAL ;
    PORT
      LAYER M4 ;
        RECT  161.916 242.4 162 242.424 ;
    END
  END bus_wdata_o[487]
  PIN bus_wdata_o[488]
    DIRECTION OUTPUT ;
    USE SIGNAL ;
    PORT
      LAYER M4 ;
        RECT  161.916 238.656 162 238.68 ;
    END
  END bus_wdata_o[488]
  PIN bus_wdata_o[489]
    DIRECTION OUTPUT ;
    USE SIGNAL ;
    PORT
      LAYER M4 ;
        RECT  161.916 240.864 162 240.888 ;
    END
  END bus_wdata_o[489]
  PIN bus_wdata_o[48]
    DIRECTION OUTPUT ;
    USE SIGNAL ;
    PORT
      LAYER M5 ;
        RECT  60.192 274.916 60.216 275 ;
    END
  END bus_wdata_o[48]
  PIN bus_wdata_o[490]
    DIRECTION OUTPUT ;
    USE SIGNAL ;
    PORT
      LAYER M4 ;
        RECT  161.916 244.8 162 244.824 ;
    END
  END bus_wdata_o[490]
  PIN bus_wdata_o[491]
    DIRECTION OUTPUT ;
    USE SIGNAL ;
    PORT
      LAYER M4 ;
        RECT  161.916 242.88 162 242.904 ;
    END
  END bus_wdata_o[491]
  PIN bus_wdata_o[492]
    DIRECTION OUTPUT ;
    USE SIGNAL ;
    PORT
      LAYER M4 ;
        RECT  161.916 244.416 162 244.44 ;
    END
  END bus_wdata_o[492]
  PIN bus_wdata_o[493]
    DIRECTION OUTPUT ;
    USE SIGNAL ;
    PORT
      LAYER M4 ;
        RECT  161.916 248.928 162 248.952 ;
    END
  END bus_wdata_o[493]
  PIN bus_wdata_o[494]
    DIRECTION OUTPUT ;
    USE SIGNAL ;
    PORT
      LAYER M4 ;
        RECT  161.916 247.104 162 247.128 ;
    END
  END bus_wdata_o[494]
  PIN bus_wdata_o[495]
    DIRECTION OUTPUT ;
    USE SIGNAL ;
    PORT
      LAYER M4 ;
        RECT  161.916 248.352 162 248.376 ;
    END
  END bus_wdata_o[495]
  PIN bus_wdata_o[496]
    DIRECTION OUTPUT ;
    USE SIGNAL ;
    PORT
      LAYER M4 ;
        RECT  161.916 249.504 162 249.528 ;
    END
  END bus_wdata_o[496]
  PIN bus_wdata_o[497]
    DIRECTION OUTPUT ;
    USE SIGNAL ;
    PORT
      LAYER M4 ;
        RECT  161.916 245.28 162 245.304 ;
    END
  END bus_wdata_o[497]
  PIN bus_wdata_o[498]
    DIRECTION OUTPUT ;
    USE SIGNAL ;
    PORT
      LAYER M4 ;
        RECT  161.916 248.16 162 248.184 ;
    END
  END bus_wdata_o[498]
  PIN bus_wdata_o[499]
    DIRECTION OUTPUT ;
    USE SIGNAL ;
    PORT
      LAYER M4 ;
        RECT  161.916 237.12 162 237.144 ;
    END
  END bus_wdata_o[499]
  PIN bus_wdata_o[49]
    DIRECTION OUTPUT ;
    USE SIGNAL ;
    PORT
      LAYER M5 ;
        RECT  55.68 274.916 55.704 275 ;
    END
  END bus_wdata_o[49]
  PIN bus_wdata_o[4]
    DIRECTION OUTPUT ;
    USE SIGNAL ;
    PORT
      LAYER M4 ;
        RECT  0 222.912 0.084 222.936 ;
    END
  END bus_wdata_o[4]
  PIN bus_wdata_o[500]
    DIRECTION OUTPUT ;
    USE SIGNAL ;
    PORT
      LAYER M4 ;
        RECT  161.916 234.816 162 234.84 ;
    END
  END bus_wdata_o[500]
  PIN bus_wdata_o[501]
    DIRECTION OUTPUT ;
    USE SIGNAL ;
    PORT
      LAYER M4 ;
        RECT  161.916 244.128 162 244.152 ;
    END
  END bus_wdata_o[501]
  PIN bus_wdata_o[502]
    DIRECTION OUTPUT ;
    USE SIGNAL ;
    PORT
      LAYER M4 ;
        RECT  161.916 235.296 162 235.32 ;
    END
  END bus_wdata_o[502]
  PIN bus_wdata_o[503]
    DIRECTION OUTPUT ;
    USE SIGNAL ;
    PORT
      LAYER M4 ;
        RECT  161.916 243.84 162 243.864 ;
    END
  END bus_wdata_o[503]
  PIN bus_wdata_o[504]
    DIRECTION OUTPUT ;
    USE SIGNAL ;
    PORT
      LAYER M4 ;
        RECT  161.916 238.08 162 238.104 ;
    END
  END bus_wdata_o[504]
  PIN bus_wdata_o[505]
    DIRECTION OUTPUT ;
    USE SIGNAL ;
    PORT
      LAYER M4 ;
        RECT  161.916 238.176 162 238.2 ;
    END
  END bus_wdata_o[505]
  PIN bus_wdata_o[506]
    DIRECTION OUTPUT ;
    USE SIGNAL ;
    PORT
      LAYER M4 ;
        RECT  161.916 240.096 162 240.12 ;
    END
  END bus_wdata_o[506]
  PIN bus_wdata_o[507]
    DIRECTION OUTPUT ;
    USE SIGNAL ;
    PORT
      LAYER M4 ;
        RECT  161.916 247.68 162 247.704 ;
    END
  END bus_wdata_o[507]
  PIN bus_wdata_o[508]
    DIRECTION OUTPUT ;
    USE SIGNAL ;
    PORT
      LAYER M4 ;
        RECT  161.916 237.792 162 237.816 ;
    END
  END bus_wdata_o[508]
  PIN bus_wdata_o[509]
    DIRECTION OUTPUT ;
    USE SIGNAL ;
    PORT
      LAYER M4 ;
        RECT  161.916 239.52 162 239.544 ;
    END
  END bus_wdata_o[509]
  PIN bus_wdata_o[50]
    DIRECTION OUTPUT ;
    USE SIGNAL ;
    PORT
      LAYER M5 ;
        RECT  59.424 274.916 59.448 275 ;
    END
  END bus_wdata_o[50]
  PIN bus_wdata_o[510]
    DIRECTION OUTPUT ;
    USE SIGNAL ;
    PORT
      LAYER M4 ;
        RECT  161.916 246.624 162 246.648 ;
    END
  END bus_wdata_o[510]
  PIN bus_wdata_o[511]
    DIRECTION OUTPUT ;
    USE SIGNAL ;
    PORT
      LAYER M5 ;
        RECT  109.92 274.916 109.944 275 ;
    END
  END bus_wdata_o[511]
  PIN bus_wdata_o[51]
    DIRECTION OUTPUT ;
    USE SIGNAL ;
    PORT
      LAYER M5 ;
        RECT  54.048 274.916 54.072 275 ;
    END
  END bus_wdata_o[51]
  PIN bus_wdata_o[52]
    DIRECTION OUTPUT ;
    USE SIGNAL ;
    PORT
      LAYER M5 ;
        RECT  61.536 274.916 61.56 275 ;
    END
  END bus_wdata_o[52]
  PIN bus_wdata_o[53]
    DIRECTION OUTPUT ;
    USE SIGNAL ;
    PORT
      LAYER M5 ;
        RECT  59.328 274.916 59.352 275 ;
    END
  END bus_wdata_o[53]
  PIN bus_wdata_o[54]
    DIRECTION OUTPUT ;
    USE SIGNAL ;
    PORT
      LAYER M5 ;
        RECT  58.944 274.916 58.968 275 ;
    END
  END bus_wdata_o[54]
  PIN bus_wdata_o[55]
    DIRECTION OUTPUT ;
    USE SIGNAL ;
    PORT
      LAYER M5 ;
        RECT  59.232 274.916 59.256 275 ;
    END
  END bus_wdata_o[55]
  PIN bus_wdata_o[56]
    DIRECTION OUTPUT ;
    USE SIGNAL ;
    PORT
      LAYER M5 ;
        RECT  49.248 274.916 49.272 275 ;
    END
  END bus_wdata_o[56]
  PIN bus_wdata_o[57]
    DIRECTION OUTPUT ;
    USE SIGNAL ;
    PORT
      LAYER M4 ;
        RECT  0 235.296 0.084 235.32 ;
    END
  END bus_wdata_o[57]
  PIN bus_wdata_o[58]
    DIRECTION OUTPUT ;
    USE SIGNAL ;
    PORT
      LAYER M4 ;
        RECT  0 232.704 0.084 232.728 ;
    END
  END bus_wdata_o[58]
  PIN bus_wdata_o[59]
    DIRECTION OUTPUT ;
    USE SIGNAL ;
    PORT
      LAYER M4 ;
        RECT  0 217.728 0.084 217.752 ;
    END
  END bus_wdata_o[59]
  PIN bus_wdata_o[5]
    DIRECTION OUTPUT ;
    USE SIGNAL ;
    PORT
      LAYER M4 ;
        RECT  0 221.088 0.084 221.112 ;
    END
  END bus_wdata_o[5]
  PIN bus_wdata_o[60]
    DIRECTION OUTPUT ;
    USE SIGNAL ;
    PORT
      LAYER M4 ;
        RECT  0 217.344 0.084 217.368 ;
    END
  END bus_wdata_o[60]
  PIN bus_wdata_o[61]
    DIRECTION OUTPUT ;
    USE SIGNAL ;
    PORT
      LAYER M4 ;
        RECT  0 230.784 0.084 230.808 ;
    END
  END bus_wdata_o[61]
  PIN bus_wdata_o[62]
    DIRECTION OUTPUT ;
    USE SIGNAL ;
    PORT
      LAYER M4 ;
        RECT  0 231.648 0.084 231.672 ;
    END
  END bus_wdata_o[62]
  PIN bus_wdata_o[63]
    DIRECTION OUTPUT ;
    USE SIGNAL ;
    PORT
      LAYER M4 ;
        RECT  0 232.608 0.084 232.632 ;
    END
  END bus_wdata_o[63]
  PIN bus_wdata_o[64]
    DIRECTION OUTPUT ;
    USE SIGNAL ;
    PORT
      LAYER M4 ;
        RECT  0 217.056 0.084 217.08 ;
    END
  END bus_wdata_o[64]
  PIN bus_wdata_o[65]
    DIRECTION OUTPUT ;
    USE SIGNAL ;
    PORT
      LAYER M4 ;
        RECT  0 230.592 0.084 230.616 ;
    END
  END bus_wdata_o[65]
  PIN bus_wdata_o[66]
    DIRECTION OUTPUT ;
    USE SIGNAL ;
    PORT
      LAYER M4 ;
        RECT  0 229.728 0.084 229.752 ;
    END
  END bus_wdata_o[66]
  PIN bus_wdata_o[67]
    DIRECTION OUTPUT ;
    USE SIGNAL ;
    PORT
      LAYER M4 ;
        RECT  0 231.744 0.084 231.768 ;
    END
  END bus_wdata_o[67]
  PIN bus_wdata_o[68]
    DIRECTION OUTPUT ;
    USE SIGNAL ;
    PORT
      LAYER M4 ;
        RECT  0 234.816 0.084 234.84 ;
    END
  END bus_wdata_o[68]
  PIN bus_wdata_o[69]
    DIRECTION OUTPUT ;
    USE SIGNAL ;
    PORT
      LAYER M4 ;
        RECT  0 216.96 0.084 216.984 ;
    END
  END bus_wdata_o[69]
  PIN bus_wdata_o[6]
    DIRECTION OUTPUT ;
    USE SIGNAL ;
    PORT
      LAYER M4 ;
        RECT  0 233.28 0.084 233.304 ;
    END
  END bus_wdata_o[6]
  PIN bus_wdata_o[70]
    DIRECTION OUTPUT ;
    USE SIGNAL ;
    PORT
      LAYER M4 ;
        RECT  0 218.304 0.084 218.328 ;
    END
  END bus_wdata_o[70]
  PIN bus_wdata_o[71]
    DIRECTION OUTPUT ;
    USE SIGNAL ;
    PORT
      LAYER M5 ;
        RECT  49.44 274.916 49.464 275 ;
    END
  END bus_wdata_o[71]
  PIN bus_wdata_o[72]
    DIRECTION OUTPUT ;
    USE SIGNAL ;
    PORT
      LAYER M5 ;
        RECT  51.456 274.916 51.48 275 ;
    END
  END bus_wdata_o[72]
  PIN bus_wdata_o[73]
    DIRECTION OUTPUT ;
    USE SIGNAL ;
    PORT
      LAYER M5 ;
        RECT  48.96 274.916 48.984 275 ;
    END
  END bus_wdata_o[73]
  PIN bus_wdata_o[74]
    DIRECTION OUTPUT ;
    USE SIGNAL ;
    PORT
      LAYER M5 ;
        RECT  52.32 274.916 52.344 275 ;
    END
  END bus_wdata_o[74]
  PIN bus_wdata_o[75]
    DIRECTION OUTPUT ;
    USE SIGNAL ;
    PORT
      LAYER M5 ;
        RECT  53.376 274.916 53.4 275 ;
    END
  END bus_wdata_o[75]
  PIN bus_wdata_o[76]
    DIRECTION OUTPUT ;
    USE SIGNAL ;
    PORT
      LAYER M5 ;
        RECT  49.632 274.916 49.656 275 ;
    END
  END bus_wdata_o[76]
  PIN bus_wdata_o[77]
    DIRECTION OUTPUT ;
    USE SIGNAL ;
    PORT
      LAYER M5 ;
        RECT  53.28 274.916 53.304 275 ;
    END
  END bus_wdata_o[77]
  PIN bus_wdata_o[78]
    DIRECTION OUTPUT ;
    USE SIGNAL ;
    PORT
      LAYER M5 ;
        RECT  54.432 274.916 54.456 275 ;
    END
  END bus_wdata_o[78]
  PIN bus_wdata_o[79]
    DIRECTION OUTPUT ;
    USE SIGNAL ;
    PORT
      LAYER M5 ;
        RECT  58.176 274.916 58.2 275 ;
    END
  END bus_wdata_o[79]
  PIN bus_wdata_o[7]
    DIRECTION OUTPUT ;
    USE SIGNAL ;
    PORT
      LAYER M5 ;
        RECT  50.784 274.916 50.808 275 ;
    END
  END bus_wdata_o[7]
  PIN bus_wdata_o[80]
    DIRECTION OUTPUT ;
    USE SIGNAL ;
    PORT
      LAYER M5 ;
        RECT  60.48 274.916 60.504 275 ;
    END
  END bus_wdata_o[80]
  PIN bus_wdata_o[81]
    DIRECTION OUTPUT ;
    USE SIGNAL ;
    PORT
      LAYER M5 ;
        RECT  55.104 274.916 55.128 275 ;
    END
  END bus_wdata_o[81]
  PIN bus_wdata_o[82]
    DIRECTION OUTPUT ;
    USE SIGNAL ;
    PORT
      LAYER M5 ;
        RECT  56.064 274.916 56.088 275 ;
    END
  END bus_wdata_o[82]
  PIN bus_wdata_o[83]
    DIRECTION OUTPUT ;
    USE SIGNAL ;
    PORT
      LAYER M5 ;
        RECT  54.144 274.916 54.168 275 ;
    END
  END bus_wdata_o[83]
  PIN bus_wdata_o[84]
    DIRECTION OUTPUT ;
    USE SIGNAL ;
    PORT
      LAYER M5 ;
        RECT  61.152 274.916 61.176 275 ;
    END
  END bus_wdata_o[84]
  PIN bus_wdata_o[85]
    DIRECTION OUTPUT ;
    USE SIGNAL ;
    PORT
      LAYER M5 ;
        RECT  59.616 274.916 59.64 275 ;
    END
  END bus_wdata_o[85]
  PIN bus_wdata_o[86]
    DIRECTION OUTPUT ;
    USE SIGNAL ;
    PORT
      LAYER M5 ;
        RECT  59.04 274.916 59.064 275 ;
    END
  END bus_wdata_o[86]
  PIN bus_wdata_o[87]
    DIRECTION OUTPUT ;
    USE SIGNAL ;
    PORT
      LAYER M5 ;
        RECT  48.096 274.916 48.12 275 ;
    END
  END bus_wdata_o[87]
  PIN bus_wdata_o[88]
    DIRECTION OUTPUT ;
    USE SIGNAL ;
    PORT
      LAYER M4 ;
        RECT  0 235.776 0.084 235.8 ;
    END
  END bus_wdata_o[88]
  PIN bus_wdata_o[89]
    DIRECTION OUTPUT ;
    USE SIGNAL ;
    PORT
      LAYER M4 ;
        RECT  0 235.68 0.084 235.704 ;
    END
  END bus_wdata_o[89]
  PIN bus_wdata_o[8]
    DIRECTION OUTPUT ;
    USE SIGNAL ;
    PORT
      LAYER M5 ;
        RECT  49.536 274.916 49.56 275 ;
    END
  END bus_wdata_o[8]
  PIN bus_wdata_o[90]
    DIRECTION OUTPUT ;
    USE SIGNAL ;
    PORT
      LAYER M4 ;
        RECT  0 235.488 0.084 235.512 ;
    END
  END bus_wdata_o[90]
  PIN bus_wdata_o[91]
    DIRECTION OUTPUT ;
    USE SIGNAL ;
    PORT
      LAYER M4 ;
        RECT  0 230.4 0.084 230.424 ;
    END
  END bus_wdata_o[91]
  PIN bus_wdata_o[92]
    DIRECTION OUTPUT ;
    USE SIGNAL ;
    PORT
      LAYER M4 ;
        RECT  0 234.912 0.084 234.936 ;
    END
  END bus_wdata_o[92]
  PIN bus_wdata_o[93]
    DIRECTION OUTPUT ;
    USE SIGNAL ;
    PORT
      LAYER M4 ;
        RECT  0 216.768 0.084 216.792 ;
    END
  END bus_wdata_o[93]
  PIN bus_wdata_o[94]
    DIRECTION OUTPUT ;
    USE SIGNAL ;
    PORT
      LAYER M4 ;
        RECT  0 235.104 0.084 235.128 ;
    END
  END bus_wdata_o[94]
  PIN bus_wdata_o[95]
    DIRECTION OUTPUT ;
    USE SIGNAL ;
    PORT
      LAYER M4 ;
        RECT  0 218.88 0.084 218.904 ;
    END
  END bus_wdata_o[95]
  PIN bus_wdata_o[96]
    DIRECTION OUTPUT ;
    USE SIGNAL ;
    PORT
      LAYER M4 ;
        RECT  0 231.936 0.084 231.96 ;
    END
  END bus_wdata_o[96]
  PIN bus_wdata_o[97]
    DIRECTION OUTPUT ;
    USE SIGNAL ;
    PORT
      LAYER M4 ;
        RECT  0 234.528 0.084 234.552 ;
    END
  END bus_wdata_o[97]
  PIN bus_wdata_o[98]
    DIRECTION OUTPUT ;
    USE SIGNAL ;
    PORT
      LAYER M4 ;
        RECT  0 233.664 0.084 233.688 ;
    END
  END bus_wdata_o[98]
  PIN bus_wdata_o[99]
    DIRECTION OUTPUT ;
    USE SIGNAL ;
    PORT
      LAYER M4 ;
        RECT  0 232.416 0.084 232.44 ;
    END
  END bus_wdata_o[99]
  PIN bus_wdata_o[9]
    DIRECTION OUTPUT ;
    USE SIGNAL ;
    PORT
      LAYER M5 ;
        RECT  50.592 274.916 50.616 275 ;
    END
  END bus_wdata_o[9]
  PIN clk_i
    DIRECTION INPUT ;
    USE SIGNAL ;
    PORT
      LAYER M5 ;
        RECT  79.008 274.916 79.032 275 ;
    END
  END clk_i
  PIN core_clk_en_i
    DIRECTION INPUT ;
    USE SIGNAL ;
    PORT
      LAYER M5 ;
        RECT  67.296 274.916 67.32 275 ;
    END
  END core_clk_en_i
  PIN dbg_csr_addr_i[0]
    DIRECTION INPUT ;
    USE SIGNAL ;
    PORT
      LAYER M5 ;
        RECT  70.176 274.916 70.2 275 ;
    END
  END dbg_csr_addr_i[0]
  PIN dbg_csr_addr_i[10]
    DIRECTION INPUT ;
    USE SIGNAL ;
    PORT
      LAYER M5 ;
        RECT  70.656 274.916 70.68 275 ;
    END
  END dbg_csr_addr_i[10]
  PIN dbg_csr_addr_i[11]
    DIRECTION INPUT ;
    USE SIGNAL ;
    PORT
      LAYER M5 ;
        RECT  71.904 274.916 71.928 275 ;
    END
  END dbg_csr_addr_i[11]
  PIN dbg_csr_addr_i[1]
    DIRECTION INPUT ;
    USE SIGNAL ;
    PORT
      LAYER M5 ;
        RECT  67.584 274.916 67.608 275 ;
    END
  END dbg_csr_addr_i[1]
  PIN dbg_csr_addr_i[2]
    DIRECTION INPUT ;
    USE SIGNAL ;
    PORT
      LAYER M5 ;
        RECT  71.712 274.916 71.736 275 ;
    END
  END dbg_csr_addr_i[2]
  PIN dbg_csr_addr_i[3]
    DIRECTION INPUT ;
    USE SIGNAL ;
    PORT
      LAYER M5 ;
        RECT  69.6 274.916 69.624 275 ;
    END
  END dbg_csr_addr_i[3]
  PIN dbg_csr_addr_i[4]
    DIRECTION INPUT ;
    USE SIGNAL ;
    PORT
      LAYER M5 ;
        RECT  72.192 274.916 72.216 275 ;
    END
  END dbg_csr_addr_i[4]
  PIN dbg_csr_addr_i[5]
    DIRECTION INPUT ;
    USE SIGNAL ;
    PORT
      LAYER M5 ;
        RECT  72.288 274.916 72.312 275 ;
    END
  END dbg_csr_addr_i[5]
  PIN dbg_csr_addr_i[6]
    DIRECTION INPUT ;
    USE SIGNAL ;
    PORT
      LAYER M5 ;
        RECT  72.96 274.916 72.984 275 ;
    END
  END dbg_csr_addr_i[6]
  PIN dbg_csr_addr_i[7]
    DIRECTION INPUT ;
    USE SIGNAL ;
    PORT
      LAYER M5 ;
        RECT  73.152 274.916 73.176 275 ;
    END
  END dbg_csr_addr_i[7]
  PIN dbg_csr_addr_i[8]
    DIRECTION INPUT ;
    USE SIGNAL ;
    PORT
      LAYER M5 ;
        RECT  71.616 274.916 71.64 275 ;
    END
  END dbg_csr_addr_i[8]
  PIN dbg_csr_addr_i[9]
    DIRECTION INPUT ;
    USE SIGNAL ;
    PORT
      LAYER M5 ;
        RECT  71.808 274.916 71.832 275 ;
    END
  END dbg_csr_addr_i[9]
  PIN dbg_csr_rdata_o[0]
    DIRECTION OUTPUT ;
    USE SIGNAL ;
    PORT
      LAYER M5 ;
        RECT  69.984 274.916 70.008 275 ;
    END
  END dbg_csr_rdata_o[0]
  PIN dbg_csr_rdata_o[10]
    DIRECTION OUTPUT ;
    USE SIGNAL ;
    PORT
      LAYER M5 ;
        RECT  71.328 274.916 71.352 275 ;
    END
  END dbg_csr_rdata_o[10]
  PIN dbg_csr_rdata_o[11]
    DIRECTION OUTPUT ;
    USE SIGNAL ;
    PORT
      LAYER M5 ;
        RECT  68.256 274.916 68.28 275 ;
    END
  END dbg_csr_rdata_o[11]
  PIN dbg_csr_rdata_o[12]
    DIRECTION OUTPUT ;
    USE SIGNAL ;
    PORT
      LAYER M5 ;
        RECT  69.792 274.916 69.816 275 ;
    END
  END dbg_csr_rdata_o[12]
  PIN dbg_csr_rdata_o[13]
    DIRECTION OUTPUT ;
    USE SIGNAL ;
    PORT
      LAYER M5 ;
        RECT  68.448 274.916 68.472 275 ;
    END
  END dbg_csr_rdata_o[13]
  PIN dbg_csr_rdata_o[14]
    DIRECTION OUTPUT ;
    USE SIGNAL ;
    PORT
      LAYER M5 ;
        RECT  68.736 274.916 68.76 275 ;
    END
  END dbg_csr_rdata_o[14]
  PIN dbg_csr_rdata_o[15]
    DIRECTION OUTPUT ;
    USE SIGNAL ;
    PORT
      LAYER M5 ;
        RECT  70.848 274.916 70.872 275 ;
    END
  END dbg_csr_rdata_o[15]
  PIN dbg_csr_rdata_o[16]
    DIRECTION OUTPUT ;
    USE SIGNAL ;
    PORT
      LAYER M5 ;
        RECT  70.752 274.916 70.776 275 ;
    END
  END dbg_csr_rdata_o[16]
  PIN dbg_csr_rdata_o[17]
    DIRECTION OUTPUT ;
    USE SIGNAL ;
    PORT
      LAYER M5 ;
        RECT  68.832 274.916 68.856 275 ;
    END
  END dbg_csr_rdata_o[17]
  PIN dbg_csr_rdata_o[18]
    DIRECTION OUTPUT ;
    USE SIGNAL ;
    PORT
      LAYER M5 ;
        RECT  68.928 274.916 68.952 275 ;
    END
  END dbg_csr_rdata_o[18]
  PIN dbg_csr_rdata_o[19]
    DIRECTION OUTPUT ;
    USE SIGNAL ;
    PORT
      LAYER M5 ;
        RECT  68.064 274.916 68.088 275 ;
    END
  END dbg_csr_rdata_o[19]
  PIN dbg_csr_rdata_o[1]
    DIRECTION OUTPUT ;
    USE SIGNAL ;
    PORT
      LAYER M5 ;
        RECT  67.968 274.916 67.992 275 ;
    END
  END dbg_csr_rdata_o[1]
  PIN dbg_csr_rdata_o[20]
    DIRECTION OUTPUT ;
    USE SIGNAL ;
    PORT
      LAYER M5 ;
        RECT  69.12 274.916 69.144 275 ;
    END
  END dbg_csr_rdata_o[20]
  PIN dbg_csr_rdata_o[21]
    DIRECTION OUTPUT ;
    USE SIGNAL ;
    PORT
      LAYER M5 ;
        RECT  69.024 274.916 69.048 275 ;
    END
  END dbg_csr_rdata_o[21]
  PIN dbg_csr_rdata_o[22]
    DIRECTION OUTPUT ;
    USE SIGNAL ;
    PORT
      LAYER M5 ;
        RECT  69.888 274.916 69.912 275 ;
    END
  END dbg_csr_rdata_o[22]
  PIN dbg_csr_rdata_o[23]
    DIRECTION OUTPUT ;
    USE SIGNAL ;
    PORT
      LAYER M5 ;
        RECT  70.368 274.916 70.392 275 ;
    END
  END dbg_csr_rdata_o[23]
  PIN dbg_csr_rdata_o[24]
    DIRECTION OUTPUT ;
    USE SIGNAL ;
    PORT
      LAYER M5 ;
        RECT  67.392 274.916 67.416 275 ;
    END
  END dbg_csr_rdata_o[24]
  PIN dbg_csr_rdata_o[25]
    DIRECTION OUTPUT ;
    USE SIGNAL ;
    PORT
      LAYER M5 ;
        RECT  69.408 274.916 69.432 275 ;
    END
  END dbg_csr_rdata_o[25]
  PIN dbg_csr_rdata_o[26]
    DIRECTION OUTPUT ;
    USE SIGNAL ;
    PORT
      LAYER M5 ;
        RECT  68.352 274.916 68.376 275 ;
    END
  END dbg_csr_rdata_o[26]
  PIN dbg_csr_rdata_o[27]
    DIRECTION OUTPUT ;
    USE SIGNAL ;
    PORT
      LAYER M5 ;
        RECT  69.216 274.916 69.24 275 ;
    END
  END dbg_csr_rdata_o[27]
  PIN dbg_csr_rdata_o[28]
    DIRECTION OUTPUT ;
    USE SIGNAL ;
    PORT
      LAYER M5 ;
        RECT  69.696 274.916 69.72 275 ;
    END
  END dbg_csr_rdata_o[28]
  PIN dbg_csr_rdata_o[29]
    DIRECTION OUTPUT ;
    USE SIGNAL ;
    PORT
      LAYER M5 ;
        RECT  68.544 274.916 68.568 275 ;
    END
  END dbg_csr_rdata_o[29]
  PIN dbg_csr_rdata_o[2]
    DIRECTION OUTPUT ;
    USE SIGNAL ;
    PORT
      LAYER M5 ;
        RECT  71.04 274.916 71.064 275 ;
    END
  END dbg_csr_rdata_o[2]
  PIN dbg_csr_rdata_o[30]
    DIRECTION OUTPUT ;
    USE SIGNAL ;
    PORT
      LAYER M5 ;
        RECT  69.312 274.916 69.336 275 ;
    END
  END dbg_csr_rdata_o[30]
  PIN dbg_csr_rdata_o[31]
    DIRECTION OUTPUT ;
    USE SIGNAL ;
    PORT
      LAYER M5 ;
        RECT  70.464 274.916 70.488 275 ;
    END
  END dbg_csr_rdata_o[31]
  PIN dbg_csr_rdata_o[3]
    DIRECTION OUTPUT ;
    USE SIGNAL ;
    PORT
      LAYER M5 ;
        RECT  71.232 274.916 71.256 275 ;
    END
  END dbg_csr_rdata_o[3]
  PIN dbg_csr_rdata_o[4]
    DIRECTION OUTPUT ;
    USE SIGNAL ;
    PORT
      LAYER M5 ;
        RECT  70.944 274.916 70.968 275 ;
    END
  END dbg_csr_rdata_o[4]
  PIN dbg_csr_rdata_o[5]
    DIRECTION OUTPUT ;
    USE SIGNAL ;
    PORT
      LAYER M5 ;
        RECT  71.424 274.916 71.448 275 ;
    END
  END dbg_csr_rdata_o[5]
  PIN dbg_csr_rdata_o[6]
    DIRECTION OUTPUT ;
    USE SIGNAL ;
    PORT
      LAYER M5 ;
        RECT  71.136 274.916 71.16 275 ;
    END
  END dbg_csr_rdata_o[6]
  PIN dbg_csr_rdata_o[7]
    DIRECTION OUTPUT ;
    USE SIGNAL ;
    PORT
      LAYER M5 ;
        RECT  68.64 274.916 68.664 275 ;
    END
  END dbg_csr_rdata_o[7]
  PIN dbg_csr_rdata_o[8]
    DIRECTION OUTPUT ;
    USE SIGNAL ;
    PORT
      LAYER M5 ;
        RECT  71.52 274.916 71.544 275 ;
    END
  END dbg_csr_rdata_o[8]
  PIN dbg_csr_rdata_o[9]
    DIRECTION OUTPUT ;
    USE SIGNAL ;
    PORT
      LAYER M5 ;
        RECT  69.504 274.916 69.528 275 ;
    END
  END dbg_csr_rdata_o[9]
  PIN dbg_csr_we_i
    DIRECTION INPUT ;
    USE SIGNAL ;
    PORT
      LAYER M5 ;
        RECT  73.248 274.916 73.272 275 ;
    END
  END dbg_csr_we_i
  PIN dbg_pc_o[0]
    DIRECTION OUTPUT ;
    USE SIGNAL ;
    PORT
      LAYER M5 ;
        RECT  82.752 274.916 82.776 275 ;
    END
  END dbg_pc_o[0]
  PIN dbg_pc_o[10]
    DIRECTION OUTPUT ;
    USE SIGNAL ;
    PORT
      LAYER M5 ;
        RECT  82.944 274.916 82.968 275 ;
    END
  END dbg_pc_o[10]
  PIN dbg_pc_o[11]
    DIRECTION OUTPUT ;
    USE SIGNAL ;
    PORT
      LAYER M5 ;
        RECT  82.848 274.916 82.872 275 ;
    END
  END dbg_pc_o[11]
  PIN dbg_pc_o[12]
    DIRECTION OUTPUT ;
    USE SIGNAL ;
    PORT
      LAYER M5 ;
        RECT  84 274.916 84.024 275 ;
    END
  END dbg_pc_o[12]
  PIN dbg_pc_o[13]
    DIRECTION OUTPUT ;
    USE SIGNAL ;
    PORT
      LAYER M5 ;
        RECT  84.192 274.916 84.216 275 ;
    END
  END dbg_pc_o[13]
  PIN dbg_pc_o[14]
    DIRECTION OUTPUT ;
    USE SIGNAL ;
    PORT
      LAYER M5 ;
        RECT  84.96 274.916 84.984 275 ;
    END
  END dbg_pc_o[14]
  PIN dbg_pc_o[15]
    DIRECTION OUTPUT ;
    USE SIGNAL ;
    PORT
      LAYER M5 ;
        RECT  83.712 274.916 83.736 275 ;
    END
  END dbg_pc_o[15]
  PIN dbg_pc_o[16]
    DIRECTION OUTPUT ;
    USE SIGNAL ;
    PORT
      LAYER M5 ;
        RECT  81.984 274.916 82.008 275 ;
    END
  END dbg_pc_o[16]
  PIN dbg_pc_o[17]
    DIRECTION OUTPUT ;
    USE SIGNAL ;
    PORT
      LAYER M5 ;
        RECT  83.424 274.916 83.448 275 ;
    END
  END dbg_pc_o[17]
  PIN dbg_pc_o[18]
    DIRECTION OUTPUT ;
    USE SIGNAL ;
    PORT
      LAYER M5 ;
        RECT  84.48 274.916 84.504 275 ;
    END
  END dbg_pc_o[18]
  PIN dbg_pc_o[19]
    DIRECTION OUTPUT ;
    USE SIGNAL ;
    PORT
      LAYER M5 ;
        RECT  82.272 274.916 82.296 275 ;
    END
  END dbg_pc_o[19]
  PIN dbg_pc_o[1]
    DIRECTION OUTPUT ;
    USE SIGNAL ;
    PORT
      LAYER M5 ;
        RECT  81.696 274.916 81.72 275 ;
    END
  END dbg_pc_o[1]
  PIN dbg_pc_o[20]
    DIRECTION OUTPUT ;
    USE SIGNAL ;
    PORT
      LAYER M5 ;
        RECT  83.616 274.916 83.64 275 ;
    END
  END dbg_pc_o[20]
  PIN dbg_pc_o[21]
    DIRECTION OUTPUT ;
    USE SIGNAL ;
    PORT
      LAYER M5 ;
        RECT  84.864 274.916 84.888 275 ;
    END
  END dbg_pc_o[21]
  PIN dbg_pc_o[22]
    DIRECTION OUTPUT ;
    USE SIGNAL ;
    PORT
      LAYER M5 ;
        RECT  84.384 274.916 84.408 275 ;
    END
  END dbg_pc_o[22]
  PIN dbg_pc_o[23]
    DIRECTION OUTPUT ;
    USE SIGNAL ;
    PORT
      LAYER M5 ;
        RECT  84.288 274.916 84.312 275 ;
    END
  END dbg_pc_o[23]
  PIN dbg_pc_o[24]
    DIRECTION OUTPUT ;
    USE SIGNAL ;
    PORT
      LAYER M5 ;
        RECT  84.096 274.916 84.12 275 ;
    END
  END dbg_pc_o[24]
  PIN dbg_pc_o[25]
    DIRECTION OUTPUT ;
    USE SIGNAL ;
    PORT
      LAYER M5 ;
        RECT  83.52 274.916 83.544 275 ;
    END
  END dbg_pc_o[25]
  PIN dbg_pc_o[26]
    DIRECTION OUTPUT ;
    USE SIGNAL ;
    PORT
      LAYER M5 ;
        RECT  83.328 274.916 83.352 275 ;
    END
  END dbg_pc_o[26]
  PIN dbg_pc_o[27]
    DIRECTION OUTPUT ;
    USE SIGNAL ;
    PORT
      LAYER M5 ;
        RECT  83.04 274.916 83.064 275 ;
    END
  END dbg_pc_o[27]
  PIN dbg_pc_o[28]
    DIRECTION OUTPUT ;
    USE SIGNAL ;
    PORT
      LAYER M5 ;
        RECT  84.768 274.916 84.792 275 ;
    END
  END dbg_pc_o[28]
  PIN dbg_pc_o[29]
    DIRECTION OUTPUT ;
    USE SIGNAL ;
    PORT
      LAYER M5 ;
        RECT  84.576 274.916 84.6 275 ;
    END
  END dbg_pc_o[29]
  PIN dbg_pc_o[2]
    DIRECTION OUTPUT ;
    USE SIGNAL ;
    PORT
      LAYER M5 ;
        RECT  85.056 274.916 85.08 275 ;
    END
  END dbg_pc_o[2]
  PIN dbg_pc_o[30]
    DIRECTION OUTPUT ;
    USE SIGNAL ;
    PORT
      LAYER M5 ;
        RECT  83.232 274.916 83.256 275 ;
    END
  END dbg_pc_o[30]
  PIN dbg_pc_o[31]
    DIRECTION OUTPUT ;
    USE SIGNAL ;
    PORT
      LAYER M5 ;
        RECT  83.808 274.916 83.832 275 ;
    END
  END dbg_pc_o[31]
  PIN dbg_pc_o[3]
    DIRECTION OUTPUT ;
    USE SIGNAL ;
    PORT
      LAYER M5 ;
        RECT  85.344 274.916 85.368 275 ;
    END
  END dbg_pc_o[3]
  PIN dbg_pc_o[4]
    DIRECTION OUTPUT ;
    USE SIGNAL ;
    PORT
      LAYER M5 ;
        RECT  85.152 274.916 85.176 275 ;
    END
  END dbg_pc_o[4]
  PIN dbg_pc_o[5]
    DIRECTION OUTPUT ;
    USE SIGNAL ;
    PORT
      LAYER M5 ;
        RECT  85.248 274.916 85.272 275 ;
    END
  END dbg_pc_o[5]
  PIN dbg_pc_o[6]
    DIRECTION OUTPUT ;
    USE SIGNAL ;
    PORT
      LAYER M5 ;
        RECT  83.136 274.916 83.16 275 ;
    END
  END dbg_pc_o[6]
  PIN dbg_pc_o[7]
    DIRECTION OUTPUT ;
    USE SIGNAL ;
    PORT
      LAYER M5 ;
        RECT  83.904 274.916 83.928 275 ;
    END
  END dbg_pc_o[7]
  PIN dbg_pc_o[8]
    DIRECTION OUTPUT ;
    USE SIGNAL ;
    PORT
      LAYER M5 ;
        RECT  81.312 274.916 81.336 275 ;
    END
  END dbg_pc_o[8]
  PIN dbg_pc_o[9]
    DIRECTION OUTPUT ;
    USE SIGNAL ;
    PORT
      LAYER M5 ;
        RECT  84.672 274.916 84.696 275 ;
    END
  END dbg_pc_o[9]
  PIN dbg_pc_we_i
    DIRECTION INPUT ;
    USE SIGNAL ;
    PORT
      LAYER M5 ;
        RECT  78.816 274.916 78.84 275 ;
    END
  END dbg_pc_we_i
  PIN dbg_rf_addr_i[0]
    DIRECTION INPUT ;
    USE SIGNAL ;
    PORT
      LAYER M5 ;
        RECT  67.776 274.916 67.8 275 ;
    END
  END dbg_rf_addr_i[0]
  PIN dbg_rf_addr_i[1]
    DIRECTION INPUT ;
    USE SIGNAL ;
    PORT
      LAYER M5 ;
        RECT  73.824 274.916 73.848 275 ;
    END
  END dbg_rf_addr_i[1]
  PIN dbg_rf_addr_i[2]
    DIRECTION INPUT ;
    USE SIGNAL ;
    PORT
      LAYER M5 ;
        RECT  67.68 274.916 67.704 275 ;
    END
  END dbg_rf_addr_i[2]
  PIN dbg_rf_addr_i[3]
    DIRECTION INPUT ;
    USE SIGNAL ;
    PORT
      LAYER M5 ;
        RECT  72 274.916 72.024 275 ;
    END
  END dbg_rf_addr_i[3]
  PIN dbg_rf_addr_i[4]
    DIRECTION INPUT ;
    USE SIGNAL ;
    PORT
      LAYER M5 ;
        RECT  75.264 274.916 75.288 275 ;
    END
  END dbg_rf_addr_i[4]
  PIN dbg_rf_rdata_o[0]
    DIRECTION OUTPUT ;
    USE SIGNAL ;
    PORT
      LAYER M5 ;
        RECT  79.392 274.916 79.416 275 ;
    END
  END dbg_rf_rdata_o[0]
  PIN dbg_rf_rdata_o[10]
    DIRECTION OUTPUT ;
    USE SIGNAL ;
    PORT
      LAYER M5 ;
        RECT  75.744 274.916 75.768 275 ;
    END
  END dbg_rf_rdata_o[10]
  PIN dbg_rf_rdata_o[11]
    DIRECTION OUTPUT ;
    USE SIGNAL ;
    PORT
      LAYER M5 ;
        RECT  77.472 274.916 77.496 275 ;
    END
  END dbg_rf_rdata_o[11]
  PIN dbg_rf_rdata_o[12]
    DIRECTION OUTPUT ;
    USE SIGNAL ;
    PORT
      LAYER M5 ;
        RECT  77.376 274.916 77.4 275 ;
    END
  END dbg_rf_rdata_o[12]
  PIN dbg_rf_rdata_o[13]
    DIRECTION OUTPUT ;
    USE SIGNAL ;
    PORT
      LAYER M5 ;
        RECT  77.568 274.916 77.592 275 ;
    END
  END dbg_rf_rdata_o[13]
  PIN dbg_rf_rdata_o[14]
    DIRECTION OUTPUT ;
    USE SIGNAL ;
    PORT
      LAYER M5 ;
        RECT  77.76 274.916 77.784 275 ;
    END
  END dbg_rf_rdata_o[14]
  PIN dbg_rf_rdata_o[15]
    DIRECTION OUTPUT ;
    USE SIGNAL ;
    PORT
      LAYER M5 ;
        RECT  76.512 274.916 76.536 275 ;
    END
  END dbg_rf_rdata_o[15]
  PIN dbg_rf_rdata_o[16]
    DIRECTION OUTPUT ;
    USE SIGNAL ;
    PORT
      LAYER M5 ;
        RECT  67.488 274.916 67.512 275 ;
    END
  END dbg_rf_rdata_o[16]
  PIN dbg_rf_rdata_o[17]
    DIRECTION OUTPUT ;
    USE SIGNAL ;
    PORT
      LAYER M5 ;
        RECT  76.608 274.916 76.632 275 ;
    END
  END dbg_rf_rdata_o[17]
  PIN dbg_rf_rdata_o[18]
    DIRECTION OUTPUT ;
    USE SIGNAL ;
    PORT
      LAYER M5 ;
        RECT  75.168 274.916 75.192 275 ;
    END
  END dbg_rf_rdata_o[18]
  PIN dbg_rf_rdata_o[19]
    DIRECTION OUTPUT ;
    USE SIGNAL ;
    PORT
      LAYER M5 ;
        RECT  75.84 274.916 75.864 275 ;
    END
  END dbg_rf_rdata_o[19]
  PIN dbg_rf_rdata_o[1]
    DIRECTION OUTPUT ;
    USE SIGNAL ;
    PORT
      LAYER M5 ;
        RECT  80.832 274.916 80.856 275 ;
    END
  END dbg_rf_rdata_o[1]
  PIN dbg_rf_rdata_o[20]
    DIRECTION OUTPUT ;
    USE SIGNAL ;
    PORT
      LAYER M5 ;
        RECT  76.224 274.916 76.248 275 ;
    END
  END dbg_rf_rdata_o[20]
  PIN dbg_rf_rdata_o[21]
    DIRECTION OUTPUT ;
    USE SIGNAL ;
    PORT
      LAYER M5 ;
        RECT  72.576 274.916 72.6 275 ;
    END
  END dbg_rf_rdata_o[21]
  PIN dbg_rf_rdata_o[22]
    DIRECTION OUTPUT ;
    USE SIGNAL ;
    PORT
      LAYER M5 ;
        RECT  74.88 274.916 74.904 275 ;
    END
  END dbg_rf_rdata_o[22]
  PIN dbg_rf_rdata_o[23]
    DIRECTION OUTPUT ;
    USE SIGNAL ;
    PORT
      LAYER M5 ;
        RECT  73.728 274.916 73.752 275 ;
    END
  END dbg_rf_rdata_o[23]
  PIN dbg_rf_rdata_o[24]
    DIRECTION OUTPUT ;
    USE SIGNAL ;
    PORT
      LAYER M5 ;
        RECT  72.672 274.916 72.696 275 ;
    END
  END dbg_rf_rdata_o[24]
  PIN dbg_rf_rdata_o[25]
    DIRECTION OUTPUT ;
    USE SIGNAL ;
    PORT
      LAYER M5 ;
        RECT  72.096 274.916 72.12 275 ;
    END
  END dbg_rf_rdata_o[25]
  PIN dbg_rf_rdata_o[26]
    DIRECTION OUTPUT ;
    USE SIGNAL ;
    PORT
      LAYER M5 ;
        RECT  76.32 274.916 76.344 275 ;
    END
  END dbg_rf_rdata_o[26]
  PIN dbg_rf_rdata_o[27]
    DIRECTION OUTPUT ;
    USE SIGNAL ;
    PORT
      LAYER M5 ;
        RECT  73.44 274.916 73.464 275 ;
    END
  END dbg_rf_rdata_o[27]
  PIN dbg_rf_rdata_o[28]
    DIRECTION OUTPUT ;
    USE SIGNAL ;
    PORT
      LAYER M5 ;
        RECT  73.344 274.916 73.368 275 ;
    END
  END dbg_rf_rdata_o[28]
  PIN dbg_rf_rdata_o[29]
    DIRECTION OUTPUT ;
    USE SIGNAL ;
    PORT
      LAYER M5 ;
        RECT  74.016 274.916 74.04 275 ;
    END
  END dbg_rf_rdata_o[29]
  PIN dbg_rf_rdata_o[2]
    DIRECTION OUTPUT ;
    USE SIGNAL ;
    PORT
      LAYER M5 ;
        RECT  73.056 274.916 73.08 275 ;
    END
  END dbg_rf_rdata_o[2]
  PIN dbg_rf_rdata_o[30]
    DIRECTION OUTPUT ;
    USE SIGNAL ;
    PORT
      LAYER M5 ;
        RECT  75.456 274.916 75.48 275 ;
    END
  END dbg_rf_rdata_o[30]
  PIN dbg_rf_rdata_o[31]
    DIRECTION OUTPUT ;
    USE SIGNAL ;
    PORT
      LAYER M5 ;
        RECT  76.704 274.916 76.728 275 ;
    END
  END dbg_rf_rdata_o[31]
  PIN dbg_rf_rdata_o[3]
    DIRECTION OUTPUT ;
    USE SIGNAL ;
    PORT
      LAYER M5 ;
        RECT  76.8 274.916 76.824 275 ;
    END
  END dbg_rf_rdata_o[3]
  PIN dbg_rf_rdata_o[4]
    DIRECTION OUTPUT ;
    USE SIGNAL ;
    PORT
      LAYER M5 ;
        RECT  78.048 274.916 78.072 275 ;
    END
  END dbg_rf_rdata_o[4]
  PIN dbg_rf_rdata_o[5]
    DIRECTION OUTPUT ;
    USE SIGNAL ;
    PORT
      LAYER M5 ;
        RECT  73.536 274.916 73.56 275 ;
    END
  END dbg_rf_rdata_o[5]
  PIN dbg_rf_rdata_o[6]
    DIRECTION OUTPUT ;
    USE SIGNAL ;
    PORT
      LAYER M5 ;
        RECT  73.632 274.916 73.656 275 ;
    END
  END dbg_rf_rdata_o[6]
  PIN dbg_rf_rdata_o[7]
    DIRECTION OUTPUT ;
    USE SIGNAL ;
    PORT
      LAYER M5 ;
        RECT  76.128 274.916 76.152 275 ;
    END
  END dbg_rf_rdata_o[7]
  PIN dbg_rf_rdata_o[8]
    DIRECTION OUTPUT ;
    USE SIGNAL ;
    PORT
      LAYER M5 ;
        RECT  77.664 274.916 77.688 275 ;
    END
  END dbg_rf_rdata_o[8]
  PIN dbg_rf_rdata_o[9]
    DIRECTION OUTPUT ;
    USE SIGNAL ;
    PORT
      LAYER M5 ;
        RECT  72.864 274.916 72.888 275 ;
    END
  END dbg_rf_rdata_o[9]
  PIN dbg_rf_we_i
    DIRECTION INPUT ;
    USE SIGNAL ;
    PORT
      LAYER M5 ;
        RECT  72.768 274.916 72.792 275 ;
    END
  END dbg_rf_we_i
  PIN dbg_wdata_i[0]
    DIRECTION INPUT ;
    USE SIGNAL ;
    PORT
      LAYER M5 ;
        RECT  82.08 274.916 82.104 275 ;
    END
  END dbg_wdata_i[0]
  PIN dbg_wdata_i[10]
    DIRECTION INPUT ;
    USE SIGNAL ;
    PORT
      LAYER M5 ;
        RECT  79.2 274.916 79.224 275 ;
    END
  END dbg_wdata_i[10]
  PIN dbg_wdata_i[11]
    DIRECTION INPUT ;
    USE SIGNAL ;
    PORT
      LAYER M5 ;
        RECT  78.624 274.916 78.648 275 ;
    END
  END dbg_wdata_i[11]
  PIN dbg_wdata_i[12]
    DIRECTION INPUT ;
    USE SIGNAL ;
    PORT
      LAYER M5 ;
        RECT  78.144 274.916 78.168 275 ;
    END
  END dbg_wdata_i[12]
  PIN dbg_wdata_i[13]
    DIRECTION INPUT ;
    USE SIGNAL ;
    PORT
      LAYER M5 ;
        RECT  79.296 274.916 79.32 275 ;
    END
  END dbg_wdata_i[13]
  PIN dbg_wdata_i[14]
    DIRECTION INPUT ;
    USE SIGNAL ;
    PORT
      LAYER M5 ;
        RECT  80.544 274.916 80.568 275 ;
    END
  END dbg_wdata_i[14]
  PIN dbg_wdata_i[15]
    DIRECTION INPUT ;
    USE SIGNAL ;
    PORT
      LAYER M5 ;
        RECT  80.352 274.916 80.376 275 ;
    END
  END dbg_wdata_i[15]
  PIN dbg_wdata_i[16]
    DIRECTION INPUT ;
    USE SIGNAL ;
    PORT
      LAYER M5 ;
        RECT  80.928 274.916 80.952 275 ;
    END
  END dbg_wdata_i[16]
  PIN dbg_wdata_i[17]
    DIRECTION INPUT ;
    USE SIGNAL ;
    PORT
      LAYER M5 ;
        RECT  79.776 274.916 79.8 275 ;
    END
  END dbg_wdata_i[17]
  PIN dbg_wdata_i[18]
    DIRECTION INPUT ;
    USE SIGNAL ;
    PORT
      LAYER M5 ;
        RECT  80.736 274.916 80.76 275 ;
    END
  END dbg_wdata_i[18]
  PIN dbg_wdata_i[19]
    DIRECTION INPUT ;
    USE SIGNAL ;
    PORT
      LAYER M5 ;
        RECT  81.024 274.916 81.048 275 ;
    END
  END dbg_wdata_i[19]
  PIN dbg_wdata_i[1]
    DIRECTION INPUT ;
    USE SIGNAL ;
    PORT
      LAYER M5 ;
        RECT  80.064 274.916 80.088 275 ;
    END
  END dbg_wdata_i[1]
  PIN dbg_wdata_i[20]
    DIRECTION INPUT ;
    USE SIGNAL ;
    PORT
      LAYER M5 ;
        RECT  81.12 274.916 81.144 275 ;
    END
  END dbg_wdata_i[20]
  PIN dbg_wdata_i[21]
    DIRECTION INPUT ;
    USE SIGNAL ;
    PORT
      LAYER M5 ;
        RECT  81.216 274.916 81.24 275 ;
    END
  END dbg_wdata_i[21]
  PIN dbg_wdata_i[22]
    DIRECTION INPUT ;
    USE SIGNAL ;
    PORT
      LAYER M5 ;
        RECT  81.888 274.916 81.912 275 ;
    END
  END dbg_wdata_i[22]
  PIN dbg_wdata_i[23]
    DIRECTION INPUT ;
    USE SIGNAL ;
    PORT
      LAYER M5 ;
        RECT  81.408 274.916 81.432 275 ;
    END
  END dbg_wdata_i[23]
  PIN dbg_wdata_i[24]
    DIRECTION INPUT ;
    USE SIGNAL ;
    PORT
      LAYER M5 ;
        RECT  82.176 274.916 82.2 275 ;
    END
  END dbg_wdata_i[24]
  PIN dbg_wdata_i[25]
    DIRECTION INPUT ;
    USE SIGNAL ;
    PORT
      LAYER M5 ;
        RECT  82.656 274.916 82.68 275 ;
    END
  END dbg_wdata_i[25]
  PIN dbg_wdata_i[26]
    DIRECTION INPUT ;
    USE SIGNAL ;
    PORT
      LAYER M5 ;
        RECT  82.368 274.916 82.392 275 ;
    END
  END dbg_wdata_i[26]
  PIN dbg_wdata_i[27]
    DIRECTION INPUT ;
    USE SIGNAL ;
    PORT
      LAYER M5 ;
        RECT  82.464 274.916 82.488 275 ;
    END
  END dbg_wdata_i[27]
  PIN dbg_wdata_i[28]
    DIRECTION INPUT ;
    USE SIGNAL ;
    PORT
      LAYER M5 ;
        RECT  81.504 274.916 81.528 275 ;
    END
  END dbg_wdata_i[28]
  PIN dbg_wdata_i[29]
    DIRECTION INPUT ;
    USE SIGNAL ;
    PORT
      LAYER M5 ;
        RECT  82.56 274.916 82.584 275 ;
    END
  END dbg_wdata_i[29]
  PIN dbg_wdata_i[2]
    DIRECTION INPUT ;
    USE SIGNAL ;
    PORT
      LAYER M5 ;
        RECT  78.336 274.916 78.36 275 ;
    END
  END dbg_wdata_i[2]
  PIN dbg_wdata_i[30]
    DIRECTION INPUT ;
    USE SIGNAL ;
    PORT
      LAYER M5 ;
        RECT  81.6 274.916 81.624 275 ;
    END
  END dbg_wdata_i[30]
  PIN dbg_wdata_i[31]
    DIRECTION INPUT ;
    USE SIGNAL ;
    PORT
      LAYER M5 ;
        RECT  81.792 274.916 81.816 275 ;
    END
  END dbg_wdata_i[31]
  PIN dbg_wdata_i[3]
    DIRECTION INPUT ;
    USE SIGNAL ;
    PORT
      LAYER M5 ;
        RECT  74.976 274.916 75 275 ;
    END
  END dbg_wdata_i[3]
  PIN dbg_wdata_i[4]
    DIRECTION INPUT ;
    USE SIGNAL ;
    PORT
      LAYER M5 ;
        RECT  80.64 274.916 80.664 275 ;
    END
  END dbg_wdata_i[4]
  PIN dbg_wdata_i[5]
    DIRECTION INPUT ;
    USE SIGNAL ;
    PORT
      LAYER M5 ;
        RECT  78.432 274.916 78.456 275 ;
    END
  END dbg_wdata_i[5]
  PIN dbg_wdata_i[6]
    DIRECTION INPUT ;
    USE SIGNAL ;
    PORT
      LAYER M5 ;
        RECT  79.68 274.916 79.704 275 ;
    END
  END dbg_wdata_i[6]
  PIN dbg_wdata_i[7]
    DIRECTION INPUT ;
    USE SIGNAL ;
    PORT
      LAYER M5 ;
        RECT  79.584 274.916 79.608 275 ;
    END
  END dbg_wdata_i[7]
  PIN dbg_wdata_i[8]
    DIRECTION INPUT ;
    USE SIGNAL ;
    PORT
      LAYER M5 ;
        RECT  80.448 274.916 80.472 275 ;
    END
  END dbg_wdata_i[8]
  PIN dbg_wdata_i[9]
    DIRECTION INPUT ;
    USE SIGNAL ;
    PORT
      LAYER M5 ;
        RECT  78.528 274.916 78.552 275 ;
    END
  END dbg_wdata_i[9]
  PIN events_o[0]
    DIRECTION OUTPUT ;
    USE SIGNAL ;
    PORT
      LAYER M4 ;
        RECT  0 227.616 0.084 227.64 ;
    END
  END events_o[0]
  PIN events_o[10]
    DIRECTION OUTPUT ;
    USE SIGNAL ;
    PORT
      LAYER M5 ;
        RECT  122.016 274.916 122.04 275 ;
    END
  END events_o[10]
  PIN events_o[11]
    DIRECTION OUTPUT ;
    USE SIGNAL ;
    PORT
      LAYER M5 ;
        RECT  110.016 274.916 110.04 275 ;
    END
  END events_o[11]
  PIN events_o[12]
    DIRECTION OUTPUT ;
    USE SIGNAL ;
    PORT
      LAYER M5 ;
        RECT  107.904 274.916 107.928 275 ;
    END
  END events_o[12]
  PIN events_o[13]
    DIRECTION OUTPUT ;
    USE SIGNAL ;
    PORT
      LAYER M5 ;
        RECT  108.384 274.916 108.408 275 ;
    END
  END events_o[13]
  PIN events_o[14]
    DIRECTION OUTPUT ;
    USE SIGNAL ;
    PORT
      LAYER M5 ;
        RECT  108.096 274.916 108.12 275 ;
    END
  END events_o[14]
  PIN events_o[15]
    DIRECTION OUTPUT ;
    USE SIGNAL ;
    PORT
      LAYER M5 ;
        RECT  108.672 274.916 108.696 275 ;
    END
  END events_o[15]
  PIN events_o[1]
    DIRECTION OUTPUT ;
    USE SIGNAL ;
    PORT
      LAYER M5 ;
        RECT  63.168 274.916 63.192 275 ;
    END
  END events_o[1]
  PIN events_o[2]
    DIRECTION OUTPUT ;
    USE SIGNAL ;
    PORT
      LAYER M4 ;
        RECT  0 218.496 0.084 218.52 ;
    END
  END events_o[2]
  PIN events_o[3]
    DIRECTION OUTPUT ;
    USE SIGNAL ;
    PORT
      LAYER M5 ;
        RECT  63.072 274.916 63.096 275 ;
    END
  END events_o[3]
  PIN events_o[4]
    DIRECTION OUTPUT ;
    USE SIGNAL ;
    PORT
      LAYER M5 ;
        RECT  59.52 274.916 59.544 275 ;
    END
  END events_o[4]
  PIN events_o[5]
    DIRECTION OUTPUT ;
    USE SIGNAL ;
    PORT
      LAYER M4 ;
        RECT  0 217.824 0.084 217.848 ;
    END
  END events_o[5]
  PIN events_o[6]
    DIRECTION OUTPUT ;
    USE SIGNAL ;
    PORT
      LAYER M4 ;
        RECT  0 221.952 0.084 221.976 ;
    END
  END events_o[6]
  PIN events_o[7]
    DIRECTION OUTPUT ;
    USE SIGNAL ;
    PORT
      LAYER M5 ;
        RECT  63.744 274.916 63.768 275 ;
    END
  END events_o[7]
  PIN events_o[8]
    DIRECTION OUTPUT ;
    USE SIGNAL ;
    PORT
      LAYER M5 ;
        RECT  108.768 274.916 108.792 275 ;
    END
  END events_o[8]
  PIN events_o[9]
    DIRECTION OUTPUT ;
    USE SIGNAL ;
    PORT
      LAYER M5 ;
        RECT  110.784 274.916 110.808 275 ;
    END
  END events_o[9]
  PIN flush_done_o
    DIRECTION OUTPUT ;
    USE SIGNAL ;
    PORT
      LAYER M5 ;
        RECT  103.008 274.916 103.032 275 ;
    END
  END flush_done_o
  PIN flush_i
    DIRECTION INPUT ;
    USE SIGNAL ;
    PORT
      LAYER M5 ;
        RECT  63.84 274.916 63.864 275 ;
    END
  END flush_i
  PIN halt_req_i
    DIRECTION INPUT ;
    USE SIGNAL ;
    PORT
      LAYER M5 ;
        RECT  74.4 274.916 74.424 275 ;
    END
  END halt_req_i
  PIN halted_o
    DIRECTION OUTPUT ;
    USE SIGNAL ;
    PORT
      LAYER M5 ;
        RECT  72.48 274.916 72.504 275 ;
    END
  END halted_o
  PIN hart_id_i[0]
    DIRECTION INPUT ;
    USE SIGNAL ;
    PORT
      LAYER M5 ;
        RECT  74.112 274.916 74.136 275 ;
    END
  END hart_id_i[0]
  PIN hart_id_i[10]
    DIRECTION INPUT ;
    USE SIGNAL ;
    PORT
      LAYER M5 ;
        RECT  77.184 274.916 77.208 275 ;
    END
  END hart_id_i[10]
  PIN hart_id_i[11]
    DIRECTION INPUT ;
    USE SIGNAL ;
    PORT
      LAYER M5 ;
        RECT  72.384 274.916 72.408 275 ;
    END
  END hart_id_i[11]
  PIN hart_id_i[12]
    DIRECTION INPUT ;
    USE SIGNAL ;
    PORT
      LAYER M5 ;
        RECT  80.256 274.916 80.28 275 ;
    END
  END hart_id_i[12]
  PIN hart_id_i[13]
    DIRECTION INPUT ;
    USE SIGNAL ;
    PORT
      LAYER M5 ;
        RECT  74.208 274.916 74.232 275 ;
    END
  END hart_id_i[13]
  PIN hart_id_i[14]
    DIRECTION INPUT ;
    USE SIGNAL ;
    PORT
      LAYER M5 ;
        RECT  79.968 274.916 79.992 275 ;
    END
  END hart_id_i[14]
  PIN hart_id_i[15]
    DIRECTION INPUT ;
    USE SIGNAL ;
    PORT
      LAYER M5 ;
        RECT  74.496 274.916 74.52 275 ;
    END
  END hart_id_i[15]
  PIN hart_id_i[16]
    DIRECTION INPUT ;
    USE SIGNAL ;
    PORT
      LAYER M5 ;
        RECT  75.072 274.916 75.096 275 ;
    END
  END hart_id_i[16]
  PIN hart_id_i[17]
    DIRECTION INPUT ;
    USE SIGNAL ;
    PORT
      LAYER M5 ;
        RECT  76.416 274.916 76.44 275 ;
    END
  END hart_id_i[17]
  PIN hart_id_i[18]
    DIRECTION INPUT ;
    USE SIGNAL ;
    PORT
      LAYER M5 ;
        RECT  78.24 274.916 78.264 275 ;
    END
  END hart_id_i[18]
  PIN hart_id_i[19]
    DIRECTION INPUT ;
    USE SIGNAL ;
    PORT
      LAYER M5 ;
        RECT  74.592 274.916 74.616 275 ;
    END
  END hart_id_i[19]
  PIN hart_id_i[1]
    DIRECTION INPUT ;
    USE SIGNAL ;
    PORT
      LAYER M5 ;
        RECT  77.28 274.916 77.304 275 ;
    END
  END hart_id_i[1]
  PIN hart_id_i[20]
    DIRECTION INPUT ;
    USE SIGNAL ;
    PORT
      LAYER M5 ;
        RECT  73.92 274.916 73.944 275 ;
    END
  END hart_id_i[20]
  PIN hart_id_i[21]
    DIRECTION INPUT ;
    USE SIGNAL ;
    PORT
      LAYER M5 ;
        RECT  75.36 274.916 75.384 275 ;
    END
  END hart_id_i[21]
  PIN hart_id_i[22]
    DIRECTION INPUT ;
    USE SIGNAL ;
    PORT
      LAYER M5 ;
        RECT  79.104 274.916 79.128 275 ;
    END
  END hart_id_i[22]
  PIN hart_id_i[23]
    DIRECTION INPUT ;
    USE SIGNAL ;
    PORT
      LAYER M5 ;
        RECT  76.992 274.916 77.016 275 ;
    END
  END hart_id_i[23]
  PIN hart_id_i[24]
    DIRECTION INPUT ;
    USE SIGNAL ;
    PORT
      LAYER M5 ;
        RECT  74.784 274.916 74.808 275 ;
    END
  END hart_id_i[24]
  PIN hart_id_i[25]
    DIRECTION INPUT ;
    USE SIGNAL ;
    PORT
      LAYER M5 ;
        RECT  76.032 274.916 76.056 275 ;
    END
  END hart_id_i[25]
  PIN hart_id_i[26]
    DIRECTION INPUT ;
    USE SIGNAL ;
    PORT
      LAYER M5 ;
        RECT  76.896 274.916 76.92 275 ;
    END
  END hart_id_i[26]
  PIN hart_id_i[27]
    DIRECTION INPUT ;
    USE SIGNAL ;
    PORT
      LAYER M5 ;
        RECT  78.912 274.916 78.936 275 ;
    END
  END hart_id_i[27]
  PIN hart_id_i[28]
    DIRECTION INPUT ;
    USE SIGNAL ;
    PORT
      LAYER M5 ;
        RECT  70.56 274.916 70.584 275 ;
    END
  END hart_id_i[28]
  PIN hart_id_i[29]
    DIRECTION INPUT ;
    USE SIGNAL ;
    PORT
      LAYER M5 ;
        RECT  77.856 274.916 77.88 275 ;
    END
  END hart_id_i[29]
  PIN hart_id_i[2]
    DIRECTION INPUT ;
    USE SIGNAL ;
    PORT
      LAYER M5 ;
        RECT  80.16 274.916 80.184 275 ;
    END
  END hart_id_i[2]
  PIN hart_id_i[30]
    DIRECTION INPUT ;
    USE SIGNAL ;
    PORT
      LAYER M5 ;
        RECT  79.872 274.916 79.896 275 ;
    END
  END hart_id_i[30]
  PIN hart_id_i[31]
    DIRECTION INPUT ;
    USE SIGNAL ;
    PORT
      LAYER M5 ;
        RECT  75.936 274.916 75.96 275 ;
    END
  END hart_id_i[31]
  PIN hart_id_i[3]
    DIRECTION INPUT ;
    USE SIGNAL ;
    PORT
      LAYER M5 ;
        RECT  79.488 274.916 79.512 275 ;
    END
  END hart_id_i[3]
  PIN hart_id_i[4]
    DIRECTION INPUT ;
    USE SIGNAL ;
    PORT
      LAYER M5 ;
        RECT  75.648 274.916 75.672 275 ;
    END
  END hart_id_i[4]
  PIN hart_id_i[5]
    DIRECTION INPUT ;
    USE SIGNAL ;
    PORT
      LAYER M5 ;
        RECT  74.304 274.916 74.328 275 ;
    END
  END hart_id_i[5]
  PIN hart_id_i[6]
    DIRECTION INPUT ;
    USE SIGNAL ;
    PORT
      LAYER M5 ;
        RECT  77.088 274.916 77.112 275 ;
    END
  END hart_id_i[6]
  PIN hart_id_i[7]
    DIRECTION INPUT ;
    USE SIGNAL ;
    PORT
      LAYER M5 ;
        RECT  70.272 274.916 70.296 275 ;
    END
  END hart_id_i[7]
  PIN hart_id_i[8]
    DIRECTION INPUT ;
    USE SIGNAL ;
    PORT
      LAYER M5 ;
        RECT  78.72 274.916 78.744 275 ;
    END
  END hart_id_i[8]
  PIN hart_id_i[9]
    DIRECTION INPUT ;
    USE SIGNAL ;
    PORT
      LAYER M5 ;
        RECT  77.952 274.916 77.976 275 ;
    END
  END hart_id_i[9]
  PIN irq_external_i
    DIRECTION INPUT ;
    USE SIGNAL ;
    PORT
      LAYER M5 ;
        RECT  68.16 274.916 68.184 275 ;
    END
  END irq_external_i
  PIN irq_software_i
    DIRECTION INPUT ;
    USE SIGNAL ;
    PORT
      LAYER M5 ;
        RECT  70.08 274.916 70.104 275 ;
    END
  END irq_software_i
  PIN irq_timer_i
    DIRECTION INPUT ;
    USE SIGNAL ;
    PORT
      LAYER M5 ;
        RECT  75.552 274.916 75.576 275 ;
    END
  END irq_timer_i
  PIN l1_clk_en_i
    DIRECTION INPUT ;
    USE SIGNAL ;
    PORT
      LAYER M5 ;
        RECT  67.872 274.916 67.896 275 ;
    END
  END l1_clk_en_i
  PIN retire_o
    DIRECTION OUTPUT ;
    USE SIGNAL ;
    PORT
      LAYER M5 ;
        RECT  74.688 274.916 74.712 275 ;
    END
  END retire_o
  PIN rst_ni
    DIRECTION INPUT ;
    USE SIGNAL ;
    PORT
      LAYER M4 ;
        RECT  161.916 234.528 162 234.552 ;
    END
  END rst_ni
  PIN snoop_addr_i[0]
    DIRECTION INPUT ;
    USE SIGNAL ;
    PORT
      LAYER M4 ;
        RECT  161.916 249.888 162 249.912 ;
    END
  END snoop_addr_i[0]
  PIN snoop_addr_i[10]
    DIRECTION INPUT ;
    USE SIGNAL ;
    PORT
      LAYER M5 ;
        RECT  103.584 274.916 103.608 275 ;
    END
  END snoop_addr_i[10]
  PIN snoop_addr_i[11]
    DIRECTION INPUT ;
    USE SIGNAL ;
    PORT
      LAYER M5 ;
        RECT  103.488 274.916 103.512 275 ;
    END
  END snoop_addr_i[11]
  PIN snoop_addr_i[12]
    DIRECTION INPUT ;
    USE SIGNAL ;
    PORT
      LAYER M5 ;
        RECT  97.248 274.916 97.272 275 ;
    END
  END snoop_addr_i[12]
  PIN snoop_addr_i[13]
    DIRECTION INPUT ;
    USE SIGNAL ;
    PORT
      LAYER M5 ;
        RECT  106.56 274.916 106.584 275 ;
    END
  END snoop_addr_i[13]
  PIN snoop_addr_i[14]
    DIRECTION INPUT ;
    USE SIGNAL ;
    PORT
      LAYER M5 ;
        RECT  106.08 274.916 106.104 275 ;
    END
  END snoop_addr_i[14]
  PIN snoop_addr_i[15]
    DIRECTION INPUT ;
    USE SIGNAL ;
    PORT
      LAYER M5 ;
        RECT  105.6 274.916 105.624 275 ;
    END
  END snoop_addr_i[15]
  PIN snoop_addr_i[16]
    DIRECTION INPUT ;
    USE SIGNAL ;
    PORT
      LAYER M5 ;
        RECT  106.368 274.916 106.392 275 ;
    END
  END snoop_addr_i[16]
  PIN snoop_addr_i[17]
    DIRECTION INPUT ;
    USE SIGNAL ;
    PORT
      LAYER M5 ;
        RECT  106.464 274.916 106.488 275 ;
    END
  END snoop_addr_i[17]
  PIN snoop_addr_i[18]
    DIRECTION INPUT ;
    USE SIGNAL ;
    PORT
      LAYER M5 ;
        RECT  105.888 274.916 105.912 275 ;
    END
  END snoop_addr_i[18]
  PIN snoop_addr_i[19]
    DIRECTION INPUT ;
    USE SIGNAL ;
    PORT
      LAYER M5 ;
        RECT  105.024 274.916 105.048 275 ;
    END
  END snoop_addr_i[19]
  PIN snoop_addr_i[1]
    DIRECTION INPUT ;
    USE SIGNAL ;
    PORT
      LAYER M4 ;
        RECT  161.916 249.984 162 250.008 ;
    END
  END snoop_addr_i[1]
  PIN snoop_addr_i[20]
    DIRECTION INPUT ;
    USE SIGNAL ;
    PORT
      LAYER M5 ;
        RECT  105.216 274.916 105.24 275 ;
    END
  END snoop_addr_i[20]
  PIN snoop_addr_i[21]
    DIRECTION INPUT ;
    USE SIGNAL ;
    PORT
      LAYER M5 ;
        RECT  105.12 274.916 105.144 275 ;
    END
  END snoop_addr_i[21]
  PIN snoop_addr_i[22]
    DIRECTION INPUT ;
    USE SIGNAL ;
    PORT
      LAYER M5 ;
        RECT  105.312 274.916 105.336 275 ;
    END
  END snoop_addr_i[22]
  PIN snoop_addr_i[23]
    DIRECTION INPUT ;
    USE SIGNAL ;
    PORT
      LAYER M5 ;
        RECT  105.792 274.916 105.816 275 ;
    END
  END snoop_addr_i[23]
  PIN snoop_addr_i[24]
    DIRECTION INPUT ;
    USE SIGNAL ;
    PORT
      LAYER M5 ;
        RECT  105.504 274.916 105.528 275 ;
    END
  END snoop_addr_i[24]
  PIN snoop_addr_i[25]
    DIRECTION INPUT ;
    USE SIGNAL ;
    PORT
      LAYER M5 ;
        RECT  106.176 274.916 106.2 275 ;
    END
  END snoop_addr_i[25]
  PIN snoop_addr_i[26]
    DIRECTION INPUT ;
    USE SIGNAL ;
    PORT
      LAYER M5 ;
        RECT  105.696 274.916 105.72 275 ;
    END
  END snoop_addr_i[26]
  PIN snoop_addr_i[27]
    DIRECTION INPUT ;
    USE SIGNAL ;
    PORT
      LAYER M5 ;
        RECT  106.272 274.916 106.296 275 ;
    END
  END snoop_addr_i[27]
  PIN snoop_addr_i[28]
    DIRECTION INPUT ;
    USE SIGNAL ;
    PORT
      LAYER M5 ;
        RECT  104.928 274.916 104.952 275 ;
    END
  END snoop_addr_i[28]
  PIN snoop_addr_i[29]
    DIRECTION INPUT ;
    USE SIGNAL ;
    PORT
      LAYER M5 ;
        RECT  105.408 274.916 105.432 275 ;
    END
  END snoop_addr_i[29]
  PIN snoop_addr_i[2]
    DIRECTION INPUT ;
    USE SIGNAL ;
    PORT
      LAYER M4 ;
        RECT  161.916 250.08 162 250.104 ;
    END
  END snoop_addr_i[2]
  PIN snoop_addr_i[30]
    DIRECTION INPUT ;
    USE SIGNAL ;
    PORT
      LAYER M5 ;
        RECT  105.984 274.916 106.008 275 ;
    END
  END snoop_addr_i[30]
  PIN snoop_addr_i[31]
    DIRECTION INPUT ;
    USE SIGNAL ;
    PORT
      LAYER M5 ;
        RECT  102.048 274.916 102.072 275 ;
    END
  END snoop_addr_i[31]
  PIN snoop_addr_i[3]
    DIRECTION INPUT ;
    USE SIGNAL ;
    PORT
      LAYER M4 ;
        RECT  161.916 250.176 162 250.2 ;
    END
  END snoop_addr_i[3]
  PIN snoop_addr_i[4]
    DIRECTION INPUT ;
    USE SIGNAL ;
    PORT
      LAYER M4 ;
        RECT  161.916 250.272 162 250.296 ;
    END
  END snoop_addr_i[4]
  PIN snoop_addr_i[5]
    DIRECTION INPUT ;
    USE SIGNAL ;
    PORT
      LAYER M5 ;
        RECT  96.576 274.916 96.6 275 ;
    END
  END snoop_addr_i[5]
  PIN snoop_addr_i[6]
    DIRECTION INPUT ;
    USE SIGNAL ;
    PORT
      LAYER M5 ;
        RECT  96 274.916 96.024 275 ;
    END
  END snoop_addr_i[6]
  PIN snoop_addr_i[7]
    DIRECTION INPUT ;
    USE SIGNAL ;
    PORT
      LAYER M5 ;
        RECT  103.392 274.916 103.416 275 ;
    END
  END snoop_addr_i[7]
  PIN snoop_addr_i[8]
    DIRECTION INPUT ;
    USE SIGNAL ;
    PORT
      LAYER M5 ;
        RECT  103.296 274.916 103.32 275 ;
    END
  END snoop_addr_i[8]
  PIN snoop_addr_i[9]
    DIRECTION INPUT ;
    USE SIGNAL ;
    PORT
      LAYER M5 ;
        RECT  103.2 274.916 103.224 275 ;
    END
  END snoop_addr_i[9]
  PIN snoop_data_o[0]
    DIRECTION OUTPUT ;
    USE SIGNAL ;
    PORT
      LAYER M4 ;
        RECT  0 218.592 0.084 218.616 ;
    END
  END snoop_data_o[0]
  PIN snoop_data_o[100]
    DIRECTION OUTPUT ;
    USE SIGNAL ;
    PORT
      LAYER M4 ;
        RECT  0 235.008 0.084 235.032 ;
    END
  END snoop_data_o[100]
  PIN snoop_data_o[101]
    DIRECTION OUTPUT ;
    USE SIGNAL ;
    PORT
      LAYER M4 ;
        RECT  0 235.2 0.084 235.224 ;
    END
  END snoop_data_o[101]
  PIN snoop_data_o[102]
    DIRECTION OUTPUT ;
    USE SIGNAL ;
    PORT
      LAYER M4 ;
        RECT  0 235.392 0.084 235.416 ;
    END
  END snoop_data_o[102]
  PIN snoop_data_o[103]
    DIRECTION OUTPUT ;
    USE SIGNAL ;
    PORT
      LAYER M4 ;
        RECT  0 221.472 0.084 221.496 ;
    END
  END snoop_data_o[103]
  PIN snoop_data_o[104]
    DIRECTION OUTPUT ;
    USE SIGNAL ;
    PORT
      LAYER M4 ;
        RECT  0 233.088 0.084 233.112 ;
    END
  END snoop_data_o[104]
  PIN snoop_data_o[105]
    DIRECTION OUTPUT ;
    USE SIGNAL ;
    PORT
      LAYER M4 ;
        RECT  0 219.456 0.084 219.48 ;
    END
  END snoop_data_o[105]
  PIN snoop_data_o[106]
    DIRECTION OUTPUT ;
    USE SIGNAL ;
    PORT
      LAYER M4 ;
        RECT  0 232.32 0.084 232.344 ;
    END
  END snoop_data_o[106]
  PIN snoop_data_o[107]
    DIRECTION OUTPUT ;
    USE SIGNAL ;
    PORT
      LAYER M4 ;
        RECT  0 218.688 0.084 218.712 ;
    END
  END snoop_data_o[107]
  PIN snoop_data_o[108]
    DIRECTION OUTPUT ;
    USE SIGNAL ;
    PORT
      LAYER M4 ;
        RECT  0 234.24 0.084 234.264 ;
    END
  END snoop_data_o[108]
  PIN snoop_data_o[109]
    DIRECTION OUTPUT ;
    USE SIGNAL ;
    PORT
      LAYER M4 ;
        RECT  0 232.992 0.084 233.016 ;
    END
  END snoop_data_o[109]
  PIN snoop_data_o[10]
    DIRECTION OUTPUT ;
    USE SIGNAL ;
    PORT
      LAYER M4 ;
        RECT  0 234.048 0.084 234.072 ;
    END
  END snoop_data_o[10]
  PIN snoop_data_o[110]
    DIRECTION OUTPUT ;
    USE SIGNAL ;
    PORT
      LAYER M4 ;
        RECT  0 230.88 0.084 230.904 ;
    END
  END snoop_data_o[110]
  PIN snoop_data_o[111]
    DIRECTION OUTPUT ;
    USE SIGNAL ;
    PORT
      LAYER M4 ;
        RECT  0 222.144 0.084 222.168 ;
    END
  END snoop_data_o[111]
  PIN snoop_data_o[112]
    DIRECTION OUTPUT ;
    USE SIGNAL ;
    PORT
      LAYER M4 ;
        RECT  0 230.688 0.084 230.712 ;
    END
  END snoop_data_o[112]
  PIN snoop_data_o[113]
    DIRECTION OUTPUT ;
    USE SIGNAL ;
    PORT
      LAYER M4 ;
        RECT  0 216.864 0.084 216.888 ;
    END
  END snoop_data_o[113]
  PIN snoop_data_o[114]
    DIRECTION OUTPUT ;
    USE SIGNAL ;
    PORT
      LAYER M4 ;
        RECT  0 233.952 0.084 233.976 ;
    END
  END snoop_data_o[114]
  PIN snoop_data_o[115]
    DIRECTION OUTPUT ;
    USE SIGNAL ;
    PORT
      LAYER M4 ;
        RECT  0 226.368 0.084 226.392 ;
    END
  END snoop_data_o[115]
  PIN snoop_data_o[116]
    DIRECTION OUTPUT ;
    USE SIGNAL ;
    PORT
      LAYER M4 ;
        RECT  0 219.168 0.084 219.192 ;
    END
  END snoop_data_o[116]
  PIN snoop_data_o[117]
    DIRECTION OUTPUT ;
    USE SIGNAL ;
    PORT
      LAYER M4 ;
        RECT  0 231.552 0.084 231.576 ;
    END
  END snoop_data_o[117]
  PIN snoop_data_o[118]
    DIRECTION OUTPUT ;
    USE SIGNAL ;
    PORT
      LAYER M4 ;
        RECT  0 223.008 0.084 223.032 ;
    END
  END snoop_data_o[118]
  PIN snoop_data_o[119]
    DIRECTION OUTPUT ;
    USE SIGNAL ;
    PORT
      LAYER M4 ;
        RECT  0 219.36 0.084 219.384 ;
    END
  END snoop_data_o[119]
  PIN snoop_data_o[11]
    DIRECTION OUTPUT ;
    USE SIGNAL ;
    PORT
      LAYER M4 ;
        RECT  0 228.768 0.084 228.792 ;
    END
  END snoop_data_o[11]
  PIN snoop_data_o[120]
    DIRECTION OUTPUT ;
    USE SIGNAL ;
    PORT
      LAYER M4 ;
        RECT  0 223.968 0.084 223.992 ;
    END
  END snoop_data_o[120]
  PIN snoop_data_o[121]
    DIRECTION OUTPUT ;
    USE SIGNAL ;
    PORT
      LAYER M4 ;
        RECT  0 227.712 0.084 227.736 ;
    END
  END snoop_data_o[121]
  PIN snoop_data_o[122]
    DIRECTION OUTPUT ;
    USE SIGNAL ;
    PORT
      LAYER M4 ;
        RECT  0 231.168 0.084 231.192 ;
    END
  END snoop_data_o[122]
  PIN snoop_data_o[123]
    DIRECTION OUTPUT ;
    USE SIGNAL ;
    PORT
      LAYER M4 ;
        RECT  0 223.872 0.084 223.896 ;
    END
  END snoop_data_o[123]
  PIN snoop_data_o[124]
    DIRECTION OUTPUT ;
    USE SIGNAL ;
    PORT
      LAYER M4 ;
        RECT  0 232.224 0.084 232.248 ;
    END
  END snoop_data_o[124]
  PIN snoop_data_o[125]
    DIRECTION OUTPUT ;
    USE SIGNAL ;
    PORT
      LAYER M4 ;
        RECT  0 221.664 0.084 221.688 ;
    END
  END snoop_data_o[125]
  PIN snoop_data_o[126]
    DIRECTION OUTPUT ;
    USE SIGNAL ;
    PORT
      LAYER M4 ;
        RECT  0 217.632 0.084 217.656 ;
    END
  END snoop_data_o[126]
  PIN snoop_data_o[127]
    DIRECTION OUTPUT ;
    USE SIGNAL ;
    PORT
      LAYER M4 ;
        RECT  0 225.504 0.084 225.528 ;
    END
  END snoop_data_o[127]
  PIN snoop_data_o[128]
    DIRECTION OUTPUT ;
    USE SIGNAL ;
    PORT
      LAYER M4 ;
        RECT  0 220.128 0.084 220.152 ;
    END
  END snoop_data_o[128]
  PIN snoop_data_o[129]
    DIRECTION OUTPUT ;
    USE SIGNAL ;
    PORT
      LAYER M4 ;
        RECT  0 218.4 0.084 218.424 ;
    END
  END snoop_data_o[129]
  PIN snoop_data_o[12]
    DIRECTION OUTPUT ;
    USE SIGNAL ;
    PORT
      LAYER M4 ;
        RECT  0 229.536 0.084 229.56 ;
    END
  END snoop_data_o[12]
  PIN snoop_data_o[130]
    DIRECTION OUTPUT ;
    USE SIGNAL ;
    PORT
      LAYER M4 ;
        RECT  0 217.152 0.084 217.176 ;
    END
  END snoop_data_o[130]
  PIN snoop_data_o[131]
    DIRECTION OUTPUT ;
    USE SIGNAL ;
    PORT
      LAYER M4 ;
        RECT  0 225.12 0.084 225.144 ;
    END
  END snoop_data_o[131]
  PIN snoop_data_o[132]
    DIRECTION OUTPUT ;
    USE SIGNAL ;
    PORT
      LAYER M4 ;
        RECT  0 223.104 0.084 223.128 ;
    END
  END snoop_data_o[132]
  PIN snoop_data_o[133]
    DIRECTION OUTPUT ;
    USE SIGNAL ;
    PORT
      LAYER M4 ;
        RECT  0 231.36 0.084 231.384 ;
    END
  END snoop_data_o[133]
  PIN snoop_data_o[134]
    DIRECTION OUTPUT ;
    USE SIGNAL ;
    PORT
      LAYER M4 ;
        RECT  0 232.512 0.084 232.536 ;
    END
  END snoop_data_o[134]
  PIN snoop_data_o[135]
    DIRECTION OUTPUT ;
    USE SIGNAL ;
    PORT
      LAYER M4 ;
        RECT  0 227.904 0.084 227.928 ;
    END
  END snoop_data_o[135]
  PIN snoop_data_o[136]
    DIRECTION OUTPUT ;
    USE SIGNAL ;
    PORT
      LAYER M4 ;
        RECT  0 225.024 0.084 225.048 ;
    END
  END snoop_data_o[136]
  PIN snoop_data_o[137]
    DIRECTION OUTPUT ;
    USE SIGNAL ;
    PORT
      LAYER M4 ;
        RECT  0 231.84 0.084 231.864 ;
    END
  END snoop_data_o[137]
  PIN snoop_data_o[138]
    DIRECTION OUTPUT ;
    USE SIGNAL ;
    PORT
      LAYER M4 ;
        RECT  0 220.32 0.084 220.344 ;
    END
  END snoop_data_o[138]
  PIN snoop_data_o[139]
    DIRECTION OUTPUT ;
    USE SIGNAL ;
    PORT
      LAYER M4 ;
        RECT  0 218.208 0.084 218.232 ;
    END
  END snoop_data_o[139]
  PIN snoop_data_o[13]
    DIRECTION OUTPUT ;
    USE SIGNAL ;
    PORT
      LAYER M4 ;
        RECT  0 229.824 0.084 229.848 ;
    END
  END snoop_data_o[13]
  PIN snoop_data_o[140]
    DIRECTION OUTPUT ;
    USE SIGNAL ;
    PORT
      LAYER M4 ;
        RECT  0 230.112 0.084 230.136 ;
    END
  END snoop_data_o[140]
  PIN snoop_data_o[141]
    DIRECTION OUTPUT ;
    USE SIGNAL ;
    PORT
      LAYER M4 ;
        RECT  0 218.016 0.084 218.04 ;
    END
  END snoop_data_o[141]
  PIN snoop_data_o[142]
    DIRECTION OUTPUT ;
    USE SIGNAL ;
    PORT
      LAYER M4 ;
        RECT  0 218.112 0.084 218.136 ;
    END
  END snoop_data_o[142]
  PIN snoop_data_o[143]
    DIRECTION OUTPUT ;
    USE SIGNAL ;
    PORT
      LAYER M4 ;
        RECT  0 232.032 0.084 232.056 ;
    END
  END snoop_data_o[143]
  PIN snoop_data_o[144]
    DIRECTION OUTPUT ;
    USE SIGNAL ;
    PORT
      LAYER M4 ;
        RECT  0 232.896 0.084 232.92 ;
    END
  END snoop_data_o[144]
  PIN snoop_data_o[145]
    DIRECTION OUTPUT ;
    USE SIGNAL ;
    PORT
      LAYER M4 ;
        RECT  0 228.576 0.084 228.6 ;
    END
  END snoop_data_o[145]
  PIN snoop_data_o[146]
    DIRECTION OUTPUT ;
    USE SIGNAL ;
    PORT
      LAYER M4 ;
        RECT  0 217.92 0.084 217.944 ;
    END
  END snoop_data_o[146]
  PIN snoop_data_o[147]
    DIRECTION OUTPUT ;
    USE SIGNAL ;
    PORT
      LAYER M4 ;
        RECT  0 220.224 0.084 220.248 ;
    END
  END snoop_data_o[147]
  PIN snoop_data_o[148]
    DIRECTION OUTPUT ;
    USE SIGNAL ;
    PORT
      LAYER M4 ;
        RECT  0 225.888 0.084 225.912 ;
    END
  END snoop_data_o[148]
  PIN snoop_data_o[149]
    DIRECTION OUTPUT ;
    USE SIGNAL ;
    PORT
      LAYER M4 ;
        RECT  0 221.76 0.084 221.784 ;
    END
  END snoop_data_o[149]
  PIN snoop_data_o[14]
    DIRECTION OUTPUT ;
    USE SIGNAL ;
    PORT
      LAYER M4 ;
        RECT  0 224.448 0.084 224.472 ;
    END
  END snoop_data_o[14]
  PIN snoop_data_o[150]
    DIRECTION OUTPUT ;
    USE SIGNAL ;
    PORT
      LAYER M4 ;
        RECT  0 226.56 0.084 226.584 ;
    END
  END snoop_data_o[150]
  PIN snoop_data_o[151]
    DIRECTION OUTPUT ;
    USE SIGNAL ;
    PORT
      LAYER M4 ;
        RECT  0 230.304 0.084 230.328 ;
    END
  END snoop_data_o[151]
  PIN snoop_data_o[152]
    DIRECTION OUTPUT ;
    USE SIGNAL ;
    PORT
      LAYER M4 ;
        RECT  0 226.272 0.084 226.296 ;
    END
  END snoop_data_o[152]
  PIN snoop_data_o[153]
    DIRECTION OUTPUT ;
    USE SIGNAL ;
    PORT
      LAYER M4 ;
        RECT  0 217.44 0.084 217.464 ;
    END
  END snoop_data_o[153]
  PIN snoop_data_o[154]
    DIRECTION OUTPUT ;
    USE SIGNAL ;
    PORT
      LAYER M4 ;
        RECT  0 226.176 0.084 226.2 ;
    END
  END snoop_data_o[154]
  PIN snoop_data_o[155]
    DIRECTION OUTPUT ;
    USE SIGNAL ;
    PORT
      LAYER M4 ;
        RECT  0 230.496 0.084 230.52 ;
    END
  END snoop_data_o[155]
  PIN snoop_data_o[156]
    DIRECTION OUTPUT ;
    USE SIGNAL ;
    PORT
      LAYER M4 ;
        RECT  0 223.68 0.084 223.704 ;
    END
  END snoop_data_o[156]
  PIN snoop_data_o[157]
    DIRECTION OUTPUT ;
    USE SIGNAL ;
    PORT
      LAYER M4 ;
        RECT  0 229.056 0.084 229.08 ;
    END
  END snoop_data_o[157]
  PIN snoop_data_o[158]
    DIRECTION OUTPUT ;
    USE SIGNAL ;
    PORT
      LAYER M4 ;
        RECT  0 229.92 0.084 229.944 ;
    END
  END snoop_data_o[158]
  PIN snoop_data_o[159]
    DIRECTION OUTPUT ;
    USE SIGNAL ;
    PORT
      LAYER M4 ;
        RECT  0 228.96 0.084 228.984 ;
    END
  END snoop_data_o[159]
  PIN snoop_data_o[15]
    DIRECTION OUTPUT ;
    USE SIGNAL ;
    PORT
      LAYER M4 ;
        RECT  0 231.072 0.084 231.096 ;
    END
  END snoop_data_o[15]
  PIN snoop_data_o[160]
    DIRECTION OUTPUT ;
    USE SIGNAL ;
    PORT
      LAYER M4 ;
        RECT  0 219.648 0.084 219.672 ;
    END
  END snoop_data_o[160]
  PIN snoop_data_o[161]
    DIRECTION OUTPUT ;
    USE SIGNAL ;
    PORT
      LAYER M4 ;
        RECT  0 229.344 0.084 229.368 ;
    END
  END snoop_data_o[161]
  PIN snoop_data_o[162]
    DIRECTION OUTPUT ;
    USE SIGNAL ;
    PORT
      LAYER M4 ;
        RECT  0 231.264 0.084 231.288 ;
    END
  END snoop_data_o[162]
  PIN snoop_data_o[163]
    DIRECTION OUTPUT ;
    USE SIGNAL ;
    PORT
      LAYER M4 ;
        RECT  0 225.984 0.084 226.008 ;
    END
  END snoop_data_o[163]
  PIN snoop_data_o[164]
    DIRECTION OUTPUT ;
    USE SIGNAL ;
    PORT
      LAYER M4 ;
        RECT  0 219.84 0.084 219.864 ;
    END
  END snoop_data_o[164]
  PIN snoop_data_o[165]
    DIRECTION OUTPUT ;
    USE SIGNAL ;
    PORT
      LAYER M4 ;
        RECT  0 231.456 0.084 231.48 ;
    END
  END snoop_data_o[165]
  PIN snoop_data_o[166]
    DIRECTION OUTPUT ;
    USE SIGNAL ;
    PORT
      LAYER M4 ;
        RECT  0 224.736 0.084 224.76 ;
    END
  END snoop_data_o[166]
  PIN snoop_data_o[167]
    DIRECTION OUTPUT ;
    USE SIGNAL ;
    PORT
      LAYER M4 ;
        RECT  0 217.536 0.084 217.56 ;
    END
  END snoop_data_o[167]
  PIN snoop_data_o[168]
    DIRECTION OUTPUT ;
    USE SIGNAL ;
    PORT
      LAYER M4 ;
        RECT  0 226.944 0.084 226.968 ;
    END
  END snoop_data_o[168]
  PIN snoop_data_o[169]
    DIRECTION OUTPUT ;
    USE SIGNAL ;
    PORT
      LAYER M4 ;
        RECT  0 221.568 0.084 221.592 ;
    END
  END snoop_data_o[169]
  PIN snoop_data_o[16]
    DIRECTION OUTPUT ;
    USE SIGNAL ;
    PORT
      LAYER M4 ;
        RECT  0 222.24 0.084 222.264 ;
    END
  END snoop_data_o[16]
  PIN snoop_data_o[170]
    DIRECTION OUTPUT ;
    USE SIGNAL ;
    PORT
      LAYER M4 ;
        RECT  0 226.656 0.084 226.68 ;
    END
  END snoop_data_o[170]
  PIN snoop_data_o[171]
    DIRECTION OUTPUT ;
    USE SIGNAL ;
    PORT
      LAYER M4 ;
        RECT  0 228.192 0.084 228.216 ;
    END
  END snoop_data_o[171]
  PIN snoop_data_o[172]
    DIRECTION OUTPUT ;
    USE SIGNAL ;
    PORT
      LAYER M4 ;
        RECT  0 221.856 0.084 221.88 ;
    END
  END snoop_data_o[172]
  PIN snoop_data_o[173]
    DIRECTION OUTPUT ;
    USE SIGNAL ;
    PORT
      LAYER M4 ;
        RECT  0 228.096 0.084 228.12 ;
    END
  END snoop_data_o[173]
  PIN snoop_data_o[174]
    DIRECTION OUTPUT ;
    USE SIGNAL ;
    PORT
      LAYER M4 ;
        RECT  0 222.336 0.084 222.36 ;
    END
  END snoop_data_o[174]
  PIN snoop_data_o[175]
    DIRECTION OUTPUT ;
    USE SIGNAL ;
    PORT
      LAYER M4 ;
        RECT  0 223.488 0.084 223.512 ;
    END
  END snoop_data_o[175]
  PIN snoop_data_o[176]
    DIRECTION OUTPUT ;
    USE SIGNAL ;
    PORT
      LAYER M4 ;
        RECT  0 225.6 0.084 225.624 ;
    END
  END snoop_data_o[176]
  PIN snoop_data_o[177]
    DIRECTION OUTPUT ;
    USE SIGNAL ;
    PORT
      LAYER M5 ;
        RECT  29.664 274.916 29.688 275 ;
    END
  END snoop_data_o[177]
  PIN snoop_data_o[178]
    DIRECTION OUTPUT ;
    USE SIGNAL ;
    PORT
      LAYER M5 ;
        RECT  34.752 274.916 34.776 275 ;
    END
  END snoop_data_o[178]
  PIN snoop_data_o[179]
    DIRECTION OUTPUT ;
    USE SIGNAL ;
    PORT
      LAYER M5 ;
        RECT  32.544 274.916 32.568 275 ;
    END
  END snoop_data_o[179]
  PIN snoop_data_o[17]
    DIRECTION OUTPUT ;
    USE SIGNAL ;
    PORT
      LAYER M5 ;
        RECT  45.696 274.916 45.72 275 ;
    END
  END snoop_data_o[17]
  PIN snoop_data_o[180]
    DIRECTION OUTPUT ;
    USE SIGNAL ;
    PORT
      LAYER M5 ;
        RECT  36.288 274.916 36.312 275 ;
    END
  END snoop_data_o[180]
  PIN snoop_data_o[181]
    DIRECTION OUTPUT ;
    USE SIGNAL ;
    PORT
      LAYER M5 ;
        RECT  33.216 274.916 33.24 275 ;
    END
  END snoop_data_o[181]
  PIN snoop_data_o[182]
    DIRECTION OUTPUT ;
    USE SIGNAL ;
    PORT
      LAYER M5 ;
        RECT  35.52 274.916 35.544 275 ;
    END
  END snoop_data_o[182]
  PIN snoop_data_o[183]
    DIRECTION OUTPUT ;
    USE SIGNAL ;
    PORT
      LAYER M5 ;
        RECT  30.24 274.916 30.264 275 ;
    END
  END snoop_data_o[183]
  PIN snoop_data_o[184]
    DIRECTION OUTPUT ;
    USE SIGNAL ;
    PORT
      LAYER M5 ;
        RECT  31.488 274.916 31.512 275 ;
    END
  END snoop_data_o[184]
  PIN snoop_data_o[185]
    DIRECTION OUTPUT ;
    USE SIGNAL ;
    PORT
      LAYER M5 ;
        RECT  29.76 274.916 29.784 275 ;
    END
  END snoop_data_o[185]
  PIN snoop_data_o[186]
    DIRECTION OUTPUT ;
    USE SIGNAL ;
    PORT
      LAYER M5 ;
        RECT  34.464 274.916 34.488 275 ;
    END
  END snoop_data_o[186]
  PIN snoop_data_o[187]
    DIRECTION OUTPUT ;
    USE SIGNAL ;
    PORT
      LAYER M5 ;
        RECT  35.616 274.916 35.64 275 ;
    END
  END snoop_data_o[187]
  PIN snoop_data_o[188]
    DIRECTION OUTPUT ;
    USE SIGNAL ;
    PORT
      LAYER M5 ;
        RECT  33.024 274.916 33.048 275 ;
    END
  END snoop_data_o[188]
  PIN snoop_data_o[189]
    DIRECTION OUTPUT ;
    USE SIGNAL ;
    PORT
      LAYER M5 ;
        RECT  36.768 274.916 36.792 275 ;
    END
  END snoop_data_o[189]
  PIN snoop_data_o[18]
    DIRECTION OUTPUT ;
    USE SIGNAL ;
    PORT
      LAYER M5 ;
        RECT  39.168 274.916 39.192 275 ;
    END
  END snoop_data_o[18]
  PIN snoop_data_o[190]
    DIRECTION OUTPUT ;
    USE SIGNAL ;
    PORT
      LAYER M5 ;
        RECT  34.56 274.916 34.584 275 ;
    END
  END snoop_data_o[190]
  PIN snoop_data_o[191]
    DIRECTION OUTPUT ;
    USE SIGNAL ;
    PORT
      LAYER M5 ;
        RECT  30.048 274.916 30.072 275 ;
    END
  END snoop_data_o[191]
  PIN snoop_data_o[192]
    DIRECTION OUTPUT ;
    USE SIGNAL ;
    PORT
      LAYER M5 ;
        RECT  30.624 274.916 30.648 275 ;
    END
  END snoop_data_o[192]
  PIN snoop_data_o[193]
    DIRECTION OUTPUT ;
    USE SIGNAL ;
    PORT
      LAYER M5 ;
        RECT  30.816 274.916 30.84 275 ;
    END
  END snoop_data_o[193]
  PIN snoop_data_o[194]
    DIRECTION OUTPUT ;
    USE SIGNAL ;
    PORT
      LAYER M5 ;
        RECT  35.904 274.916 35.928 275 ;
    END
  END snoop_data_o[194]
  PIN snoop_data_o[195]
    DIRECTION OUTPUT ;
    USE SIGNAL ;
    PORT
      LAYER M5 ;
        RECT  38.208 274.916 38.232 275 ;
    END
  END snoop_data_o[195]
  PIN snoop_data_o[196]
    DIRECTION OUTPUT ;
    USE SIGNAL ;
    PORT
      LAYER M5 ;
        RECT  38.688 274.916 38.712 275 ;
    END
  END snoop_data_o[196]
  PIN snoop_data_o[197]
    DIRECTION OUTPUT ;
    USE SIGNAL ;
    PORT
      LAYER M5 ;
        RECT  36.192 274.916 36.216 275 ;
    END
  END snoop_data_o[197]
  PIN snoop_data_o[198]
    DIRECTION OUTPUT ;
    USE SIGNAL ;
    PORT
      LAYER M5 ;
        RECT  45.312 274.916 45.336 275 ;
    END
  END snoop_data_o[198]
  PIN snoop_data_o[199]
    DIRECTION OUTPUT ;
    USE SIGNAL ;
    PORT
      LAYER M5 ;
        RECT  39.744 274.916 39.768 275 ;
    END
  END snoop_data_o[199]
  PIN snoop_data_o[19]
    DIRECTION OUTPUT ;
    USE SIGNAL ;
    PORT
      LAYER M5 ;
        RECT  45.408 274.916 45.432 275 ;
    END
  END snoop_data_o[19]
  PIN snoop_data_o[1]
    DIRECTION OUTPUT ;
    USE SIGNAL ;
    PORT
      LAYER M5 ;
        RECT  31.776 274.916 31.8 275 ;
    END
  END snoop_data_o[1]
  PIN snoop_data_o[200]
    DIRECTION OUTPUT ;
    USE SIGNAL ;
    PORT
      LAYER M5 ;
        RECT  39.84 274.916 39.864 275 ;
    END
  END snoop_data_o[200]
  PIN snoop_data_o[201]
    DIRECTION OUTPUT ;
    USE SIGNAL ;
    PORT
      LAYER M5 ;
        RECT  39.936 274.916 39.96 275 ;
    END
  END snoop_data_o[201]
  PIN snoop_data_o[202]
    DIRECTION OUTPUT ;
    USE SIGNAL ;
    PORT
      LAYER M5 ;
        RECT  40.032 274.916 40.056 275 ;
    END
  END snoop_data_o[202]
  PIN snoop_data_o[203]
    DIRECTION OUTPUT ;
    USE SIGNAL ;
    PORT
      LAYER M5 ;
        RECT  40.224 274.916 40.248 275 ;
    END
  END snoop_data_o[203]
  PIN snoop_data_o[204]
    DIRECTION OUTPUT ;
    USE SIGNAL ;
    PORT
      LAYER M5 ;
        RECT  40.32 274.916 40.344 275 ;
    END
  END snoop_data_o[204]
  PIN snoop_data_o[205]
    DIRECTION OUTPUT ;
    USE SIGNAL ;
    PORT
      LAYER M5 ;
        RECT  32.928 274.916 32.952 275 ;
    END
  END snoop_data_o[205]
  PIN snoop_data_o[206]
    DIRECTION OUTPUT ;
    USE SIGNAL ;
    PORT
      LAYER M5 ;
        RECT  37.248 274.916 37.272 275 ;
    END
  END snoop_data_o[206]
  PIN snoop_data_o[207]
    DIRECTION OUTPUT ;
    USE SIGNAL ;
    PORT
      LAYER M5 ;
        RECT  31.968 274.916 31.992 275 ;
    END
  END snoop_data_o[207]
  PIN snoop_data_o[208]
    DIRECTION OUTPUT ;
    USE SIGNAL ;
    PORT
      LAYER M5 ;
        RECT  31.296 274.916 31.32 275 ;
    END
  END snoop_data_o[208]
  PIN snoop_data_o[209]
    DIRECTION OUTPUT ;
    USE SIGNAL ;
    PORT
      LAYER M5 ;
        RECT  37.152 274.916 37.176 275 ;
    END
  END snoop_data_o[209]
  PIN snoop_data_o[20]
    DIRECTION OUTPUT ;
    USE SIGNAL ;
    PORT
      LAYER M5 ;
        RECT  37.536 274.916 37.56 275 ;
    END
  END snoop_data_o[20]
  PIN snoop_data_o[210]
    DIRECTION OUTPUT ;
    USE SIGNAL ;
    PORT
      LAYER M5 ;
        RECT  33.696 274.916 33.72 275 ;
    END
  END snoop_data_o[210]
  PIN snoop_data_o[211]
    DIRECTION OUTPUT ;
    USE SIGNAL ;
    PORT
      LAYER M5 ;
        RECT  34.272 274.916 34.296 275 ;
    END
  END snoop_data_o[211]
  PIN snoop_data_o[212]
    DIRECTION OUTPUT ;
    USE SIGNAL ;
    PORT
      LAYER M5 ;
        RECT  35.328 274.916 35.352 275 ;
    END
  END snoop_data_o[212]
  PIN snoop_data_o[213]
    DIRECTION OUTPUT ;
    USE SIGNAL ;
    PORT
      LAYER M5 ;
        RECT  35.04 274.916 35.064 275 ;
    END
  END snoop_data_o[213]
  PIN snoop_data_o[214]
    DIRECTION OUTPUT ;
    USE SIGNAL ;
    PORT
      LAYER M5 ;
        RECT  38.304 274.916 38.328 275 ;
    END
  END snoop_data_o[214]
  PIN snoop_data_o[215]
    DIRECTION OUTPUT ;
    USE SIGNAL ;
    PORT
      LAYER M5 ;
        RECT  44.16 274.916 44.184 275 ;
    END
  END snoop_data_o[215]
  PIN snoop_data_o[216]
    DIRECTION OUTPUT ;
    USE SIGNAL ;
    PORT
      LAYER M5 ;
        RECT  42.72 274.916 42.744 275 ;
    END
  END snoop_data_o[216]
  PIN snoop_data_o[217]
    DIRECTION OUTPUT ;
    USE SIGNAL ;
    PORT
      LAYER M5 ;
        RECT  40.608 274.916 40.632 275 ;
    END
  END snoop_data_o[217]
  PIN snoop_data_o[218]
    DIRECTION OUTPUT ;
    USE SIGNAL ;
    PORT
      LAYER M5 ;
        RECT  42.336 274.916 42.36 275 ;
    END
  END snoop_data_o[218]
  PIN snoop_data_o[219]
    DIRECTION OUTPUT ;
    USE SIGNAL ;
    PORT
      LAYER M5 ;
        RECT  42.048 274.916 42.072 275 ;
    END
  END snoop_data_o[219]
  PIN snoop_data_o[21]
    DIRECTION OUTPUT ;
    USE SIGNAL ;
    PORT
      LAYER M5 ;
        RECT  45.504 274.916 45.528 275 ;
    END
  END snoop_data_o[21]
  PIN snoop_data_o[220]
    DIRECTION OUTPUT ;
    USE SIGNAL ;
    PORT
      LAYER M5 ;
        RECT  42.912 274.916 42.936 275 ;
    END
  END snoop_data_o[220]
  PIN snoop_data_o[221]
    DIRECTION OUTPUT ;
    USE SIGNAL ;
    PORT
      LAYER M5 ;
        RECT  41.856 274.916 41.88 275 ;
    END
  END snoop_data_o[221]
  PIN snoop_data_o[222]
    DIRECTION OUTPUT ;
    USE SIGNAL ;
    PORT
      LAYER M5 ;
        RECT  42.624 274.916 42.648 275 ;
    END
  END snoop_data_o[222]
  PIN snoop_data_o[223]
    DIRECTION OUTPUT ;
    USE SIGNAL ;
    PORT
      LAYER M5 ;
        RECT  41.952 274.916 41.976 275 ;
    END
  END snoop_data_o[223]
  PIN snoop_data_o[224]
    DIRECTION OUTPUT ;
    USE SIGNAL ;
    PORT
      LAYER M5 ;
        RECT  40.416 274.916 40.44 275 ;
    END
  END snoop_data_o[224]
  PIN snoop_data_o[225]
    DIRECTION OUTPUT ;
    USE SIGNAL ;
    PORT
      LAYER M5 ;
        RECT  35.232 274.916 35.256 275 ;
    END
  END snoop_data_o[225]
  PIN snoop_data_o[226]
    DIRECTION OUTPUT ;
    USE SIGNAL ;
    PORT
      LAYER M5 ;
        RECT  30.528 274.916 30.552 275 ;
    END
  END snoop_data_o[226]
  PIN snoop_data_o[227]
    DIRECTION OUTPUT ;
    USE SIGNAL ;
    PORT
      LAYER M5 ;
        RECT  31.68 274.916 31.704 275 ;
    END
  END snoop_data_o[227]
  PIN snoop_data_o[228]
    DIRECTION OUTPUT ;
    USE SIGNAL ;
    PORT
      LAYER M5 ;
        RECT  38.016 274.916 38.04 275 ;
    END
  END snoop_data_o[228]
  PIN snoop_data_o[229]
    DIRECTION OUTPUT ;
    USE SIGNAL ;
    PORT
      LAYER M5 ;
        RECT  37.728 274.916 37.752 275 ;
    END
  END snoop_data_o[229]
  PIN snoop_data_o[22]
    DIRECTION OUTPUT ;
    USE SIGNAL ;
    PORT
      LAYER M5 ;
        RECT  38.88 274.916 38.904 275 ;
    END
  END snoop_data_o[22]
  PIN snoop_data_o[230]
    DIRECTION OUTPUT ;
    USE SIGNAL ;
    PORT
      LAYER M5 ;
        RECT  37.344 274.916 37.368 275 ;
    END
  END snoop_data_o[230]
  PIN snoop_data_o[231]
    DIRECTION OUTPUT ;
    USE SIGNAL ;
    PORT
      LAYER M5 ;
        RECT  30.144 274.916 30.168 275 ;
    END
  END snoop_data_o[231]
  PIN snoop_data_o[232]
    DIRECTION OUTPUT ;
    USE SIGNAL ;
    PORT
      LAYER M5 ;
        RECT  31.872 274.916 31.896 275 ;
    END
  END snoop_data_o[232]
  PIN snoop_data_o[233]
    DIRECTION OUTPUT ;
    USE SIGNAL ;
    PORT
      LAYER M5 ;
        RECT  31.008 274.916 31.032 275 ;
    END
  END snoop_data_o[233]
  PIN snoop_data_o[234]
    DIRECTION OUTPUT ;
    USE SIGNAL ;
    PORT
      LAYER M5 ;
        RECT  31.584 274.916 31.608 275 ;
    END
  END snoop_data_o[234]
  PIN snoop_data_o[235]
    DIRECTION OUTPUT ;
    USE SIGNAL ;
    PORT
      LAYER M5 ;
        RECT  42.432 274.916 42.456 275 ;
    END
  END snoop_data_o[235]
  PIN snoop_data_o[236]
    DIRECTION OUTPUT ;
    USE SIGNAL ;
    PORT
      LAYER M5 ;
        RECT  41.664 274.916 41.688 275 ;
    END
  END snoop_data_o[236]
  PIN snoop_data_o[237]
    DIRECTION OUTPUT ;
    USE SIGNAL ;
    PORT
      LAYER M5 ;
        RECT  41.184 274.916 41.208 275 ;
    END
  END snoop_data_o[237]
  PIN snoop_data_o[238]
    DIRECTION OUTPUT ;
    USE SIGNAL ;
    PORT
      LAYER M5 ;
        RECT  40.704 274.916 40.728 275 ;
    END
  END snoop_data_o[238]
  PIN snoop_data_o[239]
    DIRECTION OUTPUT ;
    USE SIGNAL ;
    PORT
      LAYER M5 ;
        RECT  42.528 274.916 42.552 275 ;
    END
  END snoop_data_o[239]
  PIN snoop_data_o[23]
    DIRECTION OUTPUT ;
    USE SIGNAL ;
    PORT
      LAYER M5 ;
        RECT  45.6 274.916 45.624 275 ;
    END
  END snoop_data_o[23]
  PIN snoop_data_o[240]
    DIRECTION OUTPUT ;
    USE SIGNAL ;
    PORT
      LAYER M5 ;
        RECT  40.8 274.916 40.824 275 ;
    END
  END snoop_data_o[240]
  PIN snoop_data_o[241]
    DIRECTION OUTPUT ;
    USE SIGNAL ;
    PORT
      LAYER M5 ;
        RECT  41.376 274.916 41.4 275 ;
    END
  END snoop_data_o[241]
  PIN snoop_data_o[242]
    DIRECTION OUTPUT ;
    USE SIGNAL ;
    PORT
      LAYER M5 ;
        RECT  41.472 274.916 41.496 275 ;
    END
  END snoop_data_o[242]
  PIN snoop_data_o[243]
    DIRECTION OUTPUT ;
    USE SIGNAL ;
    PORT
      LAYER M5 ;
        RECT  41.568 274.916 41.592 275 ;
    END
  END snoop_data_o[243]
  PIN snoop_data_o[244]
    DIRECTION OUTPUT ;
    USE SIGNAL ;
    PORT
      LAYER M5 ;
        RECT  41.28 274.916 41.304 275 ;
    END
  END snoop_data_o[244]
  PIN snoop_data_o[245]
    DIRECTION OUTPUT ;
    USE SIGNAL ;
    PORT
      LAYER M5 ;
        RECT  39.648 274.916 39.672 275 ;
    END
  END snoop_data_o[245]
  PIN snoop_data_o[246]
    DIRECTION OUTPUT ;
    USE SIGNAL ;
    PORT
      LAYER M5 ;
        RECT  45.12 274.916 45.144 275 ;
    END
  END snoop_data_o[246]
  PIN snoop_data_o[247]
    DIRECTION OUTPUT ;
    USE SIGNAL ;
    PORT
      LAYER M5 ;
        RECT  45.216 274.916 45.24 275 ;
    END
  END snoop_data_o[247]
  PIN snoop_data_o[248]
    DIRECTION OUTPUT ;
    USE SIGNAL ;
    PORT
      LAYER M5 ;
        RECT  44.448 274.916 44.472 275 ;
    END
  END snoop_data_o[248]
  PIN snoop_data_o[249]
    DIRECTION OUTPUT ;
    USE SIGNAL ;
    PORT
      LAYER M5 ;
        RECT  44.256 274.916 44.28 275 ;
    END
  END snoop_data_o[249]
  PIN snoop_data_o[24]
    DIRECTION OUTPUT ;
    USE SIGNAL ;
    PORT
      LAYER M5 ;
        RECT  37.44 274.916 37.464 275 ;
    END
  END snoop_data_o[24]
  PIN snoop_data_o[250]
    DIRECTION OUTPUT ;
    USE SIGNAL ;
    PORT
      LAYER M5 ;
        RECT  44.928 274.916 44.952 275 ;
    END
  END snoop_data_o[250]
  PIN snoop_data_o[251]
    DIRECTION OUTPUT ;
    USE SIGNAL ;
    PORT
      LAYER M5 ;
        RECT  44.832 274.916 44.856 275 ;
    END
  END snoop_data_o[251]
  PIN snoop_data_o[252]
    DIRECTION OUTPUT ;
    USE SIGNAL ;
    PORT
      LAYER M5 ;
        RECT  44.544 274.916 44.568 275 ;
    END
  END snoop_data_o[252]
  PIN snoop_data_o[253]
    DIRECTION OUTPUT ;
    USE SIGNAL ;
    PORT
      LAYER M5 ;
        RECT  44.64 274.916 44.664 275 ;
    END
  END snoop_data_o[253]
  PIN snoop_data_o[254]
    DIRECTION OUTPUT ;
    USE SIGNAL ;
    PORT
      LAYER M5 ;
        RECT  44.736 274.916 44.76 275 ;
    END
  END snoop_data_o[254]
  PIN snoop_data_o[255]
    DIRECTION OUTPUT ;
    USE SIGNAL ;
    PORT
      LAYER M5 ;
        RECT  44.352 274.916 44.376 275 ;
    END
  END snoop_data_o[255]
  PIN snoop_data_o[256]
    DIRECTION OUTPUT ;
    USE SIGNAL ;
    PORT
      LAYER M4 ;
        RECT  161.916 249.6 162 249.624 ;
    END
  END snoop_data_o[256]
  PIN snoop_data_o[257]
    DIRECTION OUTPUT ;
    USE SIGNAL ;
    PORT
      LAYER M4 ;
        RECT  161.916 240.768 162 240.792 ;
    END
  END snoop_data_o[257]
  PIN snoop_data_o[258]
    DIRECTION OUTPUT ;
    USE SIGNAL ;
    PORT
      LAYER M4 ;
        RECT  161.916 233.472 162 233.496 ;
    END
  END snoop_data_o[258]
  PIN snoop_data_o[259]
    DIRECTION OUTPUT ;
    USE SIGNAL ;
    PORT
      LAYER M4 ;
        RECT  161.916 235.68 162 235.704 ;
    END
  END snoop_data_o[259]
  PIN snoop_data_o[25]
    DIRECTION OUTPUT ;
    USE SIGNAL ;
    PORT
      LAYER M5 ;
        RECT  31.392 274.916 31.416 275 ;
    END
  END snoop_data_o[25]
  PIN snoop_data_o[260]
    DIRECTION OUTPUT ;
    USE SIGNAL ;
    PORT
      LAYER M4 ;
        RECT  161.916 238.272 162 238.296 ;
    END
  END snoop_data_o[260]
  PIN snoop_data_o[261]
    DIRECTION OUTPUT ;
    USE SIGNAL ;
    PORT
      LAYER M5 ;
        RECT  109.728 274.916 109.752 275 ;
    END
  END snoop_data_o[261]
  PIN snoop_data_o[262]
    DIRECTION OUTPUT ;
    USE SIGNAL ;
    PORT
      LAYER M5 ;
        RECT  111.456 274.916 111.48 275 ;
    END
  END snoop_data_o[262]
  PIN snoop_data_o[263]
    DIRECTION OUTPUT ;
    USE SIGNAL ;
    PORT
      LAYER M5 ;
        RECT  109.344 274.916 109.368 275 ;
    END
  END snoop_data_o[263]
  PIN snoop_data_o[264]
    DIRECTION OUTPUT ;
    USE SIGNAL ;
    PORT
      LAYER M5 ;
        RECT  117.984 274.916 118.008 275 ;
    END
  END snoop_data_o[264]
  PIN snoop_data_o[265]
    DIRECTION OUTPUT ;
    USE SIGNAL ;
    PORT
      LAYER M5 ;
        RECT  109.248 274.916 109.272 275 ;
    END
  END snoop_data_o[265]
  PIN snoop_data_o[266]
    DIRECTION OUTPUT ;
    USE SIGNAL ;
    PORT
      LAYER M5 ;
        RECT  118.272 274.916 118.296 275 ;
    END
  END snoop_data_o[266]
  PIN snoop_data_o[267]
    DIRECTION OUTPUT ;
    USE SIGNAL ;
    PORT
      LAYER M5 ;
        RECT  109.536 274.916 109.56 275 ;
    END
  END snoop_data_o[267]
  PIN snoop_data_o[268]
    DIRECTION OUTPUT ;
    USE SIGNAL ;
    PORT
      LAYER M5 ;
        RECT  107.808 274.916 107.832 275 ;
    END
  END snoop_data_o[268]
  PIN snoop_data_o[269]
    DIRECTION OUTPUT ;
    USE SIGNAL ;
    PORT
      LAYER M5 ;
        RECT  113.856 274.916 113.88 275 ;
    END
  END snoop_data_o[269]
  PIN snoop_data_o[26]
    DIRECTION OUTPUT ;
    USE SIGNAL ;
    PORT
      LAYER M5 ;
        RECT  34.368 274.916 34.392 275 ;
    END
  END snoop_data_o[26]
  PIN snoop_data_o[270]
    DIRECTION OUTPUT ;
    USE SIGNAL ;
    PORT
      LAYER M5 ;
        RECT  117.888 274.916 117.912 275 ;
    END
  END snoop_data_o[270]
  PIN snoop_data_o[271]
    DIRECTION OUTPUT ;
    USE SIGNAL ;
    PORT
      LAYER M4 ;
        RECT  161.916 243.456 162 243.48 ;
    END
  END snoop_data_o[271]
  PIN snoop_data_o[272]
    DIRECTION OUTPUT ;
    USE SIGNAL ;
    PORT
      LAYER M4 ;
        RECT  161.916 231.648 162 231.672 ;
    END
  END snoop_data_o[272]
  PIN snoop_data_o[273]
    DIRECTION OUTPUT ;
    USE SIGNAL ;
    PORT
      LAYER M4 ;
        RECT  161.916 249.312 162 249.336 ;
    END
  END snoop_data_o[273]
  PIN snoop_data_o[274]
    DIRECTION OUTPUT ;
    USE SIGNAL ;
    PORT
      LAYER M4 ;
        RECT  161.916 245.184 162 245.208 ;
    END
  END snoop_data_o[274]
  PIN snoop_data_o[275]
    DIRECTION OUTPUT ;
    USE SIGNAL ;
    PORT
      LAYER M4 ;
        RECT  161.916 235.584 162 235.608 ;
    END
  END snoop_data_o[275]
  PIN snoop_data_o[276]
    DIRECTION OUTPUT ;
    USE SIGNAL ;
    PORT
      LAYER M4 ;
        RECT  161.916 239.232 162 239.256 ;
    END
  END snoop_data_o[276]
  PIN snoop_data_o[277]
    DIRECTION OUTPUT ;
    USE SIGNAL ;
    PORT
      LAYER M4 ;
        RECT  161.916 232.608 162 232.632 ;
    END
  END snoop_data_o[277]
  PIN snoop_data_o[278]
    DIRECTION OUTPUT ;
    USE SIGNAL ;
    PORT
      LAYER M4 ;
        RECT  161.916 233.952 162 233.976 ;
    END
  END snoop_data_o[278]
  PIN snoop_data_o[279]
    DIRECTION OUTPUT ;
    USE SIGNAL ;
    PORT
      LAYER M4 ;
        RECT  161.916 232.992 162 233.016 ;
    END
  END snoop_data_o[279]
  PIN snoop_data_o[27]
    DIRECTION OUTPUT ;
    USE SIGNAL ;
    PORT
      LAYER M5 ;
        RECT  32.832 274.916 32.856 275 ;
    END
  END snoop_data_o[27]
  PIN snoop_data_o[280]
    DIRECTION OUTPUT ;
    USE SIGNAL ;
    PORT
      LAYER M4 ;
        RECT  161.916 238.464 162 238.488 ;
    END
  END snoop_data_o[280]
  PIN snoop_data_o[281]
    DIRECTION OUTPUT ;
    USE SIGNAL ;
    PORT
      LAYER M4 ;
        RECT  161.916 243.648 162 243.672 ;
    END
  END snoop_data_o[281]
  PIN snoop_data_o[282]
    DIRECTION OUTPUT ;
    USE SIGNAL ;
    PORT
      LAYER M4 ;
        RECT  161.916 235.392 162 235.416 ;
    END
  END snoop_data_o[282]
  PIN snoop_data_o[283]
    DIRECTION OUTPUT ;
    USE SIGNAL ;
    PORT
      LAYER M4 ;
        RECT  161.916 246.72 162 246.744 ;
    END
  END snoop_data_o[283]
  PIN snoop_data_o[284]
    DIRECTION OUTPUT ;
    USE SIGNAL ;
    PORT
      LAYER M4 ;
        RECT  161.916 238.944 162 238.968 ;
    END
  END snoop_data_o[284]
  PIN snoop_data_o[285]
    DIRECTION OUTPUT ;
    USE SIGNAL ;
    PORT
      LAYER M4 ;
        RECT  161.916 245.76 162 245.784 ;
    END
  END snoop_data_o[285]
  PIN snoop_data_o[286]
    DIRECTION OUTPUT ;
    USE SIGNAL ;
    PORT
      LAYER M4 ;
        RECT  161.916 246.24 162 246.264 ;
    END
  END snoop_data_o[286]
  PIN snoop_data_o[287]
    DIRECTION OUTPUT ;
    USE SIGNAL ;
    PORT
      LAYER M4 ;
        RECT  161.916 233.184 162 233.208 ;
    END
  END snoop_data_o[287]
  PIN snoop_data_o[288]
    DIRECTION OUTPUT ;
    USE SIGNAL ;
    PORT
      LAYER M4 ;
        RECT  161.916 232.896 162 232.92 ;
    END
  END snoop_data_o[288]
  PIN snoop_data_o[289]
    DIRECTION OUTPUT ;
    USE SIGNAL ;
    PORT
      LAYER M4 ;
        RECT  161.916 242.112 162 242.136 ;
    END
  END snoop_data_o[289]
  PIN snoop_data_o[28]
    DIRECTION OUTPUT ;
    USE SIGNAL ;
    PORT
      LAYER M5 ;
        RECT  34.08 274.916 34.104 275 ;
    END
  END snoop_data_o[28]
  PIN snoop_data_o[290]
    DIRECTION OUTPUT ;
    USE SIGNAL ;
    PORT
      LAYER M4 ;
        RECT  161.916 236.064 162 236.088 ;
    END
  END snoop_data_o[290]
  PIN snoop_data_o[291]
    DIRECTION OUTPUT ;
    USE SIGNAL ;
    PORT
      LAYER M5 ;
        RECT  115.68 274.916 115.704 275 ;
    END
  END snoop_data_o[291]
  PIN snoop_data_o[292]
    DIRECTION OUTPUT ;
    USE SIGNAL ;
    PORT
      LAYER M5 ;
        RECT  119.328 274.916 119.352 275 ;
    END
  END snoop_data_o[292]
  PIN snoop_data_o[293]
    DIRECTION OUTPUT ;
    USE SIGNAL ;
    PORT
      LAYER M5 ;
        RECT  118.752 274.916 118.776 275 ;
    END
  END snoop_data_o[293]
  PIN snoop_data_o[294]
    DIRECTION OUTPUT ;
    USE SIGNAL ;
    PORT
      LAYER M5 ;
        RECT  107.712 274.916 107.736 275 ;
    END
  END snoop_data_o[294]
  PIN snoop_data_o[295]
    DIRECTION OUTPUT ;
    USE SIGNAL ;
    PORT
      LAYER M5 ;
        RECT  107.232 274.916 107.256 275 ;
    END
  END snoop_data_o[295]
  PIN snoop_data_o[296]
    DIRECTION OUTPUT ;
    USE SIGNAL ;
    PORT
      LAYER M5 ;
        RECT  119.808 274.916 119.832 275 ;
    END
  END snoop_data_o[296]
  PIN snoop_data_o[297]
    DIRECTION OUTPUT ;
    USE SIGNAL ;
    PORT
      LAYER M5 ;
        RECT  119.52 274.916 119.544 275 ;
    END
  END snoop_data_o[297]
  PIN snoop_data_o[298]
    DIRECTION OUTPUT ;
    USE SIGNAL ;
    PORT
      LAYER M5 ;
        RECT  119.712 274.916 119.736 275 ;
    END
  END snoop_data_o[298]
  PIN snoop_data_o[299]
    DIRECTION OUTPUT ;
    USE SIGNAL ;
    PORT
      LAYER M5 ;
        RECT  117.696 274.916 117.72 275 ;
    END
  END snoop_data_o[299]
  PIN snoop_data_o[29]
    DIRECTION OUTPUT ;
    USE SIGNAL ;
    PORT
      LAYER M5 ;
        RECT  34.656 274.916 34.68 275 ;
    END
  END snoop_data_o[29]
  PIN snoop_data_o[2]
    DIRECTION OUTPUT ;
    USE SIGNAL ;
    PORT
      LAYER M5 ;
        RECT  36.864 274.916 36.888 275 ;
    END
  END snoop_data_o[2]
  PIN snoop_data_o[300]
    DIRECTION OUTPUT ;
    USE SIGNAL ;
    PORT
      LAYER M5 ;
        RECT  119.04 274.916 119.064 275 ;
    END
  END snoop_data_o[300]
  PIN snoop_data_o[301]
    DIRECTION OUTPUT ;
    USE SIGNAL ;
    PORT
      LAYER M4 ;
        RECT  161.916 234.432 162 234.456 ;
    END
  END snoop_data_o[301]
  PIN snoop_data_o[302]
    DIRECTION OUTPUT ;
    USE SIGNAL ;
    PORT
      LAYER M4 ;
        RECT  161.916 233.76 162 233.784 ;
    END
  END snoop_data_o[302]
  PIN snoop_data_o[303]
    DIRECTION OUTPUT ;
    USE SIGNAL ;
    PORT
      LAYER M4 ;
        RECT  161.916 246.144 162 246.168 ;
    END
  END snoop_data_o[303]
  PIN snoop_data_o[304]
    DIRECTION OUTPUT ;
    USE SIGNAL ;
    PORT
      LAYER M4 ;
        RECT  161.916 232.32 162 232.344 ;
    END
  END snoop_data_o[304]
  PIN snoop_data_o[305]
    DIRECTION OUTPUT ;
    USE SIGNAL ;
    PORT
      LAYER M4 ;
        RECT  161.916 242.688 162 242.712 ;
    END
  END snoop_data_o[305]
  PIN snoop_data_o[306]
    DIRECTION OUTPUT ;
    USE SIGNAL ;
    PORT
      LAYER M4 ;
        RECT  161.916 247.008 162 247.032 ;
    END
  END snoop_data_o[306]
  PIN snoop_data_o[307]
    DIRECTION OUTPUT ;
    USE SIGNAL ;
    PORT
      LAYER M4 ;
        RECT  161.916 233.568 162 233.592 ;
    END
  END snoop_data_o[307]
  PIN snoop_data_o[308]
    DIRECTION OUTPUT ;
    USE SIGNAL ;
    PORT
      LAYER M4 ;
        RECT  161.916 246.528 162 246.552 ;
    END
  END snoop_data_o[308]
  PIN snoop_data_o[309]
    DIRECTION OUTPUT ;
    USE SIGNAL ;
    PORT
      LAYER M4 ;
        RECT  161.916 245.376 162 245.4 ;
    END
  END snoop_data_o[309]
  PIN snoop_data_o[30]
    DIRECTION OUTPUT ;
    USE SIGNAL ;
    PORT
      LAYER M5 ;
        RECT  33.408 274.916 33.432 275 ;
    END
  END snoop_data_o[30]
  PIN snoop_data_o[310]
    DIRECTION OUTPUT ;
    USE SIGNAL ;
    PORT
      LAYER M4 ;
        RECT  161.916 239.712 162 239.736 ;
    END
  END snoop_data_o[310]
  PIN snoop_data_o[311]
    DIRECTION OUTPUT ;
    USE SIGNAL ;
    PORT
      LAYER M4 ;
        RECT  161.916 247.392 162 247.416 ;
    END
  END snoop_data_o[311]
  PIN snoop_data_o[312]
    DIRECTION OUTPUT ;
    USE SIGNAL ;
    PORT
      LAYER M4 ;
        RECT  161.916 239.328 162 239.352 ;
    END
  END snoop_data_o[312]
  PIN snoop_data_o[313]
    DIRECTION OUTPUT ;
    USE SIGNAL ;
    PORT
      LAYER M4 ;
        RECT  161.916 238.752 162 238.776 ;
    END
  END snoop_data_o[313]
  PIN snoop_data_o[314]
    DIRECTION OUTPUT ;
    USE SIGNAL ;
    PORT
      LAYER M4 ;
        RECT  161.916 239.04 162 239.064 ;
    END
  END snoop_data_o[314]
  PIN snoop_data_o[315]
    DIRECTION OUTPUT ;
    USE SIGNAL ;
    PORT
      LAYER M4 ;
        RECT  161.916 233.856 162 233.88 ;
    END
  END snoop_data_o[315]
  PIN snoop_data_o[316]
    DIRECTION OUTPUT ;
    USE SIGNAL ;
    PORT
      LAYER M4 ;
        RECT  161.916 235.104 162 235.128 ;
    END
  END snoop_data_o[316]
  PIN snoop_data_o[317]
    DIRECTION OUTPUT ;
    USE SIGNAL ;
    PORT
      LAYER M4 ;
        RECT  161.916 247.488 162 247.512 ;
    END
  END snoop_data_o[317]
  PIN snoop_data_o[318]
    DIRECTION OUTPUT ;
    USE SIGNAL ;
    PORT
      LAYER M4 ;
        RECT  161.916 240.672 162 240.696 ;
    END
  END snoop_data_o[318]
  PIN snoop_data_o[319]
    DIRECTION OUTPUT ;
    USE SIGNAL ;
    PORT
      LAYER M4 ;
        RECT  161.916 234.144 162 234.168 ;
    END
  END snoop_data_o[319]
  PIN snoop_data_o[31]
    DIRECTION OUTPUT ;
    USE SIGNAL ;
    PORT
      LAYER M5 ;
        RECT  30.336 274.916 30.36 275 ;
    END
  END snoop_data_o[31]
  PIN snoop_data_o[320]
    DIRECTION OUTPUT ;
    USE SIGNAL ;
    PORT
      LAYER M4 ;
        RECT  161.916 234.72 162 234.744 ;
    END
  END snoop_data_o[320]
  PIN snoop_data_o[321]
    DIRECTION OUTPUT ;
    USE SIGNAL ;
    PORT
      LAYER M4 ;
        RECT  161.916 239.136 162 239.16 ;
    END
  END snoop_data_o[321]
  PIN snoop_data_o[322]
    DIRECTION OUTPUT ;
    USE SIGNAL ;
    PORT
      LAYER M4 ;
        RECT  161.916 232.128 162 232.152 ;
    END
  END snoop_data_o[322]
  PIN snoop_data_o[323]
    DIRECTION OUTPUT ;
    USE SIGNAL ;
    PORT
      LAYER M4 ;
        RECT  161.916 240.288 162 240.312 ;
    END
  END snoop_data_o[323]
  PIN snoop_data_o[324]
    DIRECTION OUTPUT ;
    USE SIGNAL ;
    PORT
      LAYER M4 ;
        RECT  161.916 231.552 162 231.576 ;
    END
  END snoop_data_o[324]
  PIN snoop_data_o[325]
    DIRECTION OUTPUT ;
    USE SIGNAL ;
    PORT
      LAYER M4 ;
        RECT  161.916 232.416 162 232.44 ;
    END
  END snoop_data_o[325]
  PIN snoop_data_o[326]
    DIRECTION OUTPUT ;
    USE SIGNAL ;
    PORT
      LAYER M4 ;
        RECT  161.916 232.032 162 232.056 ;
    END
  END snoop_data_o[326]
  PIN snoop_data_o[327]
    DIRECTION OUTPUT ;
    USE SIGNAL ;
    PORT
      LAYER M4 ;
        RECT  161.916 241.728 162 241.752 ;
    END
  END snoop_data_o[327]
  PIN snoop_data_o[328]
    DIRECTION OUTPUT ;
    USE SIGNAL ;
    PORT
      LAYER M4 ;
        RECT  161.916 231.936 162 231.96 ;
    END
  END snoop_data_o[328]
  PIN snoop_data_o[329]
    DIRECTION OUTPUT ;
    USE SIGNAL ;
    PORT
      LAYER M4 ;
        RECT  161.916 249.696 162 249.72 ;
    END
  END snoop_data_o[329]
  PIN snoop_data_o[32]
    DIRECTION OUTPUT ;
    USE SIGNAL ;
    PORT
      LAYER M5 ;
        RECT  33.792 274.916 33.816 275 ;
    END
  END snoop_data_o[32]
  PIN snoop_data_o[330]
    DIRECTION OUTPUT ;
    USE SIGNAL ;
    PORT
      LAYER M4 ;
        RECT  161.916 235.2 162 235.224 ;
    END
  END snoop_data_o[330]
  PIN snoop_data_o[331]
    DIRECTION OUTPUT ;
    USE SIGNAL ;
    PORT
      LAYER M4 ;
        RECT  161.916 232.8 162 232.824 ;
    END
  END snoop_data_o[331]
  PIN snoop_data_o[332]
    DIRECTION OUTPUT ;
    USE SIGNAL ;
    PORT
      LAYER M4 ;
        RECT  161.916 239.808 162 239.832 ;
    END
  END snoop_data_o[332]
  PIN snoop_data_o[333]
    DIRECTION OUTPUT ;
    USE SIGNAL ;
    PORT
      LAYER M4 ;
        RECT  161.916 231.84 162 231.864 ;
    END
  END snoop_data_o[333]
  PIN snoop_data_o[334]
    DIRECTION OUTPUT ;
    USE SIGNAL ;
    PORT
      LAYER M4 ;
        RECT  161.916 233.376 162 233.4 ;
    END
  END snoop_data_o[334]
  PIN snoop_data_o[335]
    DIRECTION OUTPUT ;
    USE SIGNAL ;
    PORT
      LAYER M4 ;
        RECT  161.916 231.264 162 231.288 ;
    END
  END snoop_data_o[335]
  PIN snoop_data_o[336]
    DIRECTION OUTPUT ;
    USE SIGNAL ;
    PORT
      LAYER M4 ;
        RECT  161.916 232.704 162 232.728 ;
    END
  END snoop_data_o[336]
  PIN snoop_data_o[337]
    DIRECTION OUTPUT ;
    USE SIGNAL ;
    PORT
      LAYER M4 ;
        RECT  161.916 231.36 162 231.384 ;
    END
  END snoop_data_o[337]
  PIN snoop_data_o[338]
    DIRECTION OUTPUT ;
    USE SIGNAL ;
    PORT
      LAYER M4 ;
        RECT  161.916 236.256 162 236.28 ;
    END
  END snoop_data_o[338]
  PIN snoop_data_o[339]
    DIRECTION OUTPUT ;
    USE SIGNAL ;
    PORT
      LAYER M4 ;
        RECT  161.916 249.12 162 249.144 ;
    END
  END snoop_data_o[339]
  PIN snoop_data_o[33]
    DIRECTION OUTPUT ;
    USE SIGNAL ;
    PORT
      LAYER M5 ;
        RECT  32.448 274.916 32.472 275 ;
    END
  END snoop_data_o[33]
  PIN snoop_data_o[340]
    DIRECTION OUTPUT ;
    USE SIGNAL ;
    PORT
      LAYER M4 ;
        RECT  161.916 231.456 162 231.48 ;
    END
  END snoop_data_o[340]
  PIN snoop_data_o[341]
    DIRECTION OUTPUT ;
    USE SIGNAL ;
    PORT
      LAYER M4 ;
        RECT  161.916 231.744 162 231.768 ;
    END
  END snoop_data_o[341]
  PIN snoop_data_o[342]
    DIRECTION OUTPUT ;
    USE SIGNAL ;
    PORT
      LAYER M4 ;
        RECT  161.916 233.28 162 233.304 ;
    END
  END snoop_data_o[342]
  PIN snoop_data_o[343]
    DIRECTION OUTPUT ;
    USE SIGNAL ;
    PORT
      LAYER M4 ;
        RECT  161.916 236.64 162 236.664 ;
    END
  END snoop_data_o[343]
  PIN snoop_data_o[344]
    DIRECTION OUTPUT ;
    USE SIGNAL ;
    PORT
      LAYER M4 ;
        RECT  161.916 234.912 162 234.936 ;
    END
  END snoop_data_o[344]
  PIN snoop_data_o[345]
    DIRECTION OUTPUT ;
    USE SIGNAL ;
    PORT
      LAYER M4 ;
        RECT  161.916 233.664 162 233.688 ;
    END
  END snoop_data_o[345]
  PIN snoop_data_o[346]
    DIRECTION OUTPUT ;
    USE SIGNAL ;
    PORT
      LAYER M4 ;
        RECT  161.916 235.008 162 235.032 ;
    END
  END snoop_data_o[346]
  PIN snoop_data_o[347]
    DIRECTION OUTPUT ;
    USE SIGNAL ;
    PORT
      LAYER M4 ;
        RECT  161.916 233.088 162 233.112 ;
    END
  END snoop_data_o[347]
  PIN snoop_data_o[348]
    DIRECTION OUTPUT ;
    USE SIGNAL ;
    PORT
      LAYER M4 ;
        RECT  161.916 245.088 162 245.112 ;
    END
  END snoop_data_o[348]
  PIN snoop_data_o[349]
    DIRECTION OUTPUT ;
    USE SIGNAL ;
    PORT
      LAYER M4 ;
        RECT  161.916 232.224 162 232.248 ;
    END
  END snoop_data_o[349]
  PIN snoop_data_o[34]
    DIRECTION OUTPUT ;
    USE SIGNAL ;
    PORT
      LAYER M5 ;
        RECT  33.888 274.916 33.912 275 ;
    END
  END snoop_data_o[34]
  PIN snoop_data_o[350]
    DIRECTION OUTPUT ;
    USE SIGNAL ;
    PORT
      LAYER M4 ;
        RECT  161.916 248.736 162 248.76 ;
    END
  END snoop_data_o[350]
  PIN snoop_data_o[351]
    DIRECTION OUTPUT ;
    USE SIGNAL ;
    PORT
      LAYER M4 ;
        RECT  161.916 245.952 162 245.976 ;
    END
  END snoop_data_o[351]
  PIN snoop_data_o[352]
    DIRECTION OUTPUT ;
    USE SIGNAL ;
    PORT
      LAYER M4 ;
        RECT  161.916 234.336 162 234.36 ;
    END
  END snoop_data_o[352]
  PIN snoop_data_o[353]
    DIRECTION OUTPUT ;
    USE SIGNAL ;
    PORT
      LAYER M4 ;
        RECT  161.916 237.984 162 238.008 ;
    END
  END snoop_data_o[353]
  PIN snoop_data_o[354]
    DIRECTION OUTPUT ;
    USE SIGNAL ;
    PORT
      LAYER M4 ;
        RECT  161.916 248.064 162 248.088 ;
    END
  END snoop_data_o[354]
  PIN snoop_data_o[355]
    DIRECTION OUTPUT ;
    USE SIGNAL ;
    PORT
      LAYER M4 ;
        RECT  161.916 234.048 162 234.072 ;
    END
  END snoop_data_o[355]
  PIN snoop_data_o[356]
    DIRECTION OUTPUT ;
    USE SIGNAL ;
    PORT
      LAYER M4 ;
        RECT  161.916 241.632 162 241.656 ;
    END
  END snoop_data_o[356]
  PIN snoop_data_o[357]
    DIRECTION OUTPUT ;
    USE SIGNAL ;
    PORT
      LAYER M4 ;
        RECT  161.916 239.904 162 239.928 ;
    END
  END snoop_data_o[357]
  PIN snoop_data_o[358]
    DIRECTION OUTPUT ;
    USE SIGNAL ;
    PORT
      LAYER M4 ;
        RECT  161.916 234.624 162 234.648 ;
    END
  END snoop_data_o[358]
  PIN snoop_data_o[359]
    DIRECTION OUTPUT ;
    USE SIGNAL ;
    PORT
      LAYER M4 ;
        RECT  161.916 247.2 162 247.224 ;
    END
  END snoop_data_o[359]
  PIN snoop_data_o[35]
    DIRECTION OUTPUT ;
    USE SIGNAL ;
    PORT
      LAYER M5 ;
        RECT  35.712 274.916 35.736 275 ;
    END
  END snoop_data_o[35]
  PIN snoop_data_o[360]
    DIRECTION OUTPUT ;
    USE SIGNAL ;
    PORT
      LAYER M4 ;
        RECT  161.916 244.512 162 244.536 ;
    END
  END snoop_data_o[360]
  PIN snoop_data_o[361]
    DIRECTION OUTPUT ;
    USE SIGNAL ;
    PORT
      LAYER M4 ;
        RECT  161.916 237.024 162 237.048 ;
    END
  END snoop_data_o[361]
  PIN snoop_data_o[362]
    DIRECTION OUTPUT ;
    USE SIGNAL ;
    PORT
      LAYER M4 ;
        RECT  161.916 236.736 162 236.76 ;
    END
  END snoop_data_o[362]
  PIN snoop_data_o[363]
    DIRECTION OUTPUT ;
    USE SIGNAL ;
    PORT
      LAYER M4 ;
        RECT  161.916 236.448 162 236.472 ;
    END
  END snoop_data_o[363]
  PIN snoop_data_o[364]
    DIRECTION OUTPUT ;
    USE SIGNAL ;
    PORT
      LAYER M4 ;
        RECT  161.916 247.968 162 247.992 ;
    END
  END snoop_data_o[364]
  PIN snoop_data_o[365]
    DIRECTION OUTPUT ;
    USE SIGNAL ;
    PORT
      LAYER M4 ;
        RECT  161.916 240.48 162 240.504 ;
    END
  END snoop_data_o[365]
  PIN snoop_data_o[366]
    DIRECTION OUTPUT ;
    USE SIGNAL ;
    PORT
      LAYER M4 ;
        RECT  161.916 238.56 162 238.584 ;
    END
  END snoop_data_o[366]
  PIN snoop_data_o[367]
    DIRECTION OUTPUT ;
    USE SIGNAL ;
    PORT
      LAYER M4 ;
        RECT  161.916 241.056 162 241.08 ;
    END
  END snoop_data_o[367]
  PIN snoop_data_o[368]
    DIRECTION OUTPUT ;
    USE SIGNAL ;
    PORT
      LAYER M4 ;
        RECT  161.916 242.208 162 242.232 ;
    END
  END snoop_data_o[368]
  PIN snoop_data_o[369]
    DIRECTION OUTPUT ;
    USE SIGNAL ;
    PORT
      LAYER M4 ;
        RECT  161.916 249.024 162 249.048 ;
    END
  END snoop_data_o[369]
  PIN snoop_data_o[36]
    DIRECTION OUTPUT ;
    USE SIGNAL ;
    PORT
      LAYER M5 ;
        RECT  36.96 274.916 36.984 275 ;
    END
  END snoop_data_o[36]
  PIN snoop_data_o[370]
    DIRECTION OUTPUT ;
    USE SIGNAL ;
    PORT
      LAYER M4 ;
        RECT  161.916 245.856 162 245.88 ;
    END
  END snoop_data_o[370]
  PIN snoop_data_o[371]
    DIRECTION OUTPUT ;
    USE SIGNAL ;
    PORT
      LAYER M4 ;
        RECT  161.916 244.896 162 244.92 ;
    END
  END snoop_data_o[371]
  PIN snoop_data_o[372]
    DIRECTION OUTPUT ;
    USE SIGNAL ;
    PORT
      LAYER M4 ;
        RECT  161.916 236.832 162 236.856 ;
    END
  END snoop_data_o[372]
  PIN snoop_data_o[373]
    DIRECTION OUTPUT ;
    USE SIGNAL ;
    PORT
      LAYER M4 ;
        RECT  161.916 240.576 162 240.6 ;
    END
  END snoop_data_o[373]
  PIN snoop_data_o[374]
    DIRECTION OUTPUT ;
    USE SIGNAL ;
    PORT
      LAYER M4 ;
        RECT  161.916 235.968 162 235.992 ;
    END
  END snoop_data_o[374]
  PIN snoop_data_o[375]
    DIRECTION OUTPUT ;
    USE SIGNAL ;
    PORT
      LAYER M4 ;
        RECT  161.916 246.912 162 246.936 ;
    END
  END snoop_data_o[375]
  PIN snoop_data_o[376]
    DIRECTION OUTPUT ;
    USE SIGNAL ;
    PORT
      LAYER M4 ;
        RECT  161.916 244.32 162 244.344 ;
    END
  END snoop_data_o[376]
  PIN snoop_data_o[377]
    DIRECTION OUTPUT ;
    USE SIGNAL ;
    PORT
      LAYER M4 ;
        RECT  161.916 245.664 162 245.688 ;
    END
  END snoop_data_o[377]
  PIN snoop_data_o[378]
    DIRECTION OUTPUT ;
    USE SIGNAL ;
    PORT
      LAYER M4 ;
        RECT  161.916 247.776 162 247.8 ;
    END
  END snoop_data_o[378]
  PIN snoop_data_o[379]
    DIRECTION OUTPUT ;
    USE SIGNAL ;
    PORT
      LAYER M4 ;
        RECT  161.916 244.992 162 245.016 ;
    END
  END snoop_data_o[379]
  PIN snoop_data_o[37]
    DIRECTION OUTPUT ;
    USE SIGNAL ;
    PORT
      LAYER M5 ;
        RECT  34.176 274.916 34.2 275 ;
    END
  END snoop_data_o[37]
  PIN snoop_data_o[380]
    DIRECTION OUTPUT ;
    USE SIGNAL ;
    PORT
      LAYER M4 ;
        RECT  161.916 241.536 162 241.56 ;
    END
  END snoop_data_o[380]
  PIN snoop_data_o[381]
    DIRECTION OUTPUT ;
    USE SIGNAL ;
    PORT
      LAYER M4 ;
        RECT  161.916 234.24 162 234.264 ;
    END
  END snoop_data_o[381]
  PIN snoop_data_o[382]
    DIRECTION OUTPUT ;
    USE SIGNAL ;
    PORT
      LAYER M4 ;
        RECT  161.916 236.16 162 236.184 ;
    END
  END snoop_data_o[382]
  PIN snoop_data_o[383]
    DIRECTION OUTPUT ;
    USE SIGNAL ;
    PORT
      LAYER M4 ;
        RECT  161.916 248.832 162 248.856 ;
    END
  END snoop_data_o[383]
  PIN snoop_data_o[384]
    DIRECTION OUTPUT ;
    USE SIGNAL ;
    PORT
      LAYER M4 ;
        RECT  161.916 242.016 162 242.04 ;
    END
  END snoop_data_o[384]
  PIN snoop_data_o[385]
    DIRECTION OUTPUT ;
    USE SIGNAL ;
    PORT
      LAYER M4 ;
        RECT  161.916 245.472 162 245.496 ;
    END
  END snoop_data_o[385]
  PIN snoop_data_o[386]
    DIRECTION OUTPUT ;
    USE SIGNAL ;
    PORT
      LAYER M4 ;
        RECT  161.916 242.304 162 242.328 ;
    END
  END snoop_data_o[386]
  PIN snoop_data_o[387]
    DIRECTION OUTPUT ;
    USE SIGNAL ;
    PORT
      LAYER M4 ;
        RECT  161.916 248.64 162 248.664 ;
    END
  END snoop_data_o[387]
  PIN snoop_data_o[388]
    DIRECTION OUTPUT ;
    USE SIGNAL ;
    PORT
      LAYER M4 ;
        RECT  161.916 244.704 162 244.728 ;
    END
  END snoop_data_o[388]
  PIN snoop_data_o[389]
    DIRECTION OUTPUT ;
    USE SIGNAL ;
    PORT
      LAYER M4 ;
        RECT  161.916 249.408 162 249.432 ;
    END
  END snoop_data_o[389]
  PIN snoop_data_o[38]
    DIRECTION OUTPUT ;
    USE SIGNAL ;
    PORT
      LAYER M5 ;
        RECT  36 274.916 36.024 275 ;
    END
  END snoop_data_o[38]
  PIN snoop_data_o[390]
    DIRECTION OUTPUT ;
    USE SIGNAL ;
    PORT
      LAYER M4 ;
        RECT  161.916 237.696 162 237.72 ;
    END
  END snoop_data_o[390]
  PIN snoop_data_o[391]
    DIRECTION OUTPUT ;
    USE SIGNAL ;
    PORT
      LAYER M5 ;
        RECT  106.944 274.916 106.968 275 ;
    END
  END snoop_data_o[391]
  PIN snoop_data_o[392]
    DIRECTION OUTPUT ;
    USE SIGNAL ;
    PORT
      LAYER M5 ;
        RECT  118.08 274.916 118.104 275 ;
    END
  END snoop_data_o[392]
  PIN snoop_data_o[393]
    DIRECTION OUTPUT ;
    USE SIGNAL ;
    PORT
      LAYER M5 ;
        RECT  117.504 274.916 117.528 275 ;
    END
  END snoop_data_o[393]
  PIN snoop_data_o[394]
    DIRECTION OUTPUT ;
    USE SIGNAL ;
    PORT
      LAYER M5 ;
        RECT  118.464 274.916 118.488 275 ;
    END
  END snoop_data_o[394]
  PIN snoop_data_o[395]
    DIRECTION OUTPUT ;
    USE SIGNAL ;
    PORT
      LAYER M5 ;
        RECT  113.952 274.916 113.976 275 ;
    END
  END snoop_data_o[395]
  PIN snoop_data_o[396]
    DIRECTION OUTPUT ;
    USE SIGNAL ;
    PORT
      LAYER M5 ;
        RECT  116.64 274.916 116.664 275 ;
    END
  END snoop_data_o[396]
  PIN snoop_data_o[397]
    DIRECTION OUTPUT ;
    USE SIGNAL ;
    PORT
      LAYER M5 ;
        RECT  109.824 274.916 109.848 275 ;
    END
  END snoop_data_o[397]
  PIN snoop_data_o[398]
    DIRECTION OUTPUT ;
    USE SIGNAL ;
    PORT
      LAYER M5 ;
        RECT  115.2 274.916 115.224 275 ;
    END
  END snoop_data_o[398]
  PIN snoop_data_o[399]
    DIRECTION OUTPUT ;
    USE SIGNAL ;
    PORT
      LAYER M5 ;
        RECT  118.656 274.916 118.68 275 ;
    END
  END snoop_data_o[399]
  PIN snoop_data_o[39]
    DIRECTION OUTPUT ;
    USE SIGNAL ;
    PORT
      LAYER M5 ;
        RECT  31.2 274.916 31.224 275 ;
    END
  END snoop_data_o[39]
  PIN snoop_data_o[3]
    DIRECTION OUTPUT ;
    USE SIGNAL ;
    PORT
      LAYER M5 ;
        RECT  37.632 274.916 37.656 275 ;
    END
  END snoop_data_o[3]
  PIN snoop_data_o[400]
    DIRECTION OUTPUT ;
    USE SIGNAL ;
    PORT
      LAYER M5 ;
        RECT  115.776 274.916 115.8 275 ;
    END
  END snoop_data_o[400]
  PIN snoop_data_o[401]
    DIRECTION OUTPUT ;
    USE SIGNAL ;
    PORT
      LAYER M5 ;
        RECT  108.96 274.916 108.984 275 ;
    END
  END snoop_data_o[401]
  PIN snoop_data_o[402]
    DIRECTION OUTPUT ;
    USE SIGNAL ;
    PORT
      LAYER M5 ;
        RECT  108.864 274.916 108.888 275 ;
    END
  END snoop_data_o[402]
  PIN snoop_data_o[403]
    DIRECTION OUTPUT ;
    USE SIGNAL ;
    PORT
      LAYER M5 ;
        RECT  107.04 274.916 107.064 275 ;
    END
  END snoop_data_o[403]
  PIN snoop_data_o[404]
    DIRECTION OUTPUT ;
    USE SIGNAL ;
    PORT
      LAYER M5 ;
        RECT  112.224 274.916 112.248 275 ;
    END
  END snoop_data_o[404]
  PIN snoop_data_o[405]
    DIRECTION OUTPUT ;
    USE SIGNAL ;
    PORT
      LAYER M5 ;
        RECT  110.496 274.916 110.52 275 ;
    END
  END snoop_data_o[405]
  PIN snoop_data_o[406]
    DIRECTION OUTPUT ;
    USE SIGNAL ;
    PORT
      LAYER M5 ;
        RECT  116.928 274.916 116.952 275 ;
    END
  END snoop_data_o[406]
  PIN snoop_data_o[407]
    DIRECTION OUTPUT ;
    USE SIGNAL ;
    PORT
      LAYER M5 ;
        RECT  112.896 274.916 112.92 275 ;
    END
  END snoop_data_o[407]
  PIN snoop_data_o[408]
    DIRECTION OUTPUT ;
    USE SIGNAL ;
    PORT
      LAYER M5 ;
        RECT  111.552 274.916 111.576 275 ;
    END
  END snoop_data_o[408]
  PIN snoop_data_o[409]
    DIRECTION OUTPUT ;
    USE SIGNAL ;
    PORT
      LAYER M5 ;
        RECT  116.256 274.916 116.28 275 ;
    END
  END snoop_data_o[409]
  PIN snoop_data_o[40]
    DIRECTION OUTPUT ;
    USE SIGNAL ;
    PORT
      LAYER M5 ;
        RECT  32.064 274.916 32.088 275 ;
    END
  END snoop_data_o[40]
  PIN snoop_data_o[410]
    DIRECTION OUTPUT ;
    USE SIGNAL ;
    PORT
      LAYER M5 ;
        RECT  107.52 274.916 107.544 275 ;
    END
  END snoop_data_o[410]
  PIN snoop_data_o[411]
    DIRECTION OUTPUT ;
    USE SIGNAL ;
    PORT
      LAYER M4 ;
        RECT  161.916 232.512 162 232.536 ;
    END
  END snoop_data_o[411]
  PIN snoop_data_o[412]
    DIRECTION OUTPUT ;
    USE SIGNAL ;
    PORT
      LAYER M4 ;
        RECT  161.916 244.224 162 244.248 ;
    END
  END snoop_data_o[412]
  PIN snoop_data_o[413]
    DIRECTION OUTPUT ;
    USE SIGNAL ;
    PORT
      LAYER M4 ;
        RECT  161.916 238.368 162 238.392 ;
    END
  END snoop_data_o[413]
  PIN snoop_data_o[414]
    DIRECTION OUTPUT ;
    USE SIGNAL ;
    PORT
      LAYER M4 ;
        RECT  161.916 237.408 162 237.432 ;
    END
  END snoop_data_o[414]
  PIN snoop_data_o[415]
    DIRECTION OUTPUT ;
    USE SIGNAL ;
    PORT
      LAYER M4 ;
        RECT  161.916 241.152 162 241.176 ;
    END
  END snoop_data_o[415]
  PIN snoop_data_o[416]
    DIRECTION OUTPUT ;
    USE SIGNAL ;
    PORT
      LAYER M4 ;
        RECT  161.916 237.504 162 237.528 ;
    END
  END snoop_data_o[416]
  PIN snoop_data_o[417]
    DIRECTION OUTPUT ;
    USE SIGNAL ;
    PORT
      LAYER M4 ;
        RECT  161.916 242.784 162 242.808 ;
    END
  END snoop_data_o[417]
  PIN snoop_data_o[418]
    DIRECTION OUTPUT ;
    USE SIGNAL ;
    PORT
      LAYER M4 ;
        RECT  161.916 235.872 162 235.896 ;
    END
  END snoop_data_o[418]
  PIN snoop_data_o[419]
    DIRECTION OUTPUT ;
    USE SIGNAL ;
    PORT
      LAYER M4 ;
        RECT  161.916 243.168 162 243.192 ;
    END
  END snoop_data_o[419]
  PIN snoop_data_o[41]
    DIRECTION OUTPUT ;
    USE SIGNAL ;
    PORT
      LAYER M5 ;
        RECT  33.312 274.916 33.336 275 ;
    END
  END snoop_data_o[41]
  PIN snoop_data_o[420]
    DIRECTION OUTPUT ;
    USE SIGNAL ;
    PORT
      LAYER M4 ;
        RECT  161.916 244.032 162 244.056 ;
    END
  END snoop_data_o[420]
  PIN snoop_data_o[421]
    DIRECTION OUTPUT ;
    USE SIGNAL ;
    PORT
      LAYER M4 ;
        RECT  161.916 243.552 162 243.576 ;
    END
  END snoop_data_o[421]
  PIN snoop_data_o[422]
    DIRECTION OUTPUT ;
    USE SIGNAL ;
    PORT
      LAYER M4 ;
        RECT  161.916 241.824 162 241.848 ;
    END
  END snoop_data_o[422]
  PIN snoop_data_o[423]
    DIRECTION OUTPUT ;
    USE SIGNAL ;
    PORT
      LAYER M4 ;
        RECT  161.916 240.96 162 240.984 ;
    END
  END snoop_data_o[423]
  PIN snoop_data_o[424]
    DIRECTION OUTPUT ;
    USE SIGNAL ;
    PORT
      LAYER M4 ;
        RECT  161.916 239.424 162 239.448 ;
    END
  END snoop_data_o[424]
  PIN snoop_data_o[425]
    DIRECTION OUTPUT ;
    USE SIGNAL ;
    PORT
      LAYER M4 ;
        RECT  161.916 241.92 162 241.944 ;
    END
  END snoop_data_o[425]
  PIN snoop_data_o[426]
    DIRECTION OUTPUT ;
    USE SIGNAL ;
    PORT
      LAYER M4 ;
        RECT  161.916 240 162 240.024 ;
    END
  END snoop_data_o[426]
  PIN snoop_data_o[427]
    DIRECTION OUTPUT ;
    USE SIGNAL ;
    PORT
      LAYER M4 ;
        RECT  161.916 246.432 162 246.456 ;
    END
  END snoop_data_o[427]
  PIN snoop_data_o[428]
    DIRECTION OUTPUT ;
    USE SIGNAL ;
    PORT
      LAYER M4 ;
        RECT  161.916 237.888 162 237.912 ;
    END
  END snoop_data_o[428]
  PIN snoop_data_o[429]
    DIRECTION OUTPUT ;
    USE SIGNAL ;
    PORT
      LAYER M4 ;
        RECT  161.916 247.584 162 247.608 ;
    END
  END snoop_data_o[429]
  PIN snoop_data_o[42]
    DIRECTION OUTPUT ;
    USE SIGNAL ;
    PORT
      LAYER M5 ;
        RECT  34.848 274.916 34.872 275 ;
    END
  END snoop_data_o[42]
  PIN snoop_data_o[430]
    DIRECTION OUTPUT ;
    USE SIGNAL ;
    PORT
      LAYER M4 ;
        RECT  161.916 246.816 162 246.84 ;
    END
  END snoop_data_o[430]
  PIN snoop_data_o[431]
    DIRECTION OUTPUT ;
    USE SIGNAL ;
    PORT
      LAYER M4 ;
        RECT  161.916 241.44 162 241.464 ;
    END
  END snoop_data_o[431]
  PIN snoop_data_o[432]
    DIRECTION OUTPUT ;
    USE SIGNAL ;
    PORT
      LAYER M4 ;
        RECT  161.916 238.848 162 238.872 ;
    END
  END snoop_data_o[432]
  PIN snoop_data_o[433]
    DIRECTION OUTPUT ;
    USE SIGNAL ;
    PORT
      LAYER M4 ;
        RECT  161.916 237.216 162 237.24 ;
    END
  END snoop_data_o[433]
  PIN snoop_data_o[434]
    DIRECTION OUTPUT ;
    USE SIGNAL ;
    PORT
      LAYER M4 ;
        RECT  161.916 243.744 162 243.768 ;
    END
  END snoop_data_o[434]
  PIN snoop_data_o[435]
    DIRECTION OUTPUT ;
    USE SIGNAL ;
    PORT
      LAYER M4 ;
        RECT  161.916 246.048 162 246.072 ;
    END
  END snoop_data_o[435]
  PIN snoop_data_o[436]
    DIRECTION OUTPUT ;
    USE SIGNAL ;
    PORT
      LAYER M5 ;
        RECT  127.2 274.916 127.224 275 ;
    END
  END snoop_data_o[436]
  PIN snoop_data_o[437]
    DIRECTION OUTPUT ;
    USE SIGNAL ;
    PORT
      LAYER M5 ;
        RECT  126.72 274.916 126.744 275 ;
    END
  END snoop_data_o[437]
  PIN snoop_data_o[438]
    DIRECTION OUTPUT ;
    USE SIGNAL ;
    PORT
      LAYER M5 ;
        RECT  126.048 274.916 126.072 275 ;
    END
  END snoop_data_o[438]
  PIN snoop_data_o[439]
    DIRECTION OUTPUT ;
    USE SIGNAL ;
    PORT
      LAYER M5 ;
        RECT  125.952 274.916 125.976 275 ;
    END
  END snoop_data_o[439]
  PIN snoop_data_o[43]
    DIRECTION OUTPUT ;
    USE SIGNAL ;
    PORT
      LAYER M5 ;
        RECT  35.136 274.916 35.16 275 ;
    END
  END snoop_data_o[43]
  PIN snoop_data_o[440]
    DIRECTION OUTPUT ;
    USE SIGNAL ;
    PORT
      LAYER M5 ;
        RECT  126.24 274.916 126.264 275 ;
    END
  END snoop_data_o[440]
  PIN snoop_data_o[441]
    DIRECTION OUTPUT ;
    USE SIGNAL ;
    PORT
      LAYER M5 ;
        RECT  122.784 274.916 122.808 275 ;
    END
  END snoop_data_o[441]
  PIN snoop_data_o[442]
    DIRECTION OUTPUT ;
    USE SIGNAL ;
    PORT
      LAYER M5 ;
        RECT  122.592 274.916 122.616 275 ;
    END
  END snoop_data_o[442]
  PIN snoop_data_o[443]
    DIRECTION OUTPUT ;
    USE SIGNAL ;
    PORT
      LAYER M5 ;
        RECT  122.688 274.916 122.712 275 ;
    END
  END snoop_data_o[443]
  PIN snoop_data_o[444]
    DIRECTION OUTPUT ;
    USE SIGNAL ;
    PORT
      LAYER M5 ;
        RECT  121.824 274.916 121.848 275 ;
    END
  END snoop_data_o[444]
  PIN snoop_data_o[445]
    DIRECTION OUTPUT ;
    USE SIGNAL ;
    PORT
      LAYER M5 ;
        RECT  122.208 274.916 122.232 275 ;
    END
  END snoop_data_o[445]
  PIN snoop_data_o[446]
    DIRECTION OUTPUT ;
    USE SIGNAL ;
    PORT
      LAYER M5 ;
        RECT  122.304 274.916 122.328 275 ;
    END
  END snoop_data_o[446]
  PIN snoop_data_o[447]
    DIRECTION OUTPUT ;
    USE SIGNAL ;
    PORT
      LAYER M5 ;
        RECT  122.4 274.916 122.424 275 ;
    END
  END snoop_data_o[447]
  PIN snoop_data_o[448]
    DIRECTION OUTPUT ;
    USE SIGNAL ;
    PORT
      LAYER M5 ;
        RECT  122.112 274.916 122.136 275 ;
    END
  END snoop_data_o[448]
  PIN snoop_data_o[449]
    DIRECTION OUTPUT ;
    USE SIGNAL ;
    PORT
      LAYER M5 ;
        RECT  122.496 274.916 122.52 275 ;
    END
  END snoop_data_o[449]
  PIN snoop_data_o[44]
    DIRECTION OUTPUT ;
    USE SIGNAL ;
    PORT
      LAYER M5 ;
        RECT  33.6 274.916 33.624 275 ;
    END
  END snoop_data_o[44]
  PIN snoop_data_o[450]
    DIRECTION OUTPUT ;
    USE SIGNAL ;
    PORT
      LAYER M5 ;
        RECT  121.92 274.916 121.944 275 ;
    END
  END snoop_data_o[450]
  PIN snoop_data_o[451]
    DIRECTION OUTPUT ;
    USE SIGNAL ;
    PORT
      LAYER M5 ;
        RECT  121.152 274.916 121.176 275 ;
    END
  END snoop_data_o[451]
  PIN snoop_data_o[452]
    DIRECTION OUTPUT ;
    USE SIGNAL ;
    PORT
      LAYER M5 ;
        RECT  120.768 274.916 120.792 275 ;
    END
  END snoop_data_o[452]
  PIN snoop_data_o[453]
    DIRECTION OUTPUT ;
    USE SIGNAL ;
    PORT
      LAYER M5 ;
        RECT  121.056 274.916 121.08 275 ;
    END
  END snoop_data_o[453]
  PIN snoop_data_o[454]
    DIRECTION OUTPUT ;
    USE SIGNAL ;
    PORT
      LAYER M5 ;
        RECT  120.96 274.916 120.984 275 ;
    END
  END snoop_data_o[454]
  PIN snoop_data_o[455]
    DIRECTION OUTPUT ;
    USE SIGNAL ;
    PORT
      LAYER M5 ;
        RECT  120.672 274.916 120.696 275 ;
    END
  END snoop_data_o[455]
  PIN snoop_data_o[456]
    DIRECTION OUTPUT ;
    USE SIGNAL ;
    PORT
      LAYER M5 ;
        RECT  121.536 274.916 121.56 275 ;
    END
  END snoop_data_o[456]
  PIN snoop_data_o[457]
    DIRECTION OUTPUT ;
    USE SIGNAL ;
    PORT
      LAYER M5 ;
        RECT  121.44 274.916 121.464 275 ;
    END
  END snoop_data_o[457]
  PIN snoop_data_o[458]
    DIRECTION OUTPUT ;
    USE SIGNAL ;
    PORT
      LAYER M5 ;
        RECT  120.864 274.916 120.888 275 ;
    END
  END snoop_data_o[458]
  PIN snoop_data_o[459]
    DIRECTION OUTPUT ;
    USE SIGNAL ;
    PORT
      LAYER M5 ;
        RECT  120.576 274.916 120.6 275 ;
    END
  END snoop_data_o[459]
  PIN snoop_data_o[45]
    DIRECTION OUTPUT ;
    USE SIGNAL ;
    PORT
      LAYER M5 ;
        RECT  42.24 274.916 42.264 275 ;
    END
  END snoop_data_o[45]
  PIN snoop_data_o[460]
    DIRECTION OUTPUT ;
    USE SIGNAL ;
    PORT
      LAYER M5 ;
        RECT  121.248 274.916 121.272 275 ;
    END
  END snoop_data_o[460]
  PIN snoop_data_o[461]
    DIRECTION OUTPUT ;
    USE SIGNAL ;
    PORT
      LAYER M5 ;
        RECT  122.88 274.916 122.904 275 ;
    END
  END snoop_data_o[461]
  PIN snoop_data_o[462]
    DIRECTION OUTPUT ;
    USE SIGNAL ;
    PORT
      LAYER M5 ;
        RECT  125.664 274.916 125.688 275 ;
    END
  END snoop_data_o[462]
  PIN snoop_data_o[463]
    DIRECTION OUTPUT ;
    USE SIGNAL ;
    PORT
      LAYER M5 ;
        RECT  124.128 274.916 124.152 275 ;
    END
  END snoop_data_o[463]
  PIN snoop_data_o[464]
    DIRECTION OUTPUT ;
    USE SIGNAL ;
    PORT
      LAYER M5 ;
        RECT  125.76 274.916 125.784 275 ;
    END
  END snoop_data_o[464]
  PIN snoop_data_o[465]
    DIRECTION OUTPUT ;
    USE SIGNAL ;
    PORT
      LAYER M5 ;
        RECT  127.008 274.916 127.032 275 ;
    END
  END snoop_data_o[465]
  PIN snoop_data_o[466]
    DIRECTION OUTPUT ;
    USE SIGNAL ;
    PORT
      LAYER M5 ;
        RECT  127.104 274.916 127.128 275 ;
    END
  END snoop_data_o[466]
  PIN snoop_data_o[467]
    DIRECTION OUTPUT ;
    USE SIGNAL ;
    PORT
      LAYER M5 ;
        RECT  123.744 274.916 123.768 275 ;
    END
  END snoop_data_o[467]
  PIN snoop_data_o[468]
    DIRECTION OUTPUT ;
    USE SIGNAL ;
    PORT
      LAYER M5 ;
        RECT  124.032 274.916 124.056 275 ;
    END
  END snoop_data_o[468]
  PIN snoop_data_o[469]
    DIRECTION OUTPUT ;
    USE SIGNAL ;
    PORT
      LAYER M5 ;
        RECT  125.856 274.916 125.88 275 ;
    END
  END snoop_data_o[469]
  PIN snoop_data_o[46]
    DIRECTION OUTPUT ;
    USE SIGNAL ;
    PORT
      LAYER M5 ;
        RECT  43.2 274.916 43.224 275 ;
    END
  END snoop_data_o[46]
  PIN snoop_data_o[470]
    DIRECTION OUTPUT ;
    USE SIGNAL ;
    PORT
      LAYER M5 ;
        RECT  123.936 274.916 123.96 275 ;
    END
  END snoop_data_o[470]
  PIN snoop_data_o[471]
    DIRECTION OUTPUT ;
    USE SIGNAL ;
    PORT
      LAYER M5 ;
        RECT  126.144 274.916 126.168 275 ;
    END
  END snoop_data_o[471]
  PIN snoop_data_o[472]
    DIRECTION OUTPUT ;
    USE SIGNAL ;
    PORT
      LAYER M5 ;
        RECT  125.568 274.916 125.592 275 ;
    END
  END snoop_data_o[472]
  PIN snoop_data_o[473]
    DIRECTION OUTPUT ;
    USE SIGNAL ;
    PORT
      LAYER M5 ;
        RECT  125.472 274.916 125.496 275 ;
    END
  END snoop_data_o[473]
  PIN snoop_data_o[474]
    DIRECTION OUTPUT ;
    USE SIGNAL ;
    PORT
      LAYER M5 ;
        RECT  125.376 274.916 125.4 275 ;
    END
  END snoop_data_o[474]
  PIN snoop_data_o[475]
    DIRECTION OUTPUT ;
    USE SIGNAL ;
    PORT
      LAYER M5 ;
        RECT  126.336 274.916 126.36 275 ;
    END
  END snoop_data_o[475]
  PIN snoop_data_o[476]
    DIRECTION OUTPUT ;
    USE SIGNAL ;
    PORT
      LAYER M5 ;
        RECT  126.432 274.916 126.456 275 ;
    END
  END snoop_data_o[476]
  PIN snoop_data_o[477]
    DIRECTION OUTPUT ;
    USE SIGNAL ;
    PORT
      LAYER M5 ;
        RECT  126.528 274.916 126.552 275 ;
    END
  END snoop_data_o[477]
  PIN snoop_data_o[478]
    DIRECTION OUTPUT ;
    USE SIGNAL ;
    PORT
      LAYER M5 ;
        RECT  125.28 274.916 125.304 275 ;
    END
  END snoop_data_o[478]
  PIN snoop_data_o[479]
    DIRECTION OUTPUT ;
    USE SIGNAL ;
    PORT
      LAYER M5 ;
        RECT  125.184 274.916 125.208 275 ;
    END
  END snoop_data_o[479]
  PIN snoop_data_o[47]
    DIRECTION OUTPUT ;
    USE SIGNAL ;
    PORT
      LAYER M5 ;
        RECT  43.488 274.916 43.512 275 ;
    END
  END snoop_data_o[47]
  PIN snoop_data_o[480]
    DIRECTION OUTPUT ;
    USE SIGNAL ;
    PORT
      LAYER M5 ;
        RECT  126.624 274.916 126.648 275 ;
    END
  END snoop_data_o[480]
  PIN snoop_data_o[481]
    DIRECTION OUTPUT ;
    USE SIGNAL ;
    PORT
      LAYER M5 ;
        RECT  123.552 274.916 123.576 275 ;
    END
  END snoop_data_o[481]
  PIN snoop_data_o[482]
    DIRECTION OUTPUT ;
    USE SIGNAL ;
    PORT
      LAYER M5 ;
        RECT  123.072 274.916 123.096 275 ;
    END
  END snoop_data_o[482]
  PIN snoop_data_o[483]
    DIRECTION OUTPUT ;
    USE SIGNAL ;
    PORT
      LAYER M5 ;
        RECT  123.36 274.916 123.384 275 ;
    END
  END snoop_data_o[483]
  PIN snoop_data_o[484]
    DIRECTION OUTPUT ;
    USE SIGNAL ;
    PORT
      LAYER M5 ;
        RECT  123.456 274.916 123.48 275 ;
    END
  END snoop_data_o[484]
  PIN snoop_data_o[485]
    DIRECTION OUTPUT ;
    USE SIGNAL ;
    PORT
      LAYER M5 ;
        RECT  122.976 274.916 123 275 ;
    END
  END snoop_data_o[485]
  PIN snoop_data_o[486]
    DIRECTION OUTPUT ;
    USE SIGNAL ;
    PORT
      LAYER M5 ;
        RECT  123.168 274.916 123.192 275 ;
    END
  END snoop_data_o[486]
  PIN snoop_data_o[487]
    DIRECTION OUTPUT ;
    USE SIGNAL ;
    PORT
      LAYER M5 ;
        RECT  123.648 274.916 123.672 275 ;
    END
  END snoop_data_o[487]
  PIN snoop_data_o[488]
    DIRECTION OUTPUT ;
    USE SIGNAL ;
    PORT
      LAYER M5 ;
        RECT  126.912 274.916 126.936 275 ;
    END
  END snoop_data_o[488]
  PIN snoop_data_o[489]
    DIRECTION OUTPUT ;
    USE SIGNAL ;
    PORT
      LAYER M5 ;
        RECT  123.264 274.916 123.288 275 ;
    END
  END snoop_data_o[489]
  PIN snoop_data_o[48]
    DIRECTION OUTPUT ;
    USE SIGNAL ;
    PORT
      LAYER M5 ;
        RECT  44.064 274.916 44.088 275 ;
    END
  END snoop_data_o[48]
  PIN snoop_data_o[490]
    DIRECTION OUTPUT ;
    USE SIGNAL ;
    PORT
      LAYER M5 ;
        RECT  123.84 274.916 123.864 275 ;
    END
  END snoop_data_o[490]
  PIN snoop_data_o[491]
    DIRECTION OUTPUT ;
    USE SIGNAL ;
    PORT
      LAYER M4 ;
        RECT  161.916 250.464 162 250.488 ;
    END
  END snoop_data_o[491]
  PIN snoop_data_o[492]
    DIRECTION OUTPUT ;
    USE SIGNAL ;
    PORT
      LAYER M5 ;
        RECT  134.976 274.916 135 275 ;
    END
  END snoop_data_o[492]
  PIN snoop_data_o[493]
    DIRECTION OUTPUT ;
    USE SIGNAL ;
    PORT
      LAYER M5 ;
        RECT  138.144 274.916 138.168 275 ;
    END
  END snoop_data_o[493]
  PIN snoop_data_o[494]
    DIRECTION OUTPUT ;
    USE SIGNAL ;
    PORT
      LAYER M5 ;
        RECT  138.048 274.916 138.072 275 ;
    END
  END snoop_data_o[494]
  PIN snoop_data_o[495]
    DIRECTION OUTPUT ;
    USE SIGNAL ;
    PORT
      LAYER M5 ;
        RECT  137.952 274.916 137.976 275 ;
    END
  END snoop_data_o[495]
  PIN snoop_data_o[496]
    DIRECTION OUTPUT ;
    USE SIGNAL ;
    PORT
      LAYER M4 ;
        RECT  161.916 250.368 162 250.392 ;
    END
  END snoop_data_o[496]
  PIN snoop_data_o[497]
    DIRECTION OUTPUT ;
    USE SIGNAL ;
    PORT
      LAYER M5 ;
        RECT  139.008 274.916 139.032 275 ;
    END
  END snoop_data_o[497]
  PIN snoop_data_o[498]
    DIRECTION OUTPUT ;
    USE SIGNAL ;
    PORT
      LAYER M5 ;
        RECT  139.104 274.916 139.128 275 ;
    END
  END snoop_data_o[498]
  PIN snoop_data_o[499]
    DIRECTION OUTPUT ;
    USE SIGNAL ;
    PORT
      LAYER M5 ;
        RECT  138.624 274.916 138.648 275 ;
    END
  END snoop_data_o[499]
  PIN snoop_data_o[49]
    DIRECTION OUTPUT ;
    USE SIGNAL ;
    PORT
      LAYER M5 ;
        RECT  42.816 274.916 42.84 275 ;
    END
  END snoop_data_o[49]
  PIN snoop_data_o[4]
    DIRECTION OUTPUT ;
    USE SIGNAL ;
    PORT
      LAYER M5 ;
        RECT  33.504 274.916 33.528 275 ;
    END
  END snoop_data_o[4]
  PIN snoop_data_o[500]
    DIRECTION OUTPUT ;
    USE SIGNAL ;
    PORT
      LAYER M5 ;
        RECT  139.2 274.916 139.224 275 ;
    END
  END snoop_data_o[500]
  PIN snoop_data_o[501]
    DIRECTION OUTPUT ;
    USE SIGNAL ;
    PORT
      LAYER M5 ;
        RECT  125.088 274.916 125.112 275 ;
    END
  END snoop_data_o[501]
  PIN snoop_data_o[502]
    DIRECTION OUTPUT ;
    USE SIGNAL ;
    PORT
      LAYER M5 ;
        RECT  124.32 274.916 124.344 275 ;
    END
  END snoop_data_o[502]
  PIN snoop_data_o[503]
    DIRECTION OUTPUT ;
    USE SIGNAL ;
    PORT
      LAYER M5 ;
        RECT  124.608 274.916 124.632 275 ;
    END
  END snoop_data_o[503]
  PIN snoop_data_o[504]
    DIRECTION OUTPUT ;
    USE SIGNAL ;
    PORT
      LAYER M5 ;
        RECT  124.896 274.916 124.92 275 ;
    END
  END snoop_data_o[504]
  PIN snoop_data_o[505]
    DIRECTION OUTPUT ;
    USE SIGNAL ;
    PORT
      LAYER M5 ;
        RECT  124.992 274.916 125.016 275 ;
    END
  END snoop_data_o[505]
  PIN snoop_data_o[506]
    DIRECTION OUTPUT ;
    USE SIGNAL ;
    PORT
      LAYER M5 ;
        RECT  124.416 274.916 124.44 275 ;
    END
  END snoop_data_o[506]
  PIN snoop_data_o[507]
    DIRECTION OUTPUT ;
    USE SIGNAL ;
    PORT
      LAYER M5 ;
        RECT  124.512 274.916 124.536 275 ;
    END
  END snoop_data_o[507]
  PIN snoop_data_o[508]
    DIRECTION OUTPUT ;
    USE SIGNAL ;
    PORT
      LAYER M5 ;
        RECT  124.8 274.916 124.824 275 ;
    END
  END snoop_data_o[508]
  PIN snoop_data_o[509]
    DIRECTION OUTPUT ;
    USE SIGNAL ;
    PORT
      LAYER M5 ;
        RECT  124.704 274.916 124.728 275 ;
    END
  END snoop_data_o[509]
  PIN snoop_data_o[50]
    DIRECTION OUTPUT ;
    USE SIGNAL ;
    PORT
      LAYER M5 ;
        RECT  43.104 274.916 43.128 275 ;
    END
  END snoop_data_o[50]
  PIN snoop_data_o[510]
    DIRECTION OUTPUT ;
    USE SIGNAL ;
    PORT
      LAYER M5 ;
        RECT  124.224 274.916 124.248 275 ;
    END
  END snoop_data_o[510]
  PIN snoop_data_o[511]
    DIRECTION OUTPUT ;
    USE SIGNAL ;
    PORT
      LAYER M5 ;
        RECT  126.816 274.916 126.84 275 ;
    END
  END snoop_data_o[511]
  PIN snoop_data_o[51]
    DIRECTION OUTPUT ;
    USE SIGNAL ;
    PORT
      LAYER M5 ;
        RECT  43.776 274.916 43.8 275 ;
    END
  END snoop_data_o[51]
  PIN snoop_data_o[52]
    DIRECTION OUTPUT ;
    USE SIGNAL ;
    PORT
      LAYER M5 ;
        RECT  43.968 274.916 43.992 275 ;
    END
  END snoop_data_o[52]
  PIN snoop_data_o[53]
    DIRECTION OUTPUT ;
    USE SIGNAL ;
    PORT
      LAYER M5 ;
        RECT  42.144 274.916 42.168 275 ;
    END
  END snoop_data_o[53]
  PIN snoop_data_o[54]
    DIRECTION OUTPUT ;
    USE SIGNAL ;
    PORT
      LAYER M5 ;
        RECT  43.872 274.916 43.896 275 ;
    END
  END snoop_data_o[54]
  PIN snoop_data_o[55]
    DIRECTION OUTPUT ;
    USE SIGNAL ;
    PORT
      LAYER M5 ;
        RECT  38.784 274.916 38.808 275 ;
    END
  END snoop_data_o[55]
  PIN snoop_data_o[56]
    DIRECTION OUTPUT ;
    USE SIGNAL ;
    PORT
      LAYER M5 ;
        RECT  38.976 274.916 39 275 ;
    END
  END snoop_data_o[56]
  PIN snoop_data_o[57]
    DIRECTION OUTPUT ;
    USE SIGNAL ;
    PORT
      LAYER M5 ;
        RECT  40.128 274.916 40.152 275 ;
    END
  END snoop_data_o[57]
  PIN snoop_data_o[58]
    DIRECTION OUTPUT ;
    USE SIGNAL ;
    PORT
      LAYER M5 ;
        RECT  38.112 274.916 38.136 275 ;
    END
  END snoop_data_o[58]
  PIN snoop_data_o[59]
    DIRECTION OUTPUT ;
    USE SIGNAL ;
    PORT
      LAYER M5 ;
        RECT  39.456 274.916 39.48 275 ;
    END
  END snoop_data_o[59]
  PIN snoop_data_o[5]
    DIRECTION OUTPUT ;
    USE SIGNAL ;
    PORT
      LAYER M5 ;
        RECT  32.736 274.916 32.76 275 ;
    END
  END snoop_data_o[5]
  PIN snoop_data_o[60]
    DIRECTION OUTPUT ;
    USE SIGNAL ;
    PORT
      LAYER M5 ;
        RECT  39.072 274.916 39.096 275 ;
    END
  END snoop_data_o[60]
  PIN snoop_data_o[61]
    DIRECTION OUTPUT ;
    USE SIGNAL ;
    PORT
      LAYER M5 ;
        RECT  39.552 274.916 39.576 275 ;
    END
  END snoop_data_o[61]
  PIN snoop_data_o[62]
    DIRECTION OUTPUT ;
    USE SIGNAL ;
    PORT
      LAYER M5 ;
        RECT  45.792 274.916 45.816 275 ;
    END
  END snoop_data_o[62]
  PIN snoop_data_o[63]
    DIRECTION OUTPUT ;
    USE SIGNAL ;
    PORT
      LAYER M5 ;
        RECT  45.024 274.916 45.048 275 ;
    END
  END snoop_data_o[63]
  PIN snoop_data_o[64]
    DIRECTION OUTPUT ;
    USE SIGNAL ;
    PORT
      LAYER M5 ;
        RECT  30.72 274.916 30.744 275 ;
    END
  END snoop_data_o[64]
  PIN snoop_data_o[65]
    DIRECTION OUTPUT ;
    USE SIGNAL ;
    PORT
      LAYER M5 ;
        RECT  35.424 274.916 35.448 275 ;
    END
  END snoop_data_o[65]
  PIN snoop_data_o[66]
    DIRECTION OUTPUT ;
    USE SIGNAL ;
    PORT
      LAYER M5 ;
        RECT  33.12 274.916 33.144 275 ;
    END
  END snoop_data_o[66]
  PIN snoop_data_o[67]
    DIRECTION OUTPUT ;
    USE SIGNAL ;
    PORT
      LAYER M5 ;
        RECT  33.984 274.916 34.008 275 ;
    END
  END snoop_data_o[67]
  PIN snoop_data_o[68]
    DIRECTION OUTPUT ;
    USE SIGNAL ;
    PORT
      LAYER M5 ;
        RECT  36.384 274.916 36.408 275 ;
    END
  END snoop_data_o[68]
  PIN snoop_data_o[69]
    DIRECTION OUTPUT ;
    USE SIGNAL ;
    PORT
      LAYER M5 ;
        RECT  32.256 274.916 32.28 275 ;
    END
  END snoop_data_o[69]
  PIN snoop_data_o[6]
    DIRECTION OUTPUT ;
    USE SIGNAL ;
    PORT
      LAYER M5 ;
        RECT  32.16 274.916 32.184 275 ;
    END
  END snoop_data_o[6]
  PIN snoop_data_o[70]
    DIRECTION OUTPUT ;
    USE SIGNAL ;
    PORT
      LAYER M5 ;
        RECT  30.912 274.916 30.936 275 ;
    END
  END snoop_data_o[70]
  PIN snoop_data_o[71]
    DIRECTION OUTPUT ;
    USE SIGNAL ;
    PORT
      LAYER M5 ;
        RECT  34.944 274.916 34.968 275 ;
    END
  END snoop_data_o[71]
  PIN snoop_data_o[72]
    DIRECTION OUTPUT ;
    USE SIGNAL ;
    PORT
      LAYER M5 ;
        RECT  32.352 274.916 32.376 275 ;
    END
  END snoop_data_o[72]
  PIN snoop_data_o[73]
    DIRECTION OUTPUT ;
    USE SIGNAL ;
    PORT
      LAYER M5 ;
        RECT  36.096 274.916 36.12 275 ;
    END
  END snoop_data_o[73]
  PIN snoop_data_o[74]
    DIRECTION OUTPUT ;
    USE SIGNAL ;
    PORT
      LAYER M5 ;
        RECT  36.672 274.916 36.696 275 ;
    END
  END snoop_data_o[74]
  PIN snoop_data_o[75]
    DIRECTION OUTPUT ;
    USE SIGNAL ;
    PORT
      LAYER M5 ;
        RECT  39.36 274.916 39.384 275 ;
    END
  END snoop_data_o[75]
  PIN snoop_data_o[76]
    DIRECTION OUTPUT ;
    USE SIGNAL ;
    PORT
      LAYER M5 ;
        RECT  38.592 274.916 38.616 275 ;
    END
  END snoop_data_o[76]
  PIN snoop_data_o[77]
    DIRECTION OUTPUT ;
    USE SIGNAL ;
    PORT
      LAYER M5 ;
        RECT  37.92 274.916 37.944 275 ;
    END
  END snoop_data_o[77]
  PIN snoop_data_o[78]
    DIRECTION OUTPUT ;
    USE SIGNAL ;
    PORT
      LAYER M5 ;
        RECT  29.952 274.916 29.976 275 ;
    END
  END snoop_data_o[78]
  PIN snoop_data_o[79]
    DIRECTION OUTPUT ;
    USE SIGNAL ;
    PORT
      LAYER M5 ;
        RECT  36.48 274.916 36.504 275 ;
    END
  END snoop_data_o[79]
  PIN snoop_data_o[7]
    DIRECTION OUTPUT ;
    USE SIGNAL ;
    PORT
      LAYER M5 ;
        RECT  32.64 274.916 32.664 275 ;
    END
  END snoop_data_o[7]
  PIN snoop_data_o[80]
    DIRECTION OUTPUT ;
    USE SIGNAL ;
    PORT
      LAYER M5 ;
        RECT  45.984 274.916 46.008 275 ;
    END
  END snoop_data_o[80]
  PIN snoop_data_o[81]
    DIRECTION OUTPUT ;
    USE SIGNAL ;
    PORT
      LAYER M5 ;
        RECT  38.4 274.916 38.424 275 ;
    END
  END snoop_data_o[81]
  PIN snoop_data_o[82]
    DIRECTION OUTPUT ;
    USE SIGNAL ;
    PORT
      LAYER M5 ;
        RECT  45.888 274.916 45.912 275 ;
    END
  END snoop_data_o[82]
  PIN snoop_data_o[83]
    DIRECTION OUTPUT ;
    USE SIGNAL ;
    PORT
      LAYER M5 ;
        RECT  38.496 274.916 38.52 275 ;
    END
  END snoop_data_o[83]
  PIN snoop_data_o[84]
    DIRECTION OUTPUT ;
    USE SIGNAL ;
    PORT
      LAYER M5 ;
        RECT  39.264 274.916 39.288 275 ;
    END
  END snoop_data_o[84]
  PIN snoop_data_o[85]
    DIRECTION OUTPUT ;
    USE SIGNAL ;
    PORT
      LAYER M5 ;
        RECT  43.392 274.916 43.416 275 ;
    END
  END snoop_data_o[85]
  PIN snoop_data_o[86]
    DIRECTION OUTPUT ;
    USE SIGNAL ;
    PORT
      LAYER M5 ;
        RECT  40.512 274.916 40.536 275 ;
    END
  END snoop_data_o[86]
  PIN snoop_data_o[87]
    DIRECTION OUTPUT ;
    USE SIGNAL ;
    PORT
      LAYER M5 ;
        RECT  43.584 274.916 43.608 275 ;
    END
  END snoop_data_o[87]
  PIN snoop_data_o[88]
    DIRECTION OUTPUT ;
    USE SIGNAL ;
    PORT
      LAYER M5 ;
        RECT  41.088 274.916 41.112 275 ;
    END
  END snoop_data_o[88]
  PIN snoop_data_o[89]
    DIRECTION OUTPUT ;
    USE SIGNAL ;
    PORT
      LAYER M5 ;
        RECT  43.296 274.916 43.32 275 ;
    END
  END snoop_data_o[89]
  PIN snoop_data_o[8]
    DIRECTION OUTPUT ;
    USE SIGNAL ;
    PORT
      LAYER M5 ;
        RECT  30.432 274.916 30.456 275 ;
    END
  END snoop_data_o[8]
  PIN snoop_data_o[90]
    DIRECTION OUTPUT ;
    USE SIGNAL ;
    PORT
      LAYER M5 ;
        RECT  43.68 274.916 43.704 275 ;
    END
  END snoop_data_o[90]
  PIN snoop_data_o[91]
    DIRECTION OUTPUT ;
    USE SIGNAL ;
    PORT
      LAYER M5 ;
        RECT  41.76 274.916 41.784 275 ;
    END
  END snoop_data_o[91]
  PIN snoop_data_o[92]
    DIRECTION OUTPUT ;
    USE SIGNAL ;
    PORT
      LAYER M5 ;
        RECT  43.008 274.916 43.032 275 ;
    END
  END snoop_data_o[92]
  PIN snoop_data_o[93]
    DIRECTION OUTPUT ;
    USE SIGNAL ;
    PORT
      LAYER M5 ;
        RECT  40.896 274.916 40.92 275 ;
    END
  END snoop_data_o[93]
  PIN snoop_data_o[94]
    DIRECTION OUTPUT ;
    USE SIGNAL ;
    PORT
      LAYER M5 ;
        RECT  40.992 274.916 41.016 275 ;
    END
  END snoop_data_o[94]
  PIN snoop_data_o[95]
    DIRECTION OUTPUT ;
    USE SIGNAL ;
    PORT
      LAYER M5 ;
        RECT  31.104 274.916 31.128 275 ;
    END
  END snoop_data_o[95]
  PIN snoop_data_o[96]
    DIRECTION OUTPUT ;
    USE SIGNAL ;
    PORT
      LAYER M5 ;
        RECT  37.824 274.916 37.848 275 ;
    END
  END snoop_data_o[96]
  PIN snoop_data_o[97]
    DIRECTION OUTPUT ;
    USE SIGNAL ;
    PORT
      LAYER M5 ;
        RECT  29.856 274.916 29.88 275 ;
    END
  END snoop_data_o[97]
  PIN snoop_data_o[98]
    DIRECTION OUTPUT ;
    USE SIGNAL ;
    PORT
      LAYER M5 ;
        RECT  36.576 274.916 36.6 275 ;
    END
  END snoop_data_o[98]
  PIN snoop_data_o[99]
    DIRECTION OUTPUT ;
    USE SIGNAL ;
    PORT
      LAYER M5 ;
        RECT  35.808 274.916 35.832 275 ;
    END
  END snoop_data_o[99]
  PIN snoop_data_o[9]
    DIRECTION OUTPUT ;
    USE SIGNAL ;
    PORT
      LAYER M5 ;
        RECT  37.056 274.916 37.08 275 ;
    END
  END snoop_data_o[9]
  PIN snoop_dirty_o[0]
    DIRECTION OUTPUT ;
    USE SIGNAL ;
    PORT
      LAYER M5 ;
        RECT  47.712 274.916 47.736 275 ;
    END
  END snoop_dirty_o[0]
  PIN snoop_dirty_o[1]
    DIRECTION OUTPUT ;
    USE SIGNAL ;
    PORT
      LAYER M5 ;
        RECT  108.192 274.916 108.216 275 ;
    END
  END snoop_dirty_o[1]
  PIN snoop_hit_o[0]
    DIRECTION OUTPUT ;
    USE SIGNAL ;
    PORT
      LAYER M5 ;
        RECT  47.424 274.916 47.448 275 ;
    END
  END snoop_hit_o[0]
  PIN snoop_hit_o[1]
    DIRECTION OUTPUT ;
    USE SIGNAL ;
    PORT
      LAYER M5 ;
        RECT  108.48 274.916 108.504 275 ;
    END
  END snoop_hit_o[1]
  PIN snoop_type_i
    DIRECTION INPUT ;
    USE SIGNAL ;
    PORT
      LAYER M5 ;
        RECT  103.104 274.916 103.128 275 ;
    END
  END snoop_type_i
  PIN snoop_valid_i[0]
    DIRECTION INPUT ;
    USE SIGNAL ;
    PORT
      LAYER M5 ;
        RECT  67.2 274.916 67.224 275 ;
    END
  END snoop_valid_i[0]
  PIN snoop_valid_i[1]
    DIRECTION INPUT ;
    USE SIGNAL ;
    PORT
      LAYER M5 ;
        RECT  104.544 274.916 104.568 275 ;
    END
  END snoop_valid_i[1]
  PIN VDD
    DIRECTION INOUT ;
    USE POWER ;
    PORT
      LAYER M6 ;
        RECT  1.026 271.833 160.974 272.121 ;
        RECT  1.026 266.433 160.974 266.721 ;
        RECT  1.026 261.033 160.974 261.321 ;
        RECT  1.026 255.633 160.974 255.921 ;
        RECT  1.026 250.233 160.974 250.521 ;
        RECT  1.026 244.833 160.974 245.121 ;
        RECT  1.026 239.433 160.974 239.721 ;
        RECT  1.026 234.033 160.974 234.321 ;
        RECT  1.026 228.633 160.974 228.921 ;
        RECT  1.026 223.233 160.974 223.521 ;
        RECT  1.026 217.833 160.974 218.121 ;
        RECT  1.026 212.433 160.974 212.721 ;
        RECT  1.026 207.033 160.974 207.321 ;
        RECT  1.026 201.633 160.974 201.921 ;
        RECT  1.026 196.233 160.974 196.521 ;
        RECT  1.026 190.833 160.974 191.121 ;
        RECT  1.026 185.433 160.974 185.721 ;
        RECT  1.026 180.033 160.974 180.321 ;
        RECT  1.026 174.633 160.974 174.921 ;
        RECT  1.026 169.233 160.974 169.521 ;
        RECT  1.026 163.833 160.974 164.121 ;
        RECT  1.026 158.433 160.974 158.721 ;
        RECT  1.026 153.033 160.974 153.321 ;
        RECT  1.026 147.633 160.974 147.921 ;
        RECT  1.026 142.233 160.974 142.521 ;
        RECT  1.026 136.833 160.974 137.121 ;
        RECT  1.026 131.433 160.974 131.721 ;
        RECT  1.026 126.033 160.974 126.321 ;
        RECT  1.026 120.633 160.974 120.921 ;
        RECT  1.026 115.233 160.974 115.521 ;
        RECT  1.026 109.833 160.974 110.121 ;
        RECT  1.026 104.433 160.974 104.721 ;
        RECT  1.026 99.033 160.974 99.321 ;
        RECT  1.026 93.633 160.974 93.921 ;
        RECT  1.026 88.233 160.974 88.521 ;
        RECT  1.026 82.833 160.974 83.121 ;
        RECT  1.026 77.433 160.974 77.721 ;
        RECT  1.026 72.033 160.974 72.321 ;
        RECT  1.026 66.633 160.974 66.921 ;
        RECT  1.026 61.233 160.974 61.521 ;
        RECT  1.026 55.833 160.974 56.121 ;
        RECT  1.026 50.433 160.974 50.721 ;
        RECT  1.026 45.033 160.974 45.321 ;
        RECT  1.026 39.633 160.974 39.921 ;
        RECT  1.026 34.233 160.974 34.521 ;
        RECT  1.026 28.833 160.974 29.121 ;
        RECT  1.026 23.433 160.974 23.721 ;
        RECT  1.026 18.033 160.974 18.321 ;
        RECT  1.026 12.633 160.974 12.921 ;
        RECT  1.026 7.233 160.974 7.521 ;
        RECT  1.026 1.833 160.974 2.121 ;
    END
  END VDD
  PIN VSS
    DIRECTION INOUT ;
    USE GROUND ;
    PORT
      LAYER M6 ;
        RECT  1.026 271.449 160.974 271.737 ;
        RECT  1.026 266.049 160.974 266.337 ;
        RECT  1.026 260.649 160.974 260.937 ;
        RECT  1.026 255.249 160.974 255.537 ;
        RECT  1.026 249.849 160.974 250.137 ;
        RECT  1.026 244.449 160.974 244.737 ;
        RECT  1.026 239.049 160.974 239.337 ;
        RECT  1.026 233.649 160.974 233.937 ;
        RECT  1.026 228.249 160.974 228.537 ;
        RECT  1.026 222.849 160.974 223.137 ;
        RECT  1.026 217.449 160.974 217.737 ;
        RECT  1.026 212.049 160.974 212.337 ;
        RECT  1.026 206.649 160.974 206.937 ;
        RECT  1.026 201.249 160.974 201.537 ;
        RECT  1.026 195.849 160.974 196.137 ;
        RECT  1.026 190.449 160.974 190.737 ;
        RECT  1.026 185.049 160.974 185.337 ;
        RECT  1.026 179.649 160.974 179.937 ;
        RECT  1.026 174.249 160.974 174.537 ;
        RECT  1.026 168.849 160.974 169.137 ;
        RECT  1.026 163.449 160.974 163.737 ;
        RECT  1.026 158.049 160.974 158.337 ;
        RECT  1.026 152.649 160.974 152.937 ;
        RECT  1.026 147.249 160.974 147.537 ;
        RECT  1.026 141.849 160.974 142.137 ;
        RECT  1.026 136.449 160.974 136.737 ;
        RECT  1.026 131.049 160.974 131.337 ;
        RECT  1.026 125.649 160.974 125.937 ;
        RECT  1.026 120.249 160.974 120.537 ;
        RECT  1.026 114.849 160.974 115.137 ;
        RECT  1.026 109.449 160.974 109.737 ;
        RECT  1.026 104.049 160.974 104.337 ;
        RECT  1.026 98.649 160.974 98.937 ;
        RECT  1.026 93.249 160.974 93.537 ;
        RECT  1.026 87.849 160.974 88.137 ;
        RECT  1.026 82.449 160.974 82.737 ;
        RECT  1.026 77.049 160.974 77.337 ;
        RECT  1.026 71.649 160.974 71.937 ;
        RECT  1.026 66.249 160.974 66.537 ;
        RECT  1.026 60.849 160.974 61.137 ;
        RECT  1.026 55.449 160.974 55.737 ;
        RECT  1.026 50.049 160.974 50.337 ;
        RECT  1.026 44.649 160.974 44.937 ;
        RECT  1.026 39.249 160.974 39.537 ;
        RECT  1.026 33.849 160.974 34.137 ;
        RECT  1.026 28.449 160.974 28.737 ;
        RECT  1.026 23.049 160.974 23.337 ;
        RECT  1.026 17.649 160.974 17.937 ;
        RECT  1.026 12.249 160.974 12.537 ;
        RECT  1.026 6.849 160.974 7.137 ;
        RECT  1.026 1.449 160.974 1.737 ;
    END
  END VSS
  OBS
    LAYER LVTN ;
     RECT  0 1.057 162 275 ;
    LAYER LVTP ;
     RECT  0 1.057 162 275 ;
    LAYER RVTN ;
     RECT  0 1.057 162 275 ;
    LAYER RVTP ;
     RECT  0 1.057 162 275 ;
    LAYER M1 ;
     RECT  0 1.057 162 275 ;
    LAYER M2 ;
     RECT  0 1.057 162 275 ;
    LAYER M3 ;
     RECT  0 1.057 162 275 ;
    LAYER M4 ;
     RECT  0 1.057 162 275 ;
    LAYER M5 ;
     RECT  0 1.057 162 275 ;
    LAYER M6 ;
     RECT  0 1.057 162 275 ;
  END
END p_tile
END LIBRARY
